VERSION 5.8 ;
BUSBITCHARS "[]" ;
DIVIDERCHAR "/" ;
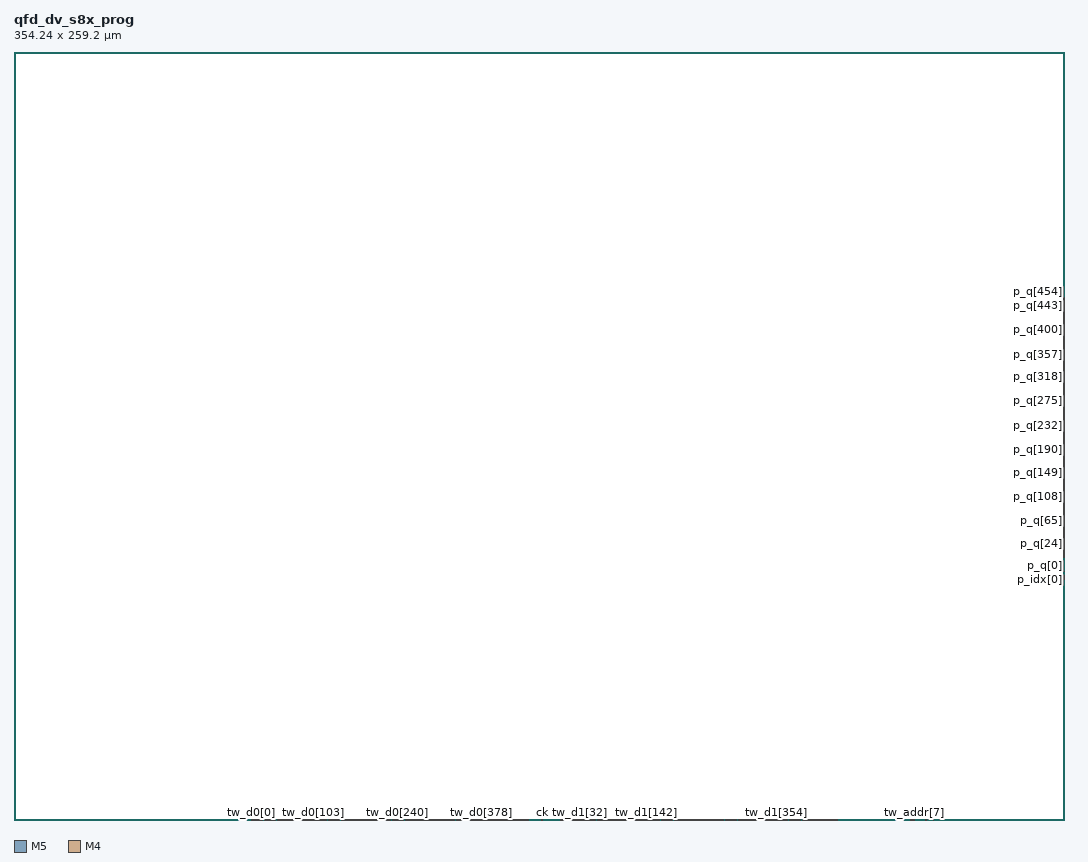
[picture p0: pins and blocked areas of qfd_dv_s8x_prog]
MACRO qfd_dv_s8x_prog
 CLASS BLOCK ;
 ORIGIN 0 0 ;
 SIZE 354.24 BY 259.2 ;
 SYMMETRY X Y ;
 PIN tw_d0[0]
  DIRECTION INPUT ;
  USE SIGNAL ;
  PORT
   LAYER M5 ;
   RECT 80.112000 0.000000 80.136000 0.084000 ;
  END
 END tw_d0[0]
 PIN tw_d0[1]
  DIRECTION INPUT ;
  USE SIGNAL ;
  PORT
   LAYER M5 ;
   RECT 80.304000 0.000000 80.328000 0.084000 ;
  END
 END tw_d0[1]
 PIN tw_d0[2]
  DIRECTION INPUT ;
  USE SIGNAL ;
  PORT
   LAYER M5 ;
   RECT 80.496000 0.000000 80.520000 0.084000 ;
  END
 END tw_d0[2]
 PIN tw_d0[3]
  DIRECTION INPUT ;
  USE SIGNAL ;
  PORT
   LAYER M5 ;
   RECT 80.688000 0.000000 80.712000 0.084000 ;
  END
 END tw_d0[3]
 PIN tw_d0[4]
  DIRECTION INPUT ;
  USE SIGNAL ;
  PORT
   LAYER M5 ;
   RECT 80.880000 0.000000 80.904000 0.084000 ;
  END
 END tw_d0[4]
 PIN tw_d0[5]
  DIRECTION INPUT ;
  USE SIGNAL ;
  PORT
   LAYER M5 ;
   RECT 81.072000 0.000000 81.096000 0.084000 ;
  END
 END tw_d0[5]
 PIN tw_d0[6]
  DIRECTION INPUT ;
  USE SIGNAL ;
  PORT
   LAYER M5 ;
   RECT 81.264000 0.000000 81.288000 0.084000 ;
  END
 END tw_d0[6]
 PIN tw_d0[7]
  DIRECTION INPUT ;
  USE SIGNAL ;
  PORT
   LAYER M5 ;
   RECT 81.456000 0.000000 81.480000 0.084000 ;
  END
 END tw_d0[7]
 PIN tw_d0[8]
  DIRECTION INPUT ;
  USE SIGNAL ;
  PORT
   LAYER M5 ;
   RECT 81.648000 0.000000 81.672000 0.084000 ;
  END
 END tw_d0[8]
 PIN tw_d0[9]
  DIRECTION INPUT ;
  USE SIGNAL ;
  PORT
   LAYER M5 ;
   RECT 81.840000 0.000000 81.864000 0.084000 ;
  END
 END tw_d0[9]
 PIN tw_d0[10]
  DIRECTION INPUT ;
  USE SIGNAL ;
  PORT
   LAYER M5 ;
   RECT 82.032000 0.000000 82.056000 0.084000 ;
  END
 END tw_d0[10]
 PIN tw_d0[11]
  DIRECTION INPUT ;
  USE SIGNAL ;
  PORT
   LAYER M5 ;
   RECT 82.224000 0.000000 82.248000 0.084000 ;
  END
 END tw_d0[11]
 PIN tw_d0[12]
  DIRECTION INPUT ;
  USE SIGNAL ;
  PORT
   LAYER M5 ;
   RECT 82.416000 0.000000 82.440000 0.084000 ;
  END
 END tw_d0[12]
 PIN tw_d0[13]
  DIRECTION INPUT ;
  USE SIGNAL ;
  PORT
   LAYER M5 ;
   RECT 82.608000 0.000000 82.632000 0.084000 ;
  END
 END tw_d0[13]
 PIN tw_d0[14]
  DIRECTION INPUT ;
  USE SIGNAL ;
  PORT
   LAYER M5 ;
   RECT 82.800000 0.000000 82.824000 0.084000 ;
  END
 END tw_d0[14]
 PIN tw_d0[15]
  DIRECTION INPUT ;
  USE SIGNAL ;
  PORT
   LAYER M5 ;
   RECT 82.992000 0.000000 83.016000 0.084000 ;
  END
 END tw_d0[15]
 PIN tw_d0[16]
  DIRECTION INPUT ;
  USE SIGNAL ;
  PORT
   LAYER M5 ;
   RECT 83.184000 0.000000 83.208000 0.084000 ;
  END
 END tw_d0[16]
 PIN tw_d0[17]
  DIRECTION INPUT ;
  USE SIGNAL ;
  PORT
   LAYER M5 ;
   RECT 83.376000 0.000000 83.400000 0.084000 ;
  END
 END tw_d0[17]
 PIN tw_d0[18]
  DIRECTION INPUT ;
  USE SIGNAL ;
  PORT
   LAYER M5 ;
   RECT 83.568000 0.000000 83.592000 0.084000 ;
  END
 END tw_d0[18]
 PIN tw_d0[19]
  DIRECTION INPUT ;
  USE SIGNAL ;
  PORT
   LAYER M5 ;
   RECT 83.760000 0.000000 83.784000 0.084000 ;
  END
 END tw_d0[19]
 PIN tw_d0[20]
  DIRECTION INPUT ;
  USE SIGNAL ;
  PORT
   LAYER M5 ;
   RECT 83.952000 0.000000 83.976000 0.084000 ;
  END
 END tw_d0[20]
 PIN tw_d0[21]
  DIRECTION INPUT ;
  USE SIGNAL ;
  PORT
   LAYER M5 ;
   RECT 84.432000 0.000000 84.456000 0.084000 ;
  END
 END tw_d0[21]
 PIN tw_d0[22]
  DIRECTION INPUT ;
  USE SIGNAL ;
  PORT
   LAYER M5 ;
   RECT 84.624000 0.000000 84.648000 0.084000 ;
  END
 END tw_d0[22]
 PIN tw_d0[23]
  DIRECTION INPUT ;
  USE SIGNAL ;
  PORT
   LAYER M5 ;
   RECT 84.816000 0.000000 84.840000 0.084000 ;
  END
 END tw_d0[23]
 PIN tw_d0[24]
  DIRECTION INPUT ;
  USE SIGNAL ;
  PORT
   LAYER M5 ;
   RECT 85.008000 0.000000 85.032000 0.084000 ;
  END
 END tw_d0[24]
 PIN tw_d0[25]
  DIRECTION INPUT ;
  USE SIGNAL ;
  PORT
   LAYER M5 ;
   RECT 85.200000 0.000000 85.224000 0.084000 ;
  END
 END tw_d0[25]
 PIN tw_d0[26]
  DIRECTION INPUT ;
  USE SIGNAL ;
  PORT
   LAYER M5 ;
   RECT 85.392000 0.000000 85.416000 0.084000 ;
  END
 END tw_d0[26]
 PIN tw_d0[27]
  DIRECTION INPUT ;
  USE SIGNAL ;
  PORT
   LAYER M5 ;
   RECT 85.584000 0.000000 85.608000 0.084000 ;
  END
 END tw_d0[27]
 PIN tw_d0[28]
  DIRECTION INPUT ;
  USE SIGNAL ;
  PORT
   LAYER M5 ;
   RECT 85.776000 0.000000 85.800000 0.084000 ;
  END
 END tw_d0[28]
 PIN tw_d0[29]
  DIRECTION INPUT ;
  USE SIGNAL ;
  PORT
   LAYER M5 ;
   RECT 85.968000 0.000000 85.992000 0.084000 ;
  END
 END tw_d0[29]
 PIN tw_d0[30]
  DIRECTION INPUT ;
  USE SIGNAL ;
  PORT
   LAYER M5 ;
   RECT 86.160000 0.000000 86.184000 0.084000 ;
  END
 END tw_d0[30]
 PIN tw_d0[31]
  DIRECTION INPUT ;
  USE SIGNAL ;
  PORT
   LAYER M5 ;
   RECT 86.352000 0.000000 86.376000 0.084000 ;
  END
 END tw_d0[31]
 PIN tw_d0[32]
  DIRECTION INPUT ;
  USE SIGNAL ;
  PORT
   LAYER M5 ;
   RECT 86.544000 0.000000 86.568000 0.084000 ;
  END
 END tw_d0[32]
 PIN tw_d0[33]
  DIRECTION INPUT ;
  USE SIGNAL ;
  PORT
   LAYER M5 ;
   RECT 86.736000 0.000000 86.760000 0.084000 ;
  END
 END tw_d0[33]
 PIN tw_d0[34]
  DIRECTION INPUT ;
  USE SIGNAL ;
  PORT
   LAYER M5 ;
   RECT 86.928000 0.000000 86.952000 0.084000 ;
  END
 END tw_d0[34]
 PIN tw_d0[35]
  DIRECTION INPUT ;
  USE SIGNAL ;
  PORT
   LAYER M5 ;
   RECT 87.120000 0.000000 87.144000 0.084000 ;
  END
 END tw_d0[35]
 PIN tw_d0[36]
  DIRECTION INPUT ;
  USE SIGNAL ;
  PORT
   LAYER M5 ;
   RECT 87.312000 0.000000 87.336000 0.084000 ;
  END
 END tw_d0[36]
 PIN tw_d0[37]
  DIRECTION INPUT ;
  USE SIGNAL ;
  PORT
   LAYER M5 ;
   RECT 87.504000 0.000000 87.528000 0.084000 ;
  END
 END tw_d0[37]
 PIN tw_d0[38]
  DIRECTION INPUT ;
  USE SIGNAL ;
  PORT
   LAYER M5 ;
   RECT 87.696000 0.000000 87.720000 0.084000 ;
  END
 END tw_d0[38]
 PIN tw_d0[39]
  DIRECTION INPUT ;
  USE SIGNAL ;
  PORT
   LAYER M5 ;
   RECT 87.888000 0.000000 87.912000 0.084000 ;
  END
 END tw_d0[39]
 PIN tw_d0[40]
  DIRECTION INPUT ;
  USE SIGNAL ;
  PORT
   LAYER M5 ;
   RECT 88.080000 0.000000 88.104000 0.084000 ;
  END
 END tw_d0[40]
 PIN tw_d0[41]
  DIRECTION INPUT ;
  USE SIGNAL ;
  PORT
   LAYER M5 ;
   RECT 88.272000 0.000000 88.296000 0.084000 ;
  END
 END tw_d0[41]
 PIN tw_d0[42]
  DIRECTION INPUT ;
  USE SIGNAL ;
  PORT
   LAYER M5 ;
   RECT 88.752000 0.000000 88.776000 0.084000 ;
  END
 END tw_d0[42]
 PIN tw_d0[43]
  DIRECTION INPUT ;
  USE SIGNAL ;
  PORT
   LAYER M5 ;
   RECT 88.944000 0.000000 88.968000 0.084000 ;
  END
 END tw_d0[43]
 PIN tw_d0[44]
  DIRECTION INPUT ;
  USE SIGNAL ;
  PORT
   LAYER M5 ;
   RECT 89.136000 0.000000 89.160000 0.084000 ;
  END
 END tw_d0[44]
 PIN tw_d0[45]
  DIRECTION INPUT ;
  USE SIGNAL ;
  PORT
   LAYER M5 ;
   RECT 89.328000 0.000000 89.352000 0.084000 ;
  END
 END tw_d0[45]
 PIN tw_d0[46]
  DIRECTION INPUT ;
  USE SIGNAL ;
  PORT
   LAYER M5 ;
   RECT 89.520000 0.000000 89.544000 0.084000 ;
  END
 END tw_d0[46]
 PIN tw_d0[47]
  DIRECTION INPUT ;
  USE SIGNAL ;
  PORT
   LAYER M5 ;
   RECT 89.712000 0.000000 89.736000 0.084000 ;
  END
 END tw_d0[47]
 PIN tw_d0[48]
  DIRECTION INPUT ;
  USE SIGNAL ;
  PORT
   LAYER M5 ;
   RECT 89.904000 0.000000 89.928000 0.084000 ;
  END
 END tw_d0[48]
 PIN tw_d0[49]
  DIRECTION INPUT ;
  USE SIGNAL ;
  PORT
   LAYER M5 ;
   RECT 90.096000 0.000000 90.120000 0.084000 ;
  END
 END tw_d0[49]
 PIN tw_d0[50]
  DIRECTION INPUT ;
  USE SIGNAL ;
  PORT
   LAYER M5 ;
   RECT 90.288000 0.000000 90.312000 0.084000 ;
  END
 END tw_d0[50]
 PIN tw_d0[51]
  DIRECTION INPUT ;
  USE SIGNAL ;
  PORT
   LAYER M5 ;
   RECT 90.480000 0.000000 90.504000 0.084000 ;
  END
 END tw_d0[51]
 PIN tw_d0[52]
  DIRECTION INPUT ;
  USE SIGNAL ;
  PORT
   LAYER M5 ;
   RECT 90.672000 0.000000 90.696000 0.084000 ;
  END
 END tw_d0[52]
 PIN tw_d0[53]
  DIRECTION INPUT ;
  USE SIGNAL ;
  PORT
   LAYER M5 ;
   RECT 90.864000 0.000000 90.888000 0.084000 ;
  END
 END tw_d0[53]
 PIN tw_d0[54]
  DIRECTION INPUT ;
  USE SIGNAL ;
  PORT
   LAYER M5 ;
   RECT 91.056000 0.000000 91.080000 0.084000 ;
  END
 END tw_d0[54]
 PIN tw_d0[55]
  DIRECTION INPUT ;
  USE SIGNAL ;
  PORT
   LAYER M5 ;
   RECT 91.248000 0.000000 91.272000 0.084000 ;
  END
 END tw_d0[55]
 PIN tw_d0[56]
  DIRECTION INPUT ;
  USE SIGNAL ;
  PORT
   LAYER M5 ;
   RECT 91.440000 0.000000 91.464000 0.084000 ;
  END
 END tw_d0[56]
 PIN tw_d0[57]
  DIRECTION INPUT ;
  USE SIGNAL ;
  PORT
   LAYER M5 ;
   RECT 91.632000 0.000000 91.656000 0.084000 ;
  END
 END tw_d0[57]
 PIN tw_d0[58]
  DIRECTION INPUT ;
  USE SIGNAL ;
  PORT
   LAYER M5 ;
   RECT 91.824000 0.000000 91.848000 0.084000 ;
  END
 END tw_d0[58]
 PIN tw_d0[59]
  DIRECTION INPUT ;
  USE SIGNAL ;
  PORT
   LAYER M5 ;
   RECT 92.016000 0.000000 92.040000 0.084000 ;
  END
 END tw_d0[59]
 PIN tw_d0[60]
  DIRECTION INPUT ;
  USE SIGNAL ;
  PORT
   LAYER M5 ;
   RECT 92.208000 0.000000 92.232000 0.084000 ;
  END
 END tw_d0[60]
 PIN tw_d0[61]
  DIRECTION INPUT ;
  USE SIGNAL ;
  PORT
   LAYER M5 ;
   RECT 92.400000 0.000000 92.424000 0.084000 ;
  END
 END tw_d0[61]
 PIN tw_d0[62]
  DIRECTION INPUT ;
  USE SIGNAL ;
  PORT
   LAYER M5 ;
   RECT 92.592000 0.000000 92.616000 0.084000 ;
  END
 END tw_d0[62]
 PIN tw_d0[63]
  DIRECTION INPUT ;
  USE SIGNAL ;
  PORT
   LAYER M5 ;
   RECT 93.072000 0.000000 93.096000 0.084000 ;
  END
 END tw_d0[63]
 PIN tw_d0[64]
  DIRECTION INPUT ;
  USE SIGNAL ;
  PORT
   LAYER M5 ;
   RECT 93.264000 0.000000 93.288000 0.084000 ;
  END
 END tw_d0[64]
 PIN tw_d0[65]
  DIRECTION INPUT ;
  USE SIGNAL ;
  PORT
   LAYER M5 ;
   RECT 93.456000 0.000000 93.480000 0.084000 ;
  END
 END tw_d0[65]
 PIN tw_d0[66]
  DIRECTION INPUT ;
  USE SIGNAL ;
  PORT
   LAYER M5 ;
   RECT 93.648000 0.000000 93.672000 0.084000 ;
  END
 END tw_d0[66]
 PIN tw_d0[67]
  DIRECTION INPUT ;
  USE SIGNAL ;
  PORT
   LAYER M5 ;
   RECT 93.840000 0.000000 93.864000 0.084000 ;
  END
 END tw_d0[67]
 PIN tw_d0[68]
  DIRECTION INPUT ;
  USE SIGNAL ;
  PORT
   LAYER M5 ;
   RECT 94.032000 0.000000 94.056000 0.084000 ;
  END
 END tw_d0[68]
 PIN tw_d0[69]
  DIRECTION INPUT ;
  USE SIGNAL ;
  PORT
   LAYER M5 ;
   RECT 94.224000 0.000000 94.248000 0.084000 ;
  END
 END tw_d0[69]
 PIN tw_d0[70]
  DIRECTION INPUT ;
  USE SIGNAL ;
  PORT
   LAYER M5 ;
   RECT 94.416000 0.000000 94.440000 0.084000 ;
  END
 END tw_d0[70]
 PIN tw_d0[71]
  DIRECTION INPUT ;
  USE SIGNAL ;
  PORT
   LAYER M5 ;
   RECT 94.608000 0.000000 94.632000 0.084000 ;
  END
 END tw_d0[71]
 PIN tw_d0[72]
  DIRECTION INPUT ;
  USE SIGNAL ;
  PORT
   LAYER M5 ;
   RECT 94.800000 0.000000 94.824000 0.084000 ;
  END
 END tw_d0[72]
 PIN tw_d0[73]
  DIRECTION INPUT ;
  USE SIGNAL ;
  PORT
   LAYER M5 ;
   RECT 94.992000 0.000000 95.016000 0.084000 ;
  END
 END tw_d0[73]
 PIN tw_d0[74]
  DIRECTION INPUT ;
  USE SIGNAL ;
  PORT
   LAYER M5 ;
   RECT 95.184000 0.000000 95.208000 0.084000 ;
  END
 END tw_d0[74]
 PIN tw_d0[75]
  DIRECTION INPUT ;
  USE SIGNAL ;
  PORT
   LAYER M5 ;
   RECT 95.376000 0.000000 95.400000 0.084000 ;
  END
 END tw_d0[75]
 PIN tw_d0[76]
  DIRECTION INPUT ;
  USE SIGNAL ;
  PORT
   LAYER M5 ;
   RECT 95.568000 0.000000 95.592000 0.084000 ;
  END
 END tw_d0[76]
 PIN tw_d0[77]
  DIRECTION INPUT ;
  USE SIGNAL ;
  PORT
   LAYER M5 ;
   RECT 95.760000 0.000000 95.784000 0.084000 ;
  END
 END tw_d0[77]
 PIN tw_d0[78]
  DIRECTION INPUT ;
  USE SIGNAL ;
  PORT
   LAYER M5 ;
   RECT 95.952000 0.000000 95.976000 0.084000 ;
  END
 END tw_d0[78]
 PIN tw_d0[79]
  DIRECTION INPUT ;
  USE SIGNAL ;
  PORT
   LAYER M5 ;
   RECT 96.144000 0.000000 96.168000 0.084000 ;
  END
 END tw_d0[79]
 PIN tw_d0[80]
  DIRECTION INPUT ;
  USE SIGNAL ;
  PORT
   LAYER M5 ;
   RECT 96.336000 0.000000 96.360000 0.084000 ;
  END
 END tw_d0[80]
 PIN tw_d0[81]
  DIRECTION INPUT ;
  USE SIGNAL ;
  PORT
   LAYER M5 ;
   RECT 96.528000 0.000000 96.552000 0.084000 ;
  END
 END tw_d0[81]
 PIN tw_d0[82]
  DIRECTION INPUT ;
  USE SIGNAL ;
  PORT
   LAYER M5 ;
   RECT 96.720000 0.000000 96.744000 0.084000 ;
  END
 END tw_d0[82]
 PIN tw_d0[83]
  DIRECTION INPUT ;
  USE SIGNAL ;
  PORT
   LAYER M5 ;
   RECT 96.912000 0.000000 96.936000 0.084000 ;
  END
 END tw_d0[83]
 PIN tw_d0[84]
  DIRECTION INPUT ;
  USE SIGNAL ;
  PORT
   LAYER M5 ;
   RECT 97.392000 0.000000 97.416000 0.084000 ;
  END
 END tw_d0[84]
 PIN tw_d0[85]
  DIRECTION INPUT ;
  USE SIGNAL ;
  PORT
   LAYER M5 ;
   RECT 97.584000 0.000000 97.608000 0.084000 ;
  END
 END tw_d0[85]
 PIN tw_d0[86]
  DIRECTION INPUT ;
  USE SIGNAL ;
  PORT
   LAYER M5 ;
   RECT 97.776000 0.000000 97.800000 0.084000 ;
  END
 END tw_d0[86]
 PIN tw_d0[87]
  DIRECTION INPUT ;
  USE SIGNAL ;
  PORT
   LAYER M5 ;
   RECT 97.968000 0.000000 97.992000 0.084000 ;
  END
 END tw_d0[87]
 PIN tw_d0[88]
  DIRECTION INPUT ;
  USE SIGNAL ;
  PORT
   LAYER M5 ;
   RECT 98.160000 0.000000 98.184000 0.084000 ;
  END
 END tw_d0[88]
 PIN tw_d0[89]
  DIRECTION INPUT ;
  USE SIGNAL ;
  PORT
   LAYER M5 ;
   RECT 98.352000 0.000000 98.376000 0.084000 ;
  END
 END tw_d0[89]
 PIN tw_d0[90]
  DIRECTION INPUT ;
  USE SIGNAL ;
  PORT
   LAYER M5 ;
   RECT 98.544000 0.000000 98.568000 0.084000 ;
  END
 END tw_d0[90]
 PIN tw_d0[91]
  DIRECTION INPUT ;
  USE SIGNAL ;
  PORT
   LAYER M5 ;
   RECT 98.736000 0.000000 98.760000 0.084000 ;
  END
 END tw_d0[91]
 PIN tw_d0[92]
  DIRECTION INPUT ;
  USE SIGNAL ;
  PORT
   LAYER M5 ;
   RECT 98.928000 0.000000 98.952000 0.084000 ;
  END
 END tw_d0[92]
 PIN tw_d0[93]
  DIRECTION INPUT ;
  USE SIGNAL ;
  PORT
   LAYER M5 ;
   RECT 99.120000 0.000000 99.144000 0.084000 ;
  END
 END tw_d0[93]
 PIN tw_d0[94]
  DIRECTION INPUT ;
  USE SIGNAL ;
  PORT
   LAYER M5 ;
   RECT 99.312000 0.000000 99.336000 0.084000 ;
  END
 END tw_d0[94]
 PIN tw_d0[95]
  DIRECTION INPUT ;
  USE SIGNAL ;
  PORT
   LAYER M5 ;
   RECT 99.504000 0.000000 99.528000 0.084000 ;
  END
 END tw_d0[95]
 PIN tw_d0[96]
  DIRECTION INPUT ;
  USE SIGNAL ;
  PORT
   LAYER M5 ;
   RECT 99.696000 0.000000 99.720000 0.084000 ;
  END
 END tw_d0[96]
 PIN tw_d0[97]
  DIRECTION INPUT ;
  USE SIGNAL ;
  PORT
   LAYER M5 ;
   RECT 99.888000 0.000000 99.912000 0.084000 ;
  END
 END tw_d0[97]
 PIN tw_d0[98]
  DIRECTION INPUT ;
  USE SIGNAL ;
  PORT
   LAYER M5 ;
   RECT 100.080000 0.000000 100.104000 0.084000 ;
  END
 END tw_d0[98]
 PIN tw_d0[99]
  DIRECTION INPUT ;
  USE SIGNAL ;
  PORT
   LAYER M5 ;
   RECT 100.272000 0.000000 100.296000 0.084000 ;
  END
 END tw_d0[99]
 PIN tw_d0[100]
  DIRECTION INPUT ;
  USE SIGNAL ;
  PORT
   LAYER M5 ;
   RECT 100.464000 0.000000 100.488000 0.084000 ;
  END
 END tw_d0[100]
 PIN tw_d0[101]
  DIRECTION INPUT ;
  USE SIGNAL ;
  PORT
   LAYER M5 ;
   RECT 100.656000 0.000000 100.680000 0.084000 ;
  END
 END tw_d0[101]
 PIN tw_d0[102]
  DIRECTION INPUT ;
  USE SIGNAL ;
  PORT
   LAYER M5 ;
   RECT 100.848000 0.000000 100.872000 0.084000 ;
  END
 END tw_d0[102]
 PIN tw_d0[103]
  DIRECTION INPUT ;
  USE SIGNAL ;
  PORT
   LAYER M5 ;
   RECT 101.040000 0.000000 101.064000 0.084000 ;
  END
 END tw_d0[103]
 PIN tw_d0[104]
  DIRECTION INPUT ;
  USE SIGNAL ;
  PORT
   LAYER M5 ;
   RECT 101.232000 0.000000 101.256000 0.084000 ;
  END
 END tw_d0[104]
 PIN tw_d0[105]
  DIRECTION INPUT ;
  USE SIGNAL ;
  PORT
   LAYER M5 ;
   RECT 101.712000 0.000000 101.736000 0.084000 ;
  END
 END tw_d0[105]
 PIN tw_d0[106]
  DIRECTION INPUT ;
  USE SIGNAL ;
  PORT
   LAYER M5 ;
   RECT 101.904000 0.000000 101.928000 0.084000 ;
  END
 END tw_d0[106]
 PIN tw_d0[107]
  DIRECTION INPUT ;
  USE SIGNAL ;
  PORT
   LAYER M5 ;
   RECT 102.096000 0.000000 102.120000 0.084000 ;
  END
 END tw_d0[107]
 PIN tw_d0[108]
  DIRECTION INPUT ;
  USE SIGNAL ;
  PORT
   LAYER M5 ;
   RECT 102.288000 0.000000 102.312000 0.084000 ;
  END
 END tw_d0[108]
 PIN tw_d0[109]
  DIRECTION INPUT ;
  USE SIGNAL ;
  PORT
   LAYER M5 ;
   RECT 102.480000 0.000000 102.504000 0.084000 ;
  END
 END tw_d0[109]
 PIN tw_d0[110]
  DIRECTION INPUT ;
  USE SIGNAL ;
  PORT
   LAYER M5 ;
   RECT 102.672000 0.000000 102.696000 0.084000 ;
  END
 END tw_d0[110]
 PIN tw_d0[111]
  DIRECTION INPUT ;
  USE SIGNAL ;
  PORT
   LAYER M5 ;
   RECT 102.864000 0.000000 102.888000 0.084000 ;
  END
 END tw_d0[111]
 PIN tw_d0[112]
  DIRECTION INPUT ;
  USE SIGNAL ;
  PORT
   LAYER M5 ;
   RECT 103.056000 0.000000 103.080000 0.084000 ;
  END
 END tw_d0[112]
 PIN tw_d0[113]
  DIRECTION INPUT ;
  USE SIGNAL ;
  PORT
   LAYER M5 ;
   RECT 103.248000 0.000000 103.272000 0.084000 ;
  END
 END tw_d0[113]
 PIN tw_d0[114]
  DIRECTION INPUT ;
  USE SIGNAL ;
  PORT
   LAYER M5 ;
   RECT 103.440000 0.000000 103.464000 0.084000 ;
  END
 END tw_d0[114]
 PIN tw_d0[115]
  DIRECTION INPUT ;
  USE SIGNAL ;
  PORT
   LAYER M5 ;
   RECT 103.632000 0.000000 103.656000 0.084000 ;
  END
 END tw_d0[115]
 PIN tw_d0[116]
  DIRECTION INPUT ;
  USE SIGNAL ;
  PORT
   LAYER M5 ;
   RECT 103.824000 0.000000 103.848000 0.084000 ;
  END
 END tw_d0[116]
 PIN tw_d0[117]
  DIRECTION INPUT ;
  USE SIGNAL ;
  PORT
   LAYER M5 ;
   RECT 104.016000 0.000000 104.040000 0.084000 ;
  END
 END tw_d0[117]
 PIN tw_d0[118]
  DIRECTION INPUT ;
  USE SIGNAL ;
  PORT
   LAYER M5 ;
   RECT 104.208000 0.000000 104.232000 0.084000 ;
  END
 END tw_d0[118]
 PIN tw_d0[119]
  DIRECTION INPUT ;
  USE SIGNAL ;
  PORT
   LAYER M5 ;
   RECT 104.400000 0.000000 104.424000 0.084000 ;
  END
 END tw_d0[119]
 PIN tw_d0[120]
  DIRECTION INPUT ;
  USE SIGNAL ;
  PORT
   LAYER M5 ;
   RECT 104.592000 0.000000 104.616000 0.084000 ;
  END
 END tw_d0[120]
 PIN tw_d0[121]
  DIRECTION INPUT ;
  USE SIGNAL ;
  PORT
   LAYER M5 ;
   RECT 104.784000 0.000000 104.808000 0.084000 ;
  END
 END tw_d0[121]
 PIN tw_d0[122]
  DIRECTION INPUT ;
  USE SIGNAL ;
  PORT
   LAYER M5 ;
   RECT 104.976000 0.000000 105.000000 0.084000 ;
  END
 END tw_d0[122]
 PIN tw_d0[123]
  DIRECTION INPUT ;
  USE SIGNAL ;
  PORT
   LAYER M5 ;
   RECT 105.168000 0.000000 105.192000 0.084000 ;
  END
 END tw_d0[123]
 PIN tw_d0[124]
  DIRECTION INPUT ;
  USE SIGNAL ;
  PORT
   LAYER M5 ;
   RECT 105.360000 0.000000 105.384000 0.084000 ;
  END
 END tw_d0[124]
 PIN tw_d0[125]
  DIRECTION INPUT ;
  USE SIGNAL ;
  PORT
   LAYER M5 ;
   RECT 105.552000 0.000000 105.576000 0.084000 ;
  END
 END tw_d0[125]
 PIN tw_d0[126]
  DIRECTION INPUT ;
  USE SIGNAL ;
  PORT
   LAYER M5 ;
   RECT 106.032000 0.000000 106.056000 0.084000 ;
  END
 END tw_d0[126]
 PIN tw_d0[127]
  DIRECTION INPUT ;
  USE SIGNAL ;
  PORT
   LAYER M5 ;
   RECT 106.224000 0.000000 106.248000 0.084000 ;
  END
 END tw_d0[127]
 PIN tw_d0[128]
  DIRECTION INPUT ;
  USE SIGNAL ;
  PORT
   LAYER M5 ;
   RECT 106.416000 0.000000 106.440000 0.084000 ;
  END
 END tw_d0[128]
 PIN tw_d0[129]
  DIRECTION INPUT ;
  USE SIGNAL ;
  PORT
   LAYER M5 ;
   RECT 106.608000 0.000000 106.632000 0.084000 ;
  END
 END tw_d0[129]
 PIN tw_d0[130]
  DIRECTION INPUT ;
  USE SIGNAL ;
  PORT
   LAYER M5 ;
   RECT 106.800000 0.000000 106.824000 0.084000 ;
  END
 END tw_d0[130]
 PIN tw_d0[131]
  DIRECTION INPUT ;
  USE SIGNAL ;
  PORT
   LAYER M5 ;
   RECT 106.992000 0.000000 107.016000 0.084000 ;
  END
 END tw_d0[131]
 PIN tw_d0[132]
  DIRECTION INPUT ;
  USE SIGNAL ;
  PORT
   LAYER M5 ;
   RECT 107.184000 0.000000 107.208000 0.084000 ;
  END
 END tw_d0[132]
 PIN tw_d0[133]
  DIRECTION INPUT ;
  USE SIGNAL ;
  PORT
   LAYER M5 ;
   RECT 107.376000 0.000000 107.400000 0.084000 ;
  END
 END tw_d0[133]
 PIN tw_d0[134]
  DIRECTION INPUT ;
  USE SIGNAL ;
  PORT
   LAYER M5 ;
   RECT 107.568000 0.000000 107.592000 0.084000 ;
  END
 END tw_d0[134]
 PIN tw_d0[135]
  DIRECTION INPUT ;
  USE SIGNAL ;
  PORT
   LAYER M5 ;
   RECT 107.760000 0.000000 107.784000 0.084000 ;
  END
 END tw_d0[135]
 PIN tw_d0[136]
  DIRECTION INPUT ;
  USE SIGNAL ;
  PORT
   LAYER M5 ;
   RECT 107.952000 0.000000 107.976000 0.084000 ;
  END
 END tw_d0[136]
 PIN tw_d0[137]
  DIRECTION INPUT ;
  USE SIGNAL ;
  PORT
   LAYER M5 ;
   RECT 108.144000 0.000000 108.168000 0.084000 ;
  END
 END tw_d0[137]
 PIN tw_d0[138]
  DIRECTION INPUT ;
  USE SIGNAL ;
  PORT
   LAYER M5 ;
   RECT 108.336000 0.000000 108.360000 0.084000 ;
  END
 END tw_d0[138]
 PIN tw_d0[139]
  DIRECTION INPUT ;
  USE SIGNAL ;
  PORT
   LAYER M5 ;
   RECT 108.528000 0.000000 108.552000 0.084000 ;
  END
 END tw_d0[139]
 PIN tw_d0[140]
  DIRECTION INPUT ;
  USE SIGNAL ;
  PORT
   LAYER M5 ;
   RECT 108.720000 0.000000 108.744000 0.084000 ;
  END
 END tw_d0[140]
 PIN tw_d0[141]
  DIRECTION INPUT ;
  USE SIGNAL ;
  PORT
   LAYER M5 ;
   RECT 108.912000 0.000000 108.936000 0.084000 ;
  END
 END tw_d0[141]
 PIN tw_d0[142]
  DIRECTION INPUT ;
  USE SIGNAL ;
  PORT
   LAYER M5 ;
   RECT 109.104000 0.000000 109.128000 0.084000 ;
  END
 END tw_d0[142]
 PIN tw_d0[143]
  DIRECTION INPUT ;
  USE SIGNAL ;
  PORT
   LAYER M5 ;
   RECT 109.296000 0.000000 109.320000 0.084000 ;
  END
 END tw_d0[143]
 PIN tw_d0[144]
  DIRECTION INPUT ;
  USE SIGNAL ;
  PORT
   LAYER M5 ;
   RECT 109.488000 0.000000 109.512000 0.084000 ;
  END
 END tw_d0[144]
 PIN tw_d0[145]
  DIRECTION INPUT ;
  USE SIGNAL ;
  PORT
   LAYER M5 ;
   RECT 109.680000 0.000000 109.704000 0.084000 ;
  END
 END tw_d0[145]
 PIN tw_d0[146]
  DIRECTION INPUT ;
  USE SIGNAL ;
  PORT
   LAYER M5 ;
   RECT 109.872000 0.000000 109.896000 0.084000 ;
  END
 END tw_d0[146]
 PIN tw_d0[147]
  DIRECTION INPUT ;
  USE SIGNAL ;
  PORT
   LAYER M5 ;
   RECT 110.352000 0.000000 110.376000 0.084000 ;
  END
 END tw_d0[147]
 PIN tw_d0[148]
  DIRECTION INPUT ;
  USE SIGNAL ;
  PORT
   LAYER M5 ;
   RECT 110.544000 0.000000 110.568000 0.084000 ;
  END
 END tw_d0[148]
 PIN tw_d0[149]
  DIRECTION INPUT ;
  USE SIGNAL ;
  PORT
   LAYER M5 ;
   RECT 110.736000 0.000000 110.760000 0.084000 ;
  END
 END tw_d0[149]
 PIN tw_d0[150]
  DIRECTION INPUT ;
  USE SIGNAL ;
  PORT
   LAYER M5 ;
   RECT 110.928000 0.000000 110.952000 0.084000 ;
  END
 END tw_d0[150]
 PIN tw_d0[151]
  DIRECTION INPUT ;
  USE SIGNAL ;
  PORT
   LAYER M5 ;
   RECT 111.120000 0.000000 111.144000 0.084000 ;
  END
 END tw_d0[151]
 PIN tw_d0[152]
  DIRECTION INPUT ;
  USE SIGNAL ;
  PORT
   LAYER M5 ;
   RECT 111.312000 0.000000 111.336000 0.084000 ;
  END
 END tw_d0[152]
 PIN tw_d0[153]
  DIRECTION INPUT ;
  USE SIGNAL ;
  PORT
   LAYER M5 ;
   RECT 111.504000 0.000000 111.528000 0.084000 ;
  END
 END tw_d0[153]
 PIN tw_d0[154]
  DIRECTION INPUT ;
  USE SIGNAL ;
  PORT
   LAYER M5 ;
   RECT 111.696000 0.000000 111.720000 0.084000 ;
  END
 END tw_d0[154]
 PIN tw_d0[155]
  DIRECTION INPUT ;
  USE SIGNAL ;
  PORT
   LAYER M5 ;
   RECT 111.888000 0.000000 111.912000 0.084000 ;
  END
 END tw_d0[155]
 PIN tw_d0[156]
  DIRECTION INPUT ;
  USE SIGNAL ;
  PORT
   LAYER M5 ;
   RECT 112.080000 0.000000 112.104000 0.084000 ;
  END
 END tw_d0[156]
 PIN tw_d0[157]
  DIRECTION INPUT ;
  USE SIGNAL ;
  PORT
   LAYER M5 ;
   RECT 112.272000 0.000000 112.296000 0.084000 ;
  END
 END tw_d0[157]
 PIN tw_d0[158]
  DIRECTION INPUT ;
  USE SIGNAL ;
  PORT
   LAYER M5 ;
   RECT 112.464000 0.000000 112.488000 0.084000 ;
  END
 END tw_d0[158]
 PIN tw_d0[159]
  DIRECTION INPUT ;
  USE SIGNAL ;
  PORT
   LAYER M5 ;
   RECT 112.656000 0.000000 112.680000 0.084000 ;
  END
 END tw_d0[159]
 PIN tw_d0[160]
  DIRECTION INPUT ;
  USE SIGNAL ;
  PORT
   LAYER M5 ;
   RECT 112.848000 0.000000 112.872000 0.084000 ;
  END
 END tw_d0[160]
 PIN tw_d0[161]
  DIRECTION INPUT ;
  USE SIGNAL ;
  PORT
   LAYER M5 ;
   RECT 113.040000 0.000000 113.064000 0.084000 ;
  END
 END tw_d0[161]
 PIN tw_d0[162]
  DIRECTION INPUT ;
  USE SIGNAL ;
  PORT
   LAYER M5 ;
   RECT 113.232000 0.000000 113.256000 0.084000 ;
  END
 END tw_d0[162]
 PIN tw_d0[163]
  DIRECTION INPUT ;
  USE SIGNAL ;
  PORT
   LAYER M5 ;
   RECT 113.424000 0.000000 113.448000 0.084000 ;
  END
 END tw_d0[163]
 PIN tw_d0[164]
  DIRECTION INPUT ;
  USE SIGNAL ;
  PORT
   LAYER M5 ;
   RECT 113.616000 0.000000 113.640000 0.084000 ;
  END
 END tw_d0[164]
 PIN tw_d0[165]
  DIRECTION INPUT ;
  USE SIGNAL ;
  PORT
   LAYER M5 ;
   RECT 113.808000 0.000000 113.832000 0.084000 ;
  END
 END tw_d0[165]
 PIN tw_d0[166]
  DIRECTION INPUT ;
  USE SIGNAL ;
  PORT
   LAYER M5 ;
   RECT 114.000000 0.000000 114.024000 0.084000 ;
  END
 END tw_d0[166]
 PIN tw_d0[167]
  DIRECTION INPUT ;
  USE SIGNAL ;
  PORT
   LAYER M5 ;
   RECT 114.192000 0.000000 114.216000 0.084000 ;
  END
 END tw_d0[167]
 PIN tw_d0[168]
  DIRECTION INPUT ;
  USE SIGNAL ;
  PORT
   LAYER M5 ;
   RECT 114.672000 0.000000 114.696000 0.084000 ;
  END
 END tw_d0[168]
 PIN tw_d0[169]
  DIRECTION INPUT ;
  USE SIGNAL ;
  PORT
   LAYER M5 ;
   RECT 114.864000 0.000000 114.888000 0.084000 ;
  END
 END tw_d0[169]
 PIN tw_d0[170]
  DIRECTION INPUT ;
  USE SIGNAL ;
  PORT
   LAYER M5 ;
   RECT 115.056000 0.000000 115.080000 0.084000 ;
  END
 END tw_d0[170]
 PIN tw_d0[171]
  DIRECTION INPUT ;
  USE SIGNAL ;
  PORT
   LAYER M5 ;
   RECT 115.248000 0.000000 115.272000 0.084000 ;
  END
 END tw_d0[171]
 PIN tw_d0[172]
  DIRECTION INPUT ;
  USE SIGNAL ;
  PORT
   LAYER M5 ;
   RECT 115.440000 0.000000 115.464000 0.084000 ;
  END
 END tw_d0[172]
 PIN tw_d0[173]
  DIRECTION INPUT ;
  USE SIGNAL ;
  PORT
   LAYER M5 ;
   RECT 115.632000 0.000000 115.656000 0.084000 ;
  END
 END tw_d0[173]
 PIN tw_d0[174]
  DIRECTION INPUT ;
  USE SIGNAL ;
  PORT
   LAYER M5 ;
   RECT 115.824000 0.000000 115.848000 0.084000 ;
  END
 END tw_d0[174]
 PIN tw_d0[175]
  DIRECTION INPUT ;
  USE SIGNAL ;
  PORT
   LAYER M5 ;
   RECT 116.016000 0.000000 116.040000 0.084000 ;
  END
 END tw_d0[175]
 PIN tw_d0[176]
  DIRECTION INPUT ;
  USE SIGNAL ;
  PORT
   LAYER M5 ;
   RECT 116.208000 0.000000 116.232000 0.084000 ;
  END
 END tw_d0[176]
 PIN tw_d0[177]
  DIRECTION INPUT ;
  USE SIGNAL ;
  PORT
   LAYER M5 ;
   RECT 116.400000 0.000000 116.424000 0.084000 ;
  END
 END tw_d0[177]
 PIN tw_d0[178]
  DIRECTION INPUT ;
  USE SIGNAL ;
  PORT
   LAYER M5 ;
   RECT 116.592000 0.000000 116.616000 0.084000 ;
  END
 END tw_d0[178]
 PIN tw_d0[179]
  DIRECTION INPUT ;
  USE SIGNAL ;
  PORT
   LAYER M5 ;
   RECT 116.784000 0.000000 116.808000 0.084000 ;
  END
 END tw_d0[179]
 PIN tw_d0[180]
  DIRECTION INPUT ;
  USE SIGNAL ;
  PORT
   LAYER M5 ;
   RECT 116.976000 0.000000 117.000000 0.084000 ;
  END
 END tw_d0[180]
 PIN tw_d0[181]
  DIRECTION INPUT ;
  USE SIGNAL ;
  PORT
   LAYER M5 ;
   RECT 117.168000 0.000000 117.192000 0.084000 ;
  END
 END tw_d0[181]
 PIN tw_d0[182]
  DIRECTION INPUT ;
  USE SIGNAL ;
  PORT
   LAYER M5 ;
   RECT 117.360000 0.000000 117.384000 0.084000 ;
  END
 END tw_d0[182]
 PIN tw_d0[183]
  DIRECTION INPUT ;
  USE SIGNAL ;
  PORT
   LAYER M5 ;
   RECT 117.552000 0.000000 117.576000 0.084000 ;
  END
 END tw_d0[183]
 PIN tw_d0[184]
  DIRECTION INPUT ;
  USE SIGNAL ;
  PORT
   LAYER M5 ;
   RECT 117.744000 0.000000 117.768000 0.084000 ;
  END
 END tw_d0[184]
 PIN tw_d0[185]
  DIRECTION INPUT ;
  USE SIGNAL ;
  PORT
   LAYER M5 ;
   RECT 117.936000 0.000000 117.960000 0.084000 ;
  END
 END tw_d0[185]
 PIN tw_d0[186]
  DIRECTION INPUT ;
  USE SIGNAL ;
  PORT
   LAYER M5 ;
   RECT 118.128000 0.000000 118.152000 0.084000 ;
  END
 END tw_d0[186]
 PIN tw_d0[187]
  DIRECTION INPUT ;
  USE SIGNAL ;
  PORT
   LAYER M5 ;
   RECT 118.320000 0.000000 118.344000 0.084000 ;
  END
 END tw_d0[187]
 PIN tw_d0[188]
  DIRECTION INPUT ;
  USE SIGNAL ;
  PORT
   LAYER M5 ;
   RECT 118.512000 0.000000 118.536000 0.084000 ;
  END
 END tw_d0[188]
 PIN tw_d0[189]
  DIRECTION INPUT ;
  USE SIGNAL ;
  PORT
   LAYER M5 ;
   RECT 118.992000 0.000000 119.016000 0.084000 ;
  END
 END tw_d0[189]
 PIN tw_d0[190]
  DIRECTION INPUT ;
  USE SIGNAL ;
  PORT
   LAYER M5 ;
   RECT 119.184000 0.000000 119.208000 0.084000 ;
  END
 END tw_d0[190]
 PIN tw_d0[191]
  DIRECTION INPUT ;
  USE SIGNAL ;
  PORT
   LAYER M5 ;
   RECT 119.376000 0.000000 119.400000 0.084000 ;
  END
 END tw_d0[191]
 PIN tw_d0[192]
  DIRECTION INPUT ;
  USE SIGNAL ;
  PORT
   LAYER M5 ;
   RECT 119.568000 0.000000 119.592000 0.084000 ;
  END
 END tw_d0[192]
 PIN tw_d0[193]
  DIRECTION INPUT ;
  USE SIGNAL ;
  PORT
   LAYER M5 ;
   RECT 119.760000 0.000000 119.784000 0.084000 ;
  END
 END tw_d0[193]
 PIN tw_d0[194]
  DIRECTION INPUT ;
  USE SIGNAL ;
  PORT
   LAYER M5 ;
   RECT 119.952000 0.000000 119.976000 0.084000 ;
  END
 END tw_d0[194]
 PIN tw_d0[195]
  DIRECTION INPUT ;
  USE SIGNAL ;
  PORT
   LAYER M5 ;
   RECT 120.144000 0.000000 120.168000 0.084000 ;
  END
 END tw_d0[195]
 PIN tw_d0[196]
  DIRECTION INPUT ;
  USE SIGNAL ;
  PORT
   LAYER M5 ;
   RECT 120.336000 0.000000 120.360000 0.084000 ;
  END
 END tw_d0[196]
 PIN tw_d0[197]
  DIRECTION INPUT ;
  USE SIGNAL ;
  PORT
   LAYER M5 ;
   RECT 120.528000 0.000000 120.552000 0.084000 ;
  END
 END tw_d0[197]
 PIN tw_d0[198]
  DIRECTION INPUT ;
  USE SIGNAL ;
  PORT
   LAYER M5 ;
   RECT 120.720000 0.000000 120.744000 0.084000 ;
  END
 END tw_d0[198]
 PIN tw_d0[199]
  DIRECTION INPUT ;
  USE SIGNAL ;
  PORT
   LAYER M5 ;
   RECT 120.912000 0.000000 120.936000 0.084000 ;
  END
 END tw_d0[199]
 PIN tw_d0[200]
  DIRECTION INPUT ;
  USE SIGNAL ;
  PORT
   LAYER M5 ;
   RECT 121.104000 0.000000 121.128000 0.084000 ;
  END
 END tw_d0[200]
 PIN tw_d0[201]
  DIRECTION INPUT ;
  USE SIGNAL ;
  PORT
   LAYER M5 ;
   RECT 121.296000 0.000000 121.320000 0.084000 ;
  END
 END tw_d0[201]
 PIN tw_d0[202]
  DIRECTION INPUT ;
  USE SIGNAL ;
  PORT
   LAYER M5 ;
   RECT 121.488000 0.000000 121.512000 0.084000 ;
  END
 END tw_d0[202]
 PIN tw_d0[203]
  DIRECTION INPUT ;
  USE SIGNAL ;
  PORT
   LAYER M5 ;
   RECT 121.680000 0.000000 121.704000 0.084000 ;
  END
 END tw_d0[203]
 PIN tw_d0[204]
  DIRECTION INPUT ;
  USE SIGNAL ;
  PORT
   LAYER M5 ;
   RECT 121.872000 0.000000 121.896000 0.084000 ;
  END
 END tw_d0[204]
 PIN tw_d0[205]
  DIRECTION INPUT ;
  USE SIGNAL ;
  PORT
   LAYER M5 ;
   RECT 122.064000 0.000000 122.088000 0.084000 ;
  END
 END tw_d0[205]
 PIN tw_d0[206]
  DIRECTION INPUT ;
  USE SIGNAL ;
  PORT
   LAYER M5 ;
   RECT 122.256000 0.000000 122.280000 0.084000 ;
  END
 END tw_d0[206]
 PIN tw_d0[207]
  DIRECTION INPUT ;
  USE SIGNAL ;
  PORT
   LAYER M5 ;
   RECT 122.448000 0.000000 122.472000 0.084000 ;
  END
 END tw_d0[207]
 PIN tw_d0[208]
  DIRECTION INPUT ;
  USE SIGNAL ;
  PORT
   LAYER M5 ;
   RECT 122.640000 0.000000 122.664000 0.084000 ;
  END
 END tw_d0[208]
 PIN tw_d0[209]
  DIRECTION INPUT ;
  USE SIGNAL ;
  PORT
   LAYER M5 ;
   RECT 122.832000 0.000000 122.856000 0.084000 ;
  END
 END tw_d0[209]
 PIN tw_d0[210]
  DIRECTION INPUT ;
  USE SIGNAL ;
  PORT
   LAYER M5 ;
   RECT 123.312000 0.000000 123.336000 0.084000 ;
  END
 END tw_d0[210]
 PIN tw_d0[211]
  DIRECTION INPUT ;
  USE SIGNAL ;
  PORT
   LAYER M5 ;
   RECT 123.504000 0.000000 123.528000 0.084000 ;
  END
 END tw_d0[211]
 PIN tw_d0[212]
  DIRECTION INPUT ;
  USE SIGNAL ;
  PORT
   LAYER M5 ;
   RECT 123.696000 0.000000 123.720000 0.084000 ;
  END
 END tw_d0[212]
 PIN tw_d0[213]
  DIRECTION INPUT ;
  USE SIGNAL ;
  PORT
   LAYER M5 ;
   RECT 123.888000 0.000000 123.912000 0.084000 ;
  END
 END tw_d0[213]
 PIN tw_d0[214]
  DIRECTION INPUT ;
  USE SIGNAL ;
  PORT
   LAYER M5 ;
   RECT 124.080000 0.000000 124.104000 0.084000 ;
  END
 END tw_d0[214]
 PIN tw_d0[215]
  DIRECTION INPUT ;
  USE SIGNAL ;
  PORT
   LAYER M5 ;
   RECT 124.272000 0.000000 124.296000 0.084000 ;
  END
 END tw_d0[215]
 PIN tw_d0[216]
  DIRECTION INPUT ;
  USE SIGNAL ;
  PORT
   LAYER M5 ;
   RECT 124.464000 0.000000 124.488000 0.084000 ;
  END
 END tw_d0[216]
 PIN tw_d0[217]
  DIRECTION INPUT ;
  USE SIGNAL ;
  PORT
   LAYER M5 ;
   RECT 124.656000 0.000000 124.680000 0.084000 ;
  END
 END tw_d0[217]
 PIN tw_d0[218]
  DIRECTION INPUT ;
  USE SIGNAL ;
  PORT
   LAYER M5 ;
   RECT 124.848000 0.000000 124.872000 0.084000 ;
  END
 END tw_d0[218]
 PIN tw_d0[219]
  DIRECTION INPUT ;
  USE SIGNAL ;
  PORT
   LAYER M5 ;
   RECT 125.040000 0.000000 125.064000 0.084000 ;
  END
 END tw_d0[219]
 PIN tw_d0[220]
  DIRECTION INPUT ;
  USE SIGNAL ;
  PORT
   LAYER M5 ;
   RECT 125.232000 0.000000 125.256000 0.084000 ;
  END
 END tw_d0[220]
 PIN tw_d0[221]
  DIRECTION INPUT ;
  USE SIGNAL ;
  PORT
   LAYER M5 ;
   RECT 125.424000 0.000000 125.448000 0.084000 ;
  END
 END tw_d0[221]
 PIN tw_d0[222]
  DIRECTION INPUT ;
  USE SIGNAL ;
  PORT
   LAYER M5 ;
   RECT 125.616000 0.000000 125.640000 0.084000 ;
  END
 END tw_d0[222]
 PIN tw_d0[223]
  DIRECTION INPUT ;
  USE SIGNAL ;
  PORT
   LAYER M5 ;
   RECT 125.808000 0.000000 125.832000 0.084000 ;
  END
 END tw_d0[223]
 PIN tw_d0[224]
  DIRECTION INPUT ;
  USE SIGNAL ;
  PORT
   LAYER M5 ;
   RECT 126.000000 0.000000 126.024000 0.084000 ;
  END
 END tw_d0[224]
 PIN tw_d0[225]
  DIRECTION INPUT ;
  USE SIGNAL ;
  PORT
   LAYER M5 ;
   RECT 126.192000 0.000000 126.216000 0.084000 ;
  END
 END tw_d0[225]
 PIN tw_d0[226]
  DIRECTION INPUT ;
  USE SIGNAL ;
  PORT
   LAYER M5 ;
   RECT 126.384000 0.000000 126.408000 0.084000 ;
  END
 END tw_d0[226]
 PIN tw_d0[227]
  DIRECTION INPUT ;
  USE SIGNAL ;
  PORT
   LAYER M5 ;
   RECT 126.576000 0.000000 126.600000 0.084000 ;
  END
 END tw_d0[227]
 PIN tw_d0[228]
  DIRECTION INPUT ;
  USE SIGNAL ;
  PORT
   LAYER M5 ;
   RECT 126.768000 0.000000 126.792000 0.084000 ;
  END
 END tw_d0[228]
 PIN tw_d0[229]
  DIRECTION INPUT ;
  USE SIGNAL ;
  PORT
   LAYER M5 ;
   RECT 126.960000 0.000000 126.984000 0.084000 ;
  END
 END tw_d0[229]
 PIN tw_d0[230]
  DIRECTION INPUT ;
  USE SIGNAL ;
  PORT
   LAYER M5 ;
   RECT 127.152000 0.000000 127.176000 0.084000 ;
  END
 END tw_d0[230]
 PIN tw_d0[231]
  DIRECTION INPUT ;
  USE SIGNAL ;
  PORT
   LAYER M5 ;
   RECT 127.632000 0.000000 127.656000 0.084000 ;
  END
 END tw_d0[231]
 PIN tw_d0[232]
  DIRECTION INPUT ;
  USE SIGNAL ;
  PORT
   LAYER M5 ;
   RECT 127.824000 0.000000 127.848000 0.084000 ;
  END
 END tw_d0[232]
 PIN tw_d0[233]
  DIRECTION INPUT ;
  USE SIGNAL ;
  PORT
   LAYER M5 ;
   RECT 128.016000 0.000000 128.040000 0.084000 ;
  END
 END tw_d0[233]
 PIN tw_d0[234]
  DIRECTION INPUT ;
  USE SIGNAL ;
  PORT
   LAYER M5 ;
   RECT 128.208000 0.000000 128.232000 0.084000 ;
  END
 END tw_d0[234]
 PIN tw_d0[235]
  DIRECTION INPUT ;
  USE SIGNAL ;
  PORT
   LAYER M5 ;
   RECT 128.400000 0.000000 128.424000 0.084000 ;
  END
 END tw_d0[235]
 PIN tw_d0[236]
  DIRECTION INPUT ;
  USE SIGNAL ;
  PORT
   LAYER M5 ;
   RECT 128.592000 0.000000 128.616000 0.084000 ;
  END
 END tw_d0[236]
 PIN tw_d0[237]
  DIRECTION INPUT ;
  USE SIGNAL ;
  PORT
   LAYER M5 ;
   RECT 128.784000 0.000000 128.808000 0.084000 ;
  END
 END tw_d0[237]
 PIN tw_d0[238]
  DIRECTION INPUT ;
  USE SIGNAL ;
  PORT
   LAYER M5 ;
   RECT 128.976000 0.000000 129.000000 0.084000 ;
  END
 END tw_d0[238]
 PIN tw_d0[239]
  DIRECTION INPUT ;
  USE SIGNAL ;
  PORT
   LAYER M5 ;
   RECT 129.168000 0.000000 129.192000 0.084000 ;
  END
 END tw_d0[239]
 PIN tw_d0[240]
  DIRECTION INPUT ;
  USE SIGNAL ;
  PORT
   LAYER M5 ;
   RECT 129.360000 0.000000 129.384000 0.084000 ;
  END
 END tw_d0[240]
 PIN tw_d0[241]
  DIRECTION INPUT ;
  USE SIGNAL ;
  PORT
   LAYER M5 ;
   RECT 129.552000 0.000000 129.576000 0.084000 ;
  END
 END tw_d0[241]
 PIN tw_d0[242]
  DIRECTION INPUT ;
  USE SIGNAL ;
  PORT
   LAYER M5 ;
   RECT 129.744000 0.000000 129.768000 0.084000 ;
  END
 END tw_d0[242]
 PIN tw_d0[243]
  DIRECTION INPUT ;
  USE SIGNAL ;
  PORT
   LAYER M5 ;
   RECT 129.936000 0.000000 129.960000 0.084000 ;
  END
 END tw_d0[243]
 PIN tw_d0[244]
  DIRECTION INPUT ;
  USE SIGNAL ;
  PORT
   LAYER M5 ;
   RECT 130.128000 0.000000 130.152000 0.084000 ;
  END
 END tw_d0[244]
 PIN tw_d0[245]
  DIRECTION INPUT ;
  USE SIGNAL ;
  PORT
   LAYER M5 ;
   RECT 130.320000 0.000000 130.344000 0.084000 ;
  END
 END tw_d0[245]
 PIN tw_d0[246]
  DIRECTION INPUT ;
  USE SIGNAL ;
  PORT
   LAYER M5 ;
   RECT 130.512000 0.000000 130.536000 0.084000 ;
  END
 END tw_d0[246]
 PIN tw_d0[247]
  DIRECTION INPUT ;
  USE SIGNAL ;
  PORT
   LAYER M5 ;
   RECT 130.704000 0.000000 130.728000 0.084000 ;
  END
 END tw_d0[247]
 PIN tw_d0[248]
  DIRECTION INPUT ;
  USE SIGNAL ;
  PORT
   LAYER M5 ;
   RECT 130.896000 0.000000 130.920000 0.084000 ;
  END
 END tw_d0[248]
 PIN tw_d0[249]
  DIRECTION INPUT ;
  USE SIGNAL ;
  PORT
   LAYER M5 ;
   RECT 131.088000 0.000000 131.112000 0.084000 ;
  END
 END tw_d0[249]
 PIN tw_d0[250]
  DIRECTION INPUT ;
  USE SIGNAL ;
  PORT
   LAYER M5 ;
   RECT 131.280000 0.000000 131.304000 0.084000 ;
  END
 END tw_d0[250]
 PIN tw_d0[251]
  DIRECTION INPUT ;
  USE SIGNAL ;
  PORT
   LAYER M5 ;
   RECT 131.472000 0.000000 131.496000 0.084000 ;
  END
 END tw_d0[251]
 PIN tw_d0[252]
  DIRECTION INPUT ;
  USE SIGNAL ;
  PORT
   LAYER M5 ;
   RECT 131.952000 0.000000 131.976000 0.084000 ;
  END
 END tw_d0[252]
 PIN tw_d0[253]
  DIRECTION INPUT ;
  USE SIGNAL ;
  PORT
   LAYER M5 ;
   RECT 132.144000 0.000000 132.168000 0.084000 ;
  END
 END tw_d0[253]
 PIN tw_d0[254]
  DIRECTION INPUT ;
  USE SIGNAL ;
  PORT
   LAYER M5 ;
   RECT 132.336000 0.000000 132.360000 0.084000 ;
  END
 END tw_d0[254]
 PIN tw_d0[255]
  DIRECTION INPUT ;
  USE SIGNAL ;
  PORT
   LAYER M5 ;
   RECT 132.528000 0.000000 132.552000 0.084000 ;
  END
 END tw_d0[255]
 PIN tw_d0[256]
  DIRECTION INPUT ;
  USE SIGNAL ;
  PORT
   LAYER M5 ;
   RECT 132.720000 0.000000 132.744000 0.084000 ;
  END
 END tw_d0[256]
 PIN tw_d0[257]
  DIRECTION INPUT ;
  USE SIGNAL ;
  PORT
   LAYER M5 ;
   RECT 132.912000 0.000000 132.936000 0.084000 ;
  END
 END tw_d0[257]
 PIN tw_d0[258]
  DIRECTION INPUT ;
  USE SIGNAL ;
  PORT
   LAYER M5 ;
   RECT 133.104000 0.000000 133.128000 0.084000 ;
  END
 END tw_d0[258]
 PIN tw_d0[259]
  DIRECTION INPUT ;
  USE SIGNAL ;
  PORT
   LAYER M5 ;
   RECT 133.296000 0.000000 133.320000 0.084000 ;
  END
 END tw_d0[259]
 PIN tw_d0[260]
  DIRECTION INPUT ;
  USE SIGNAL ;
  PORT
   LAYER M5 ;
   RECT 133.488000 0.000000 133.512000 0.084000 ;
  END
 END tw_d0[260]
 PIN tw_d0[261]
  DIRECTION INPUT ;
  USE SIGNAL ;
  PORT
   LAYER M5 ;
   RECT 133.680000 0.000000 133.704000 0.084000 ;
  END
 END tw_d0[261]
 PIN tw_d0[262]
  DIRECTION INPUT ;
  USE SIGNAL ;
  PORT
   LAYER M5 ;
   RECT 133.872000 0.000000 133.896000 0.084000 ;
  END
 END tw_d0[262]
 PIN tw_d0[263]
  DIRECTION INPUT ;
  USE SIGNAL ;
  PORT
   LAYER M5 ;
   RECT 134.064000 0.000000 134.088000 0.084000 ;
  END
 END tw_d0[263]
 PIN tw_d0[264]
  DIRECTION INPUT ;
  USE SIGNAL ;
  PORT
   LAYER M5 ;
   RECT 134.256000 0.000000 134.280000 0.084000 ;
  END
 END tw_d0[264]
 PIN tw_d0[265]
  DIRECTION INPUT ;
  USE SIGNAL ;
  PORT
   LAYER M5 ;
   RECT 134.448000 0.000000 134.472000 0.084000 ;
  END
 END tw_d0[265]
 PIN tw_d0[266]
  DIRECTION INPUT ;
  USE SIGNAL ;
  PORT
   LAYER M5 ;
   RECT 134.640000 0.000000 134.664000 0.084000 ;
  END
 END tw_d0[266]
 PIN tw_d0[267]
  DIRECTION INPUT ;
  USE SIGNAL ;
  PORT
   LAYER M5 ;
   RECT 134.832000 0.000000 134.856000 0.084000 ;
  END
 END tw_d0[267]
 PIN tw_d0[268]
  DIRECTION INPUT ;
  USE SIGNAL ;
  PORT
   LAYER M5 ;
   RECT 135.024000 0.000000 135.048000 0.084000 ;
  END
 END tw_d0[268]
 PIN tw_d0[269]
  DIRECTION INPUT ;
  USE SIGNAL ;
  PORT
   LAYER M5 ;
   RECT 135.216000 0.000000 135.240000 0.084000 ;
  END
 END tw_d0[269]
 PIN tw_d0[270]
  DIRECTION INPUT ;
  USE SIGNAL ;
  PORT
   LAYER M5 ;
   RECT 135.408000 0.000000 135.432000 0.084000 ;
  END
 END tw_d0[270]
 PIN tw_d0[271]
  DIRECTION INPUT ;
  USE SIGNAL ;
  PORT
   LAYER M5 ;
   RECT 135.600000 0.000000 135.624000 0.084000 ;
  END
 END tw_d0[271]
 PIN tw_d0[272]
  DIRECTION INPUT ;
  USE SIGNAL ;
  PORT
   LAYER M5 ;
   RECT 135.792000 0.000000 135.816000 0.084000 ;
  END
 END tw_d0[272]
 PIN tw_d0[273]
  DIRECTION INPUT ;
  USE SIGNAL ;
  PORT
   LAYER M5 ;
   RECT 136.272000 0.000000 136.296000 0.084000 ;
  END
 END tw_d0[273]
 PIN tw_d0[274]
  DIRECTION INPUT ;
  USE SIGNAL ;
  PORT
   LAYER M5 ;
   RECT 136.464000 0.000000 136.488000 0.084000 ;
  END
 END tw_d0[274]
 PIN tw_d0[275]
  DIRECTION INPUT ;
  USE SIGNAL ;
  PORT
   LAYER M5 ;
   RECT 136.656000 0.000000 136.680000 0.084000 ;
  END
 END tw_d0[275]
 PIN tw_d0[276]
  DIRECTION INPUT ;
  USE SIGNAL ;
  PORT
   LAYER M5 ;
   RECT 136.848000 0.000000 136.872000 0.084000 ;
  END
 END tw_d0[276]
 PIN tw_d0[277]
  DIRECTION INPUT ;
  USE SIGNAL ;
  PORT
   LAYER M5 ;
   RECT 137.040000 0.000000 137.064000 0.084000 ;
  END
 END tw_d0[277]
 PIN tw_d0[278]
  DIRECTION INPUT ;
  USE SIGNAL ;
  PORT
   LAYER M5 ;
   RECT 137.232000 0.000000 137.256000 0.084000 ;
  END
 END tw_d0[278]
 PIN tw_d0[279]
  DIRECTION INPUT ;
  USE SIGNAL ;
  PORT
   LAYER M5 ;
   RECT 137.424000 0.000000 137.448000 0.084000 ;
  END
 END tw_d0[279]
 PIN tw_d0[280]
  DIRECTION INPUT ;
  USE SIGNAL ;
  PORT
   LAYER M5 ;
   RECT 137.616000 0.000000 137.640000 0.084000 ;
  END
 END tw_d0[280]
 PIN tw_d0[281]
  DIRECTION INPUT ;
  USE SIGNAL ;
  PORT
   LAYER M5 ;
   RECT 137.808000 0.000000 137.832000 0.084000 ;
  END
 END tw_d0[281]
 PIN tw_d0[282]
  DIRECTION INPUT ;
  USE SIGNAL ;
  PORT
   LAYER M5 ;
   RECT 138.000000 0.000000 138.024000 0.084000 ;
  END
 END tw_d0[282]
 PIN tw_d0[283]
  DIRECTION INPUT ;
  USE SIGNAL ;
  PORT
   LAYER M5 ;
   RECT 138.192000 0.000000 138.216000 0.084000 ;
  END
 END tw_d0[283]
 PIN tw_d0[284]
  DIRECTION INPUT ;
  USE SIGNAL ;
  PORT
   LAYER M5 ;
   RECT 138.384000 0.000000 138.408000 0.084000 ;
  END
 END tw_d0[284]
 PIN tw_d0[285]
  DIRECTION INPUT ;
  USE SIGNAL ;
  PORT
   LAYER M5 ;
   RECT 138.576000 0.000000 138.600000 0.084000 ;
  END
 END tw_d0[285]
 PIN tw_d0[286]
  DIRECTION INPUT ;
  USE SIGNAL ;
  PORT
   LAYER M5 ;
   RECT 138.768000 0.000000 138.792000 0.084000 ;
  END
 END tw_d0[286]
 PIN tw_d0[287]
  DIRECTION INPUT ;
  USE SIGNAL ;
  PORT
   LAYER M5 ;
   RECT 138.960000 0.000000 138.984000 0.084000 ;
  END
 END tw_d0[287]
 PIN tw_d0[288]
  DIRECTION INPUT ;
  USE SIGNAL ;
  PORT
   LAYER M5 ;
   RECT 139.152000 0.000000 139.176000 0.084000 ;
  END
 END tw_d0[288]
 PIN tw_d0[289]
  DIRECTION INPUT ;
  USE SIGNAL ;
  PORT
   LAYER M5 ;
   RECT 139.344000 0.000000 139.368000 0.084000 ;
  END
 END tw_d0[289]
 PIN tw_d0[290]
  DIRECTION INPUT ;
  USE SIGNAL ;
  PORT
   LAYER M5 ;
   RECT 139.536000 0.000000 139.560000 0.084000 ;
  END
 END tw_d0[290]
 PIN tw_d0[291]
  DIRECTION INPUT ;
  USE SIGNAL ;
  PORT
   LAYER M5 ;
   RECT 139.728000 0.000000 139.752000 0.084000 ;
  END
 END tw_d0[291]
 PIN tw_d0[292]
  DIRECTION INPUT ;
  USE SIGNAL ;
  PORT
   LAYER M5 ;
   RECT 139.920000 0.000000 139.944000 0.084000 ;
  END
 END tw_d0[292]
 PIN tw_d0[293]
  DIRECTION INPUT ;
  USE SIGNAL ;
  PORT
   LAYER M5 ;
   RECT 140.112000 0.000000 140.136000 0.084000 ;
  END
 END tw_d0[293]
 PIN tw_d0[294]
  DIRECTION INPUT ;
  USE SIGNAL ;
  PORT
   LAYER M5 ;
   RECT 140.592000 0.000000 140.616000 0.084000 ;
  END
 END tw_d0[294]
 PIN tw_d0[295]
  DIRECTION INPUT ;
  USE SIGNAL ;
  PORT
   LAYER M5 ;
   RECT 140.784000 0.000000 140.808000 0.084000 ;
  END
 END tw_d0[295]
 PIN tw_d0[296]
  DIRECTION INPUT ;
  USE SIGNAL ;
  PORT
   LAYER M5 ;
   RECT 140.976000 0.000000 141.000000 0.084000 ;
  END
 END tw_d0[296]
 PIN tw_d0[297]
  DIRECTION INPUT ;
  USE SIGNAL ;
  PORT
   LAYER M5 ;
   RECT 141.168000 0.000000 141.192000 0.084000 ;
  END
 END tw_d0[297]
 PIN tw_d0[298]
  DIRECTION INPUT ;
  USE SIGNAL ;
  PORT
   LAYER M5 ;
   RECT 141.360000 0.000000 141.384000 0.084000 ;
  END
 END tw_d0[298]
 PIN tw_d0[299]
  DIRECTION INPUT ;
  USE SIGNAL ;
  PORT
   LAYER M5 ;
   RECT 141.552000 0.000000 141.576000 0.084000 ;
  END
 END tw_d0[299]
 PIN tw_d0[300]
  DIRECTION INPUT ;
  USE SIGNAL ;
  PORT
   LAYER M5 ;
   RECT 141.744000 0.000000 141.768000 0.084000 ;
  END
 END tw_d0[300]
 PIN tw_d0[301]
  DIRECTION INPUT ;
  USE SIGNAL ;
  PORT
   LAYER M5 ;
   RECT 141.936000 0.000000 141.960000 0.084000 ;
  END
 END tw_d0[301]
 PIN tw_d0[302]
  DIRECTION INPUT ;
  USE SIGNAL ;
  PORT
   LAYER M5 ;
   RECT 142.128000 0.000000 142.152000 0.084000 ;
  END
 END tw_d0[302]
 PIN tw_d0[303]
  DIRECTION INPUT ;
  USE SIGNAL ;
  PORT
   LAYER M5 ;
   RECT 142.320000 0.000000 142.344000 0.084000 ;
  END
 END tw_d0[303]
 PIN tw_d0[304]
  DIRECTION INPUT ;
  USE SIGNAL ;
  PORT
   LAYER M5 ;
   RECT 142.512000 0.000000 142.536000 0.084000 ;
  END
 END tw_d0[304]
 PIN tw_d0[305]
  DIRECTION INPUT ;
  USE SIGNAL ;
  PORT
   LAYER M5 ;
   RECT 142.704000 0.000000 142.728000 0.084000 ;
  END
 END tw_d0[305]
 PIN tw_d0[306]
  DIRECTION INPUT ;
  USE SIGNAL ;
  PORT
   LAYER M5 ;
   RECT 142.896000 0.000000 142.920000 0.084000 ;
  END
 END tw_d0[306]
 PIN tw_d0[307]
  DIRECTION INPUT ;
  USE SIGNAL ;
  PORT
   LAYER M5 ;
   RECT 143.088000 0.000000 143.112000 0.084000 ;
  END
 END tw_d0[307]
 PIN tw_d0[308]
  DIRECTION INPUT ;
  USE SIGNAL ;
  PORT
   LAYER M5 ;
   RECT 143.280000 0.000000 143.304000 0.084000 ;
  END
 END tw_d0[308]
 PIN tw_d0[309]
  DIRECTION INPUT ;
  USE SIGNAL ;
  PORT
   LAYER M5 ;
   RECT 143.472000 0.000000 143.496000 0.084000 ;
  END
 END tw_d0[309]
 PIN tw_d0[310]
  DIRECTION INPUT ;
  USE SIGNAL ;
  PORT
   LAYER M5 ;
   RECT 143.664000 0.000000 143.688000 0.084000 ;
  END
 END tw_d0[310]
 PIN tw_d0[311]
  DIRECTION INPUT ;
  USE SIGNAL ;
  PORT
   LAYER M5 ;
   RECT 143.856000 0.000000 143.880000 0.084000 ;
  END
 END tw_d0[311]
 PIN tw_d0[312]
  DIRECTION INPUT ;
  USE SIGNAL ;
  PORT
   LAYER M5 ;
   RECT 144.048000 0.000000 144.072000 0.084000 ;
  END
 END tw_d0[312]
 PIN tw_d0[313]
  DIRECTION INPUT ;
  USE SIGNAL ;
  PORT
   LAYER M5 ;
   RECT 144.240000 0.000000 144.264000 0.084000 ;
  END
 END tw_d0[313]
 PIN tw_d0[314]
  DIRECTION INPUT ;
  USE SIGNAL ;
  PORT
   LAYER M5 ;
   RECT 144.432000 0.000000 144.456000 0.084000 ;
  END
 END tw_d0[314]
 PIN tw_d0[315]
  DIRECTION INPUT ;
  USE SIGNAL ;
  PORT
   LAYER M5 ;
   RECT 144.912000 0.000000 144.936000 0.084000 ;
  END
 END tw_d0[315]
 PIN tw_d0[316]
  DIRECTION INPUT ;
  USE SIGNAL ;
  PORT
   LAYER M5 ;
   RECT 145.104000 0.000000 145.128000 0.084000 ;
  END
 END tw_d0[316]
 PIN tw_d0[317]
  DIRECTION INPUT ;
  USE SIGNAL ;
  PORT
   LAYER M5 ;
   RECT 145.296000 0.000000 145.320000 0.084000 ;
  END
 END tw_d0[317]
 PIN tw_d0[318]
  DIRECTION INPUT ;
  USE SIGNAL ;
  PORT
   LAYER M5 ;
   RECT 145.488000 0.000000 145.512000 0.084000 ;
  END
 END tw_d0[318]
 PIN tw_d0[319]
  DIRECTION INPUT ;
  USE SIGNAL ;
  PORT
   LAYER M5 ;
   RECT 145.680000 0.000000 145.704000 0.084000 ;
  END
 END tw_d0[319]
 PIN tw_d0[320]
  DIRECTION INPUT ;
  USE SIGNAL ;
  PORT
   LAYER M5 ;
   RECT 145.872000 0.000000 145.896000 0.084000 ;
  END
 END tw_d0[320]
 PIN tw_d0[321]
  DIRECTION INPUT ;
  USE SIGNAL ;
  PORT
   LAYER M5 ;
   RECT 146.064000 0.000000 146.088000 0.084000 ;
  END
 END tw_d0[321]
 PIN tw_d0[322]
  DIRECTION INPUT ;
  USE SIGNAL ;
  PORT
   LAYER M5 ;
   RECT 146.256000 0.000000 146.280000 0.084000 ;
  END
 END tw_d0[322]
 PIN tw_d0[323]
  DIRECTION INPUT ;
  USE SIGNAL ;
  PORT
   LAYER M5 ;
   RECT 146.448000 0.000000 146.472000 0.084000 ;
  END
 END tw_d0[323]
 PIN tw_d0[324]
  DIRECTION INPUT ;
  USE SIGNAL ;
  PORT
   LAYER M5 ;
   RECT 146.640000 0.000000 146.664000 0.084000 ;
  END
 END tw_d0[324]
 PIN tw_d0[325]
  DIRECTION INPUT ;
  USE SIGNAL ;
  PORT
   LAYER M5 ;
   RECT 146.832000 0.000000 146.856000 0.084000 ;
  END
 END tw_d0[325]
 PIN tw_d0[326]
  DIRECTION INPUT ;
  USE SIGNAL ;
  PORT
   LAYER M5 ;
   RECT 147.024000 0.000000 147.048000 0.084000 ;
  END
 END tw_d0[326]
 PIN tw_d0[327]
  DIRECTION INPUT ;
  USE SIGNAL ;
  PORT
   LAYER M5 ;
   RECT 147.216000 0.000000 147.240000 0.084000 ;
  END
 END tw_d0[327]
 PIN tw_d0[328]
  DIRECTION INPUT ;
  USE SIGNAL ;
  PORT
   LAYER M5 ;
   RECT 147.408000 0.000000 147.432000 0.084000 ;
  END
 END tw_d0[328]
 PIN tw_d0[329]
  DIRECTION INPUT ;
  USE SIGNAL ;
  PORT
   LAYER M5 ;
   RECT 147.600000 0.000000 147.624000 0.084000 ;
  END
 END tw_d0[329]
 PIN tw_d0[330]
  DIRECTION INPUT ;
  USE SIGNAL ;
  PORT
   LAYER M5 ;
   RECT 147.792000 0.000000 147.816000 0.084000 ;
  END
 END tw_d0[330]
 PIN tw_d0[331]
  DIRECTION INPUT ;
  USE SIGNAL ;
  PORT
   LAYER M5 ;
   RECT 147.984000 0.000000 148.008000 0.084000 ;
  END
 END tw_d0[331]
 PIN tw_d0[332]
  DIRECTION INPUT ;
  USE SIGNAL ;
  PORT
   LAYER M5 ;
   RECT 148.176000 0.000000 148.200000 0.084000 ;
  END
 END tw_d0[332]
 PIN tw_d0[333]
  DIRECTION INPUT ;
  USE SIGNAL ;
  PORT
   LAYER M5 ;
   RECT 148.368000 0.000000 148.392000 0.084000 ;
  END
 END tw_d0[333]
 PIN tw_d0[334]
  DIRECTION INPUT ;
  USE SIGNAL ;
  PORT
   LAYER M5 ;
   RECT 148.560000 0.000000 148.584000 0.084000 ;
  END
 END tw_d0[334]
 PIN tw_d0[335]
  DIRECTION INPUT ;
  USE SIGNAL ;
  PORT
   LAYER M5 ;
   RECT 148.752000 0.000000 148.776000 0.084000 ;
  END
 END tw_d0[335]
 PIN tw_d0[336]
  DIRECTION INPUT ;
  USE SIGNAL ;
  PORT
   LAYER M5 ;
   RECT 149.232000 0.000000 149.256000 0.084000 ;
  END
 END tw_d0[336]
 PIN tw_d0[337]
  DIRECTION INPUT ;
  USE SIGNAL ;
  PORT
   LAYER M5 ;
   RECT 149.424000 0.000000 149.448000 0.084000 ;
  END
 END tw_d0[337]
 PIN tw_d0[338]
  DIRECTION INPUT ;
  USE SIGNAL ;
  PORT
   LAYER M5 ;
   RECT 149.616000 0.000000 149.640000 0.084000 ;
  END
 END tw_d0[338]
 PIN tw_d0[339]
  DIRECTION INPUT ;
  USE SIGNAL ;
  PORT
   LAYER M5 ;
   RECT 149.808000 0.000000 149.832000 0.084000 ;
  END
 END tw_d0[339]
 PIN tw_d0[340]
  DIRECTION INPUT ;
  USE SIGNAL ;
  PORT
   LAYER M5 ;
   RECT 150.000000 0.000000 150.024000 0.084000 ;
  END
 END tw_d0[340]
 PIN tw_d0[341]
  DIRECTION INPUT ;
  USE SIGNAL ;
  PORT
   LAYER M5 ;
   RECT 150.192000 0.000000 150.216000 0.084000 ;
  END
 END tw_d0[341]
 PIN tw_d0[342]
  DIRECTION INPUT ;
  USE SIGNAL ;
  PORT
   LAYER M5 ;
   RECT 150.384000 0.000000 150.408000 0.084000 ;
  END
 END tw_d0[342]
 PIN tw_d0[343]
  DIRECTION INPUT ;
  USE SIGNAL ;
  PORT
   LAYER M5 ;
   RECT 150.576000 0.000000 150.600000 0.084000 ;
  END
 END tw_d0[343]
 PIN tw_d0[344]
  DIRECTION INPUT ;
  USE SIGNAL ;
  PORT
   LAYER M5 ;
   RECT 150.768000 0.000000 150.792000 0.084000 ;
  END
 END tw_d0[344]
 PIN tw_d0[345]
  DIRECTION INPUT ;
  USE SIGNAL ;
  PORT
   LAYER M5 ;
   RECT 150.960000 0.000000 150.984000 0.084000 ;
  END
 END tw_d0[345]
 PIN tw_d0[346]
  DIRECTION INPUT ;
  USE SIGNAL ;
  PORT
   LAYER M5 ;
   RECT 151.152000 0.000000 151.176000 0.084000 ;
  END
 END tw_d0[346]
 PIN tw_d0[347]
  DIRECTION INPUT ;
  USE SIGNAL ;
  PORT
   LAYER M5 ;
   RECT 151.344000 0.000000 151.368000 0.084000 ;
  END
 END tw_d0[347]
 PIN tw_d0[348]
  DIRECTION INPUT ;
  USE SIGNAL ;
  PORT
   LAYER M5 ;
   RECT 151.536000 0.000000 151.560000 0.084000 ;
  END
 END tw_d0[348]
 PIN tw_d0[349]
  DIRECTION INPUT ;
  USE SIGNAL ;
  PORT
   LAYER M5 ;
   RECT 151.728000 0.000000 151.752000 0.084000 ;
  END
 END tw_d0[349]
 PIN tw_d0[350]
  DIRECTION INPUT ;
  USE SIGNAL ;
  PORT
   LAYER M5 ;
   RECT 151.920000 0.000000 151.944000 0.084000 ;
  END
 END tw_d0[350]
 PIN tw_d0[351]
  DIRECTION INPUT ;
  USE SIGNAL ;
  PORT
   LAYER M5 ;
   RECT 152.112000 0.000000 152.136000 0.084000 ;
  END
 END tw_d0[351]
 PIN tw_d0[352]
  DIRECTION INPUT ;
  USE SIGNAL ;
  PORT
   LAYER M5 ;
   RECT 152.304000 0.000000 152.328000 0.084000 ;
  END
 END tw_d0[352]
 PIN tw_d0[353]
  DIRECTION INPUT ;
  USE SIGNAL ;
  PORT
   LAYER M5 ;
   RECT 152.496000 0.000000 152.520000 0.084000 ;
  END
 END tw_d0[353]
 PIN tw_d0[354]
  DIRECTION INPUT ;
  USE SIGNAL ;
  PORT
   LAYER M5 ;
   RECT 152.688000 0.000000 152.712000 0.084000 ;
  END
 END tw_d0[354]
 PIN tw_d0[355]
  DIRECTION INPUT ;
  USE SIGNAL ;
  PORT
   LAYER M5 ;
   RECT 152.880000 0.000000 152.904000 0.084000 ;
  END
 END tw_d0[355]
 PIN tw_d0[356]
  DIRECTION INPUT ;
  USE SIGNAL ;
  PORT
   LAYER M5 ;
   RECT 153.072000 0.000000 153.096000 0.084000 ;
  END
 END tw_d0[356]
 PIN tw_d0[357]
  DIRECTION INPUT ;
  USE SIGNAL ;
  PORT
   LAYER M5 ;
   RECT 153.552000 0.000000 153.576000 0.084000 ;
  END
 END tw_d0[357]
 PIN tw_d0[358]
  DIRECTION INPUT ;
  USE SIGNAL ;
  PORT
   LAYER M5 ;
   RECT 153.744000 0.000000 153.768000 0.084000 ;
  END
 END tw_d0[358]
 PIN tw_d0[359]
  DIRECTION INPUT ;
  USE SIGNAL ;
  PORT
   LAYER M5 ;
   RECT 153.936000 0.000000 153.960000 0.084000 ;
  END
 END tw_d0[359]
 PIN tw_d0[360]
  DIRECTION INPUT ;
  USE SIGNAL ;
  PORT
   LAYER M5 ;
   RECT 154.128000 0.000000 154.152000 0.084000 ;
  END
 END tw_d0[360]
 PIN tw_d0[361]
  DIRECTION INPUT ;
  USE SIGNAL ;
  PORT
   LAYER M5 ;
   RECT 154.320000 0.000000 154.344000 0.084000 ;
  END
 END tw_d0[361]
 PIN tw_d0[362]
  DIRECTION INPUT ;
  USE SIGNAL ;
  PORT
   LAYER M5 ;
   RECT 154.512000 0.000000 154.536000 0.084000 ;
  END
 END tw_d0[362]
 PIN tw_d0[363]
  DIRECTION INPUT ;
  USE SIGNAL ;
  PORT
   LAYER M5 ;
   RECT 154.704000 0.000000 154.728000 0.084000 ;
  END
 END tw_d0[363]
 PIN tw_d0[364]
  DIRECTION INPUT ;
  USE SIGNAL ;
  PORT
   LAYER M5 ;
   RECT 154.896000 0.000000 154.920000 0.084000 ;
  END
 END tw_d0[364]
 PIN tw_d0[365]
  DIRECTION INPUT ;
  USE SIGNAL ;
  PORT
   LAYER M5 ;
   RECT 155.088000 0.000000 155.112000 0.084000 ;
  END
 END tw_d0[365]
 PIN tw_d0[366]
  DIRECTION INPUT ;
  USE SIGNAL ;
  PORT
   LAYER M5 ;
   RECT 155.280000 0.000000 155.304000 0.084000 ;
  END
 END tw_d0[366]
 PIN tw_d0[367]
  DIRECTION INPUT ;
  USE SIGNAL ;
  PORT
   LAYER M5 ;
   RECT 155.472000 0.000000 155.496000 0.084000 ;
  END
 END tw_d0[367]
 PIN tw_d0[368]
  DIRECTION INPUT ;
  USE SIGNAL ;
  PORT
   LAYER M5 ;
   RECT 155.664000 0.000000 155.688000 0.084000 ;
  END
 END tw_d0[368]
 PIN tw_d0[369]
  DIRECTION INPUT ;
  USE SIGNAL ;
  PORT
   LAYER M5 ;
   RECT 155.856000 0.000000 155.880000 0.084000 ;
  END
 END tw_d0[369]
 PIN tw_d0[370]
  DIRECTION INPUT ;
  USE SIGNAL ;
  PORT
   LAYER M5 ;
   RECT 156.048000 0.000000 156.072000 0.084000 ;
  END
 END tw_d0[370]
 PIN tw_d0[371]
  DIRECTION INPUT ;
  USE SIGNAL ;
  PORT
   LAYER M5 ;
   RECT 156.240000 0.000000 156.264000 0.084000 ;
  END
 END tw_d0[371]
 PIN tw_d0[372]
  DIRECTION INPUT ;
  USE SIGNAL ;
  PORT
   LAYER M5 ;
   RECT 156.432000 0.000000 156.456000 0.084000 ;
  END
 END tw_d0[372]
 PIN tw_d0[373]
  DIRECTION INPUT ;
  USE SIGNAL ;
  PORT
   LAYER M5 ;
   RECT 156.624000 0.000000 156.648000 0.084000 ;
  END
 END tw_d0[373]
 PIN tw_d0[374]
  DIRECTION INPUT ;
  USE SIGNAL ;
  PORT
   LAYER M5 ;
   RECT 156.816000 0.000000 156.840000 0.084000 ;
  END
 END tw_d0[374]
 PIN tw_d0[375]
  DIRECTION INPUT ;
  USE SIGNAL ;
  PORT
   LAYER M5 ;
   RECT 157.008000 0.000000 157.032000 0.084000 ;
  END
 END tw_d0[375]
 PIN tw_d0[376]
  DIRECTION INPUT ;
  USE SIGNAL ;
  PORT
   LAYER M5 ;
   RECT 157.200000 0.000000 157.224000 0.084000 ;
  END
 END tw_d0[376]
 PIN tw_d0[377]
  DIRECTION INPUT ;
  USE SIGNAL ;
  PORT
   LAYER M5 ;
   RECT 157.392000 0.000000 157.416000 0.084000 ;
  END
 END tw_d0[377]
 PIN tw_d0[378]
  DIRECTION INPUT ;
  USE SIGNAL ;
  PORT
   LAYER M5 ;
   RECT 157.872000 0.000000 157.896000 0.084000 ;
  END
 END tw_d0[378]
 PIN tw_d0[379]
  DIRECTION INPUT ;
  USE SIGNAL ;
  PORT
   LAYER M5 ;
   RECT 158.064000 0.000000 158.088000 0.084000 ;
  END
 END tw_d0[379]
 PIN tw_d0[380]
  DIRECTION INPUT ;
  USE SIGNAL ;
  PORT
   LAYER M5 ;
   RECT 158.256000 0.000000 158.280000 0.084000 ;
  END
 END tw_d0[380]
 PIN tw_d0[381]
  DIRECTION INPUT ;
  USE SIGNAL ;
  PORT
   LAYER M5 ;
   RECT 158.448000 0.000000 158.472000 0.084000 ;
  END
 END tw_d0[381]
 PIN tw_d0[382]
  DIRECTION INPUT ;
  USE SIGNAL ;
  PORT
   LAYER M5 ;
   RECT 158.640000 0.000000 158.664000 0.084000 ;
  END
 END tw_d0[382]
 PIN tw_d0[383]
  DIRECTION INPUT ;
  USE SIGNAL ;
  PORT
   LAYER M5 ;
   RECT 158.832000 0.000000 158.856000 0.084000 ;
  END
 END tw_d0[383]
 PIN tw_d0[384]
  DIRECTION INPUT ;
  USE SIGNAL ;
  PORT
   LAYER M5 ;
   RECT 159.024000 0.000000 159.048000 0.084000 ;
  END
 END tw_d0[384]
 PIN tw_d0[385]
  DIRECTION INPUT ;
  USE SIGNAL ;
  PORT
   LAYER M5 ;
   RECT 159.216000 0.000000 159.240000 0.084000 ;
  END
 END tw_d0[385]
 PIN tw_d0[386]
  DIRECTION INPUT ;
  USE SIGNAL ;
  PORT
   LAYER M5 ;
   RECT 159.408000 0.000000 159.432000 0.084000 ;
  END
 END tw_d0[386]
 PIN tw_d0[387]
  DIRECTION INPUT ;
  USE SIGNAL ;
  PORT
   LAYER M5 ;
   RECT 159.600000 0.000000 159.624000 0.084000 ;
  END
 END tw_d0[387]
 PIN tw_d0[388]
  DIRECTION INPUT ;
  USE SIGNAL ;
  PORT
   LAYER M5 ;
   RECT 159.792000 0.000000 159.816000 0.084000 ;
  END
 END tw_d0[388]
 PIN tw_d0[389]
  DIRECTION INPUT ;
  USE SIGNAL ;
  PORT
   LAYER M5 ;
   RECT 159.984000 0.000000 160.008000 0.084000 ;
  END
 END tw_d0[389]
 PIN tw_d0[390]
  DIRECTION INPUT ;
  USE SIGNAL ;
  PORT
   LAYER M5 ;
   RECT 160.176000 0.000000 160.200000 0.084000 ;
  END
 END tw_d0[390]
 PIN tw_d0[391]
  DIRECTION INPUT ;
  USE SIGNAL ;
  PORT
   LAYER M5 ;
   RECT 160.368000 0.000000 160.392000 0.084000 ;
  END
 END tw_d0[391]
 PIN tw_d0[392]
  DIRECTION INPUT ;
  USE SIGNAL ;
  PORT
   LAYER M5 ;
   RECT 160.560000 0.000000 160.584000 0.084000 ;
  END
 END tw_d0[392]
 PIN tw_d0[393]
  DIRECTION INPUT ;
  USE SIGNAL ;
  PORT
   LAYER M5 ;
   RECT 160.752000 0.000000 160.776000 0.084000 ;
  END
 END tw_d0[393]
 PIN tw_d0[394]
  DIRECTION INPUT ;
  USE SIGNAL ;
  PORT
   LAYER M5 ;
   RECT 160.944000 0.000000 160.968000 0.084000 ;
  END
 END tw_d0[394]
 PIN tw_d0[395]
  DIRECTION INPUT ;
  USE SIGNAL ;
  PORT
   LAYER M5 ;
   RECT 161.136000 0.000000 161.160000 0.084000 ;
  END
 END tw_d0[395]
 PIN tw_d0[396]
  DIRECTION INPUT ;
  USE SIGNAL ;
  PORT
   LAYER M5 ;
   RECT 161.328000 0.000000 161.352000 0.084000 ;
  END
 END tw_d0[396]
 PIN tw_d0[397]
  DIRECTION INPUT ;
  USE SIGNAL ;
  PORT
   LAYER M5 ;
   RECT 161.520000 0.000000 161.544000 0.084000 ;
  END
 END tw_d0[397]
 PIN tw_d0[398]
  DIRECTION INPUT ;
  USE SIGNAL ;
  PORT
   LAYER M5 ;
   RECT 161.712000 0.000000 161.736000 0.084000 ;
  END
 END tw_d0[398]
 PIN tw_d0[399]
  DIRECTION INPUT ;
  USE SIGNAL ;
  PORT
   LAYER M5 ;
   RECT 162.192000 0.000000 162.216000 0.084000 ;
  END
 END tw_d0[399]
 PIN tw_d0[400]
  DIRECTION INPUT ;
  USE SIGNAL ;
  PORT
   LAYER M5 ;
   RECT 162.384000 0.000000 162.408000 0.084000 ;
  END
 END tw_d0[400]
 PIN tw_d0[401]
  DIRECTION INPUT ;
  USE SIGNAL ;
  PORT
   LAYER M5 ;
   RECT 162.576000 0.000000 162.600000 0.084000 ;
  END
 END tw_d0[401]
 PIN tw_d0[402]
  DIRECTION INPUT ;
  USE SIGNAL ;
  PORT
   LAYER M5 ;
   RECT 162.768000 0.000000 162.792000 0.084000 ;
  END
 END tw_d0[402]
 PIN tw_d0[403]
  DIRECTION INPUT ;
  USE SIGNAL ;
  PORT
   LAYER M5 ;
   RECT 162.960000 0.000000 162.984000 0.084000 ;
  END
 END tw_d0[403]
 PIN tw_d0[404]
  DIRECTION INPUT ;
  USE SIGNAL ;
  PORT
   LAYER M5 ;
   RECT 163.152000 0.000000 163.176000 0.084000 ;
  END
 END tw_d0[404]
 PIN tw_d0[405]
  DIRECTION INPUT ;
  USE SIGNAL ;
  PORT
   LAYER M5 ;
   RECT 163.344000 0.000000 163.368000 0.084000 ;
  END
 END tw_d0[405]
 PIN tw_d0[406]
  DIRECTION INPUT ;
  USE SIGNAL ;
  PORT
   LAYER M5 ;
   RECT 163.536000 0.000000 163.560000 0.084000 ;
  END
 END tw_d0[406]
 PIN tw_d0[407]
  DIRECTION INPUT ;
  USE SIGNAL ;
  PORT
   LAYER M5 ;
   RECT 163.728000 0.000000 163.752000 0.084000 ;
  END
 END tw_d0[407]
 PIN tw_d0[408]
  DIRECTION INPUT ;
  USE SIGNAL ;
  PORT
   LAYER M5 ;
   RECT 163.920000 0.000000 163.944000 0.084000 ;
  END
 END tw_d0[408]
 PIN tw_d0[409]
  DIRECTION INPUT ;
  USE SIGNAL ;
  PORT
   LAYER M5 ;
   RECT 164.112000 0.000000 164.136000 0.084000 ;
  END
 END tw_d0[409]
 PIN tw_d0[410]
  DIRECTION INPUT ;
  USE SIGNAL ;
  PORT
   LAYER M5 ;
   RECT 164.304000 0.000000 164.328000 0.084000 ;
  END
 END tw_d0[410]
 PIN tw_d0[411]
  DIRECTION INPUT ;
  USE SIGNAL ;
  PORT
   LAYER M5 ;
   RECT 164.496000 0.000000 164.520000 0.084000 ;
  END
 END tw_d0[411]
 PIN tw_d0[412]
  DIRECTION INPUT ;
  USE SIGNAL ;
  PORT
   LAYER M5 ;
   RECT 164.688000 0.000000 164.712000 0.084000 ;
  END
 END tw_d0[412]
 PIN tw_d0[413]
  DIRECTION INPUT ;
  USE SIGNAL ;
  PORT
   LAYER M5 ;
   RECT 164.880000 0.000000 164.904000 0.084000 ;
  END
 END tw_d0[413]
 PIN tw_d0[414]
  DIRECTION INPUT ;
  USE SIGNAL ;
  PORT
   LAYER M5 ;
   RECT 165.072000 0.000000 165.096000 0.084000 ;
  END
 END tw_d0[414]
 PIN tw_d0[415]
  DIRECTION INPUT ;
  USE SIGNAL ;
  PORT
   LAYER M5 ;
   RECT 165.264000 0.000000 165.288000 0.084000 ;
  END
 END tw_d0[415]
 PIN tw_d0[416]
  DIRECTION INPUT ;
  USE SIGNAL ;
  PORT
   LAYER M5 ;
   RECT 165.456000 0.000000 165.480000 0.084000 ;
  END
 END tw_d0[416]
 PIN tw_d0[417]
  DIRECTION INPUT ;
  USE SIGNAL ;
  PORT
   LAYER M5 ;
   RECT 165.648000 0.000000 165.672000 0.084000 ;
  END
 END tw_d0[417]
 PIN tw_d0[418]
  DIRECTION INPUT ;
  USE SIGNAL ;
  PORT
   LAYER M5 ;
   RECT 165.840000 0.000000 165.864000 0.084000 ;
  END
 END tw_d0[418]
 PIN tw_d0[419]
  DIRECTION INPUT ;
  USE SIGNAL ;
  PORT
   LAYER M5 ;
   RECT 166.032000 0.000000 166.056000 0.084000 ;
  END
 END tw_d0[419]
 PIN tw_d0[420]
  DIRECTION INPUT ;
  USE SIGNAL ;
  PORT
   LAYER M5 ;
   RECT 166.512000 0.000000 166.536000 0.084000 ;
  END
 END tw_d0[420]
 PIN tw_d0[421]
  DIRECTION INPUT ;
  USE SIGNAL ;
  PORT
   LAYER M5 ;
   RECT 166.704000 0.000000 166.728000 0.084000 ;
  END
 END tw_d0[421]
 PIN tw_d0[422]
  DIRECTION INPUT ;
  USE SIGNAL ;
  PORT
   LAYER M5 ;
   RECT 166.896000 0.000000 166.920000 0.084000 ;
  END
 END tw_d0[422]
 PIN tw_d0[423]
  DIRECTION INPUT ;
  USE SIGNAL ;
  PORT
   LAYER M5 ;
   RECT 167.088000 0.000000 167.112000 0.084000 ;
  END
 END tw_d0[423]
 PIN tw_d0[424]
  DIRECTION INPUT ;
  USE SIGNAL ;
  PORT
   LAYER M5 ;
   RECT 167.280000 0.000000 167.304000 0.084000 ;
  END
 END tw_d0[424]
 PIN tw_d0[425]
  DIRECTION INPUT ;
  USE SIGNAL ;
  PORT
   LAYER M5 ;
   RECT 167.472000 0.000000 167.496000 0.084000 ;
  END
 END tw_d0[425]
 PIN tw_d0[426]
  DIRECTION INPUT ;
  USE SIGNAL ;
  PORT
   LAYER M5 ;
   RECT 167.664000 0.000000 167.688000 0.084000 ;
  END
 END tw_d0[426]
 PIN tw_d0[427]
  DIRECTION INPUT ;
  USE SIGNAL ;
  PORT
   LAYER M5 ;
   RECT 167.856000 0.000000 167.880000 0.084000 ;
  END
 END tw_d0[427]
 PIN tw_d0[428]
  DIRECTION INPUT ;
  USE SIGNAL ;
  PORT
   LAYER M5 ;
   RECT 168.048000 0.000000 168.072000 0.084000 ;
  END
 END tw_d0[428]
 PIN tw_d0[429]
  DIRECTION INPUT ;
  USE SIGNAL ;
  PORT
   LAYER M5 ;
   RECT 168.240000 0.000000 168.264000 0.084000 ;
  END
 END tw_d0[429]
 PIN tw_d0[430]
  DIRECTION INPUT ;
  USE SIGNAL ;
  PORT
   LAYER M5 ;
   RECT 168.432000 0.000000 168.456000 0.084000 ;
  END
 END tw_d0[430]
 PIN tw_d0[431]
  DIRECTION INPUT ;
  USE SIGNAL ;
  PORT
   LAYER M5 ;
   RECT 168.624000 0.000000 168.648000 0.084000 ;
  END
 END tw_d0[431]
 PIN tw_d0[432]
  DIRECTION INPUT ;
  USE SIGNAL ;
  PORT
   LAYER M5 ;
   RECT 168.816000 0.000000 168.840000 0.084000 ;
  END
 END tw_d0[432]
 PIN tw_d0[433]
  DIRECTION INPUT ;
  USE SIGNAL ;
  PORT
   LAYER M5 ;
   RECT 169.008000 0.000000 169.032000 0.084000 ;
  END
 END tw_d0[433]
 PIN tw_d0[434]
  DIRECTION INPUT ;
  USE SIGNAL ;
  PORT
   LAYER M5 ;
   RECT 169.200000 0.000000 169.224000 0.084000 ;
  END
 END tw_d0[434]
 PIN tw_d0[435]
  DIRECTION INPUT ;
  USE SIGNAL ;
  PORT
   LAYER M5 ;
   RECT 169.392000 0.000000 169.416000 0.084000 ;
  END
 END tw_d0[435]
 PIN tw_d0[436]
  DIRECTION INPUT ;
  USE SIGNAL ;
  PORT
   LAYER M5 ;
   RECT 169.584000 0.000000 169.608000 0.084000 ;
  END
 END tw_d0[436]
 PIN tw_d0[437]
  DIRECTION INPUT ;
  USE SIGNAL ;
  PORT
   LAYER M5 ;
   RECT 169.776000 0.000000 169.800000 0.084000 ;
  END
 END tw_d0[437]
 PIN tw_d0[438]
  DIRECTION INPUT ;
  USE SIGNAL ;
  PORT
   LAYER M5 ;
   RECT 169.968000 0.000000 169.992000 0.084000 ;
  END
 END tw_d0[438]
 PIN tw_d0[439]
  DIRECTION INPUT ;
  USE SIGNAL ;
  PORT
   LAYER M5 ;
   RECT 170.160000 0.000000 170.184000 0.084000 ;
  END
 END tw_d0[439]
 PIN tw_d0[440]
  DIRECTION INPUT ;
  USE SIGNAL ;
  PORT
   LAYER M5 ;
   RECT 170.352000 0.000000 170.376000 0.084000 ;
  END
 END tw_d0[440]
 PIN tw_d0[441]
  DIRECTION INPUT ;
  USE SIGNAL ;
  PORT
   LAYER M5 ;
   RECT 170.832000 0.000000 170.856000 0.084000 ;
  END
 END tw_d0[441]
 PIN tw_d0[442]
  DIRECTION INPUT ;
  USE SIGNAL ;
  PORT
   LAYER M5 ;
   RECT 171.024000 0.000000 171.048000 0.084000 ;
  END
 END tw_d0[442]
 PIN tw_d0[443]
  DIRECTION INPUT ;
  USE SIGNAL ;
  PORT
   LAYER M5 ;
   RECT 171.216000 0.000000 171.240000 0.084000 ;
  END
 END tw_d0[443]
 PIN tw_d0[444]
  DIRECTION INPUT ;
  USE SIGNAL ;
  PORT
   LAYER M5 ;
   RECT 171.408000 0.000000 171.432000 0.084000 ;
  END
 END tw_d0[444]
 PIN tw_d0[445]
  DIRECTION INPUT ;
  USE SIGNAL ;
  PORT
   LAYER M5 ;
   RECT 171.600000 0.000000 171.624000 0.084000 ;
  END
 END tw_d0[445]
 PIN tw_d0[446]
  DIRECTION INPUT ;
  USE SIGNAL ;
  PORT
   LAYER M5 ;
   RECT 171.792000 0.000000 171.816000 0.084000 ;
  END
 END tw_d0[446]
 PIN tw_d0[447]
  DIRECTION INPUT ;
  USE SIGNAL ;
  PORT
   LAYER M5 ;
   RECT 171.984000 0.000000 172.008000 0.084000 ;
  END
 END tw_d0[447]
 PIN tw_d0[448]
  DIRECTION INPUT ;
  USE SIGNAL ;
  PORT
   LAYER M5 ;
   RECT 172.176000 0.000000 172.200000 0.084000 ;
  END
 END tw_d0[448]
 PIN tw_d0[449]
  DIRECTION INPUT ;
  USE SIGNAL ;
  PORT
   LAYER M5 ;
   RECT 172.368000 0.000000 172.392000 0.084000 ;
  END
 END tw_d0[449]
 PIN tw_d0[450]
  DIRECTION INPUT ;
  USE SIGNAL ;
  PORT
   LAYER M5 ;
   RECT 172.560000 0.000000 172.584000 0.084000 ;
  END
 END tw_d0[450]
 PIN tw_d0[451]
  DIRECTION INPUT ;
  USE SIGNAL ;
  PORT
   LAYER M5 ;
   RECT 172.752000 0.000000 172.776000 0.084000 ;
  END
 END tw_d0[451]
 PIN tw_d0[452]
  DIRECTION INPUT ;
  USE SIGNAL ;
  PORT
   LAYER M5 ;
   RECT 172.944000 0.000000 172.968000 0.084000 ;
  END
 END tw_d0[452]
 PIN tw_d0[453]
  DIRECTION INPUT ;
  USE SIGNAL ;
  PORT
   LAYER M5 ;
   RECT 173.136000 0.000000 173.160000 0.084000 ;
  END
 END tw_d0[453]
 PIN tw_d0[454]
  DIRECTION INPUT ;
  USE SIGNAL ;
  PORT
   LAYER M5 ;
   RECT 173.328000 0.000000 173.352000 0.084000 ;
  END
 END tw_d0[454]
 PIN tw_d0[455]
  DIRECTION INPUT ;
  USE SIGNAL ;
  PORT
   LAYER M5 ;
   RECT 173.520000 0.000000 173.544000 0.084000 ;
  END
 END tw_d0[455]
 PIN tw_d0[456]
  DIRECTION INPUT ;
  USE SIGNAL ;
  PORT
   LAYER M5 ;
   RECT 173.712000 0.000000 173.736000 0.084000 ;
  END
 END tw_d0[456]
 PIN tw_d1[0]
  DIRECTION INPUT ;
  USE SIGNAL ;
  PORT
   LAYER M5 ;
   RECT 184.320000 0.000000 184.344000 0.084000 ;
  END
 END tw_d1[0]
 PIN tw_d1[1]
  DIRECTION INPUT ;
  USE SIGNAL ;
  PORT
   LAYER M5 ;
   RECT 184.512000 0.000000 184.536000 0.084000 ;
  END
 END tw_d1[1]
 PIN tw_d1[2]
  DIRECTION INPUT ;
  USE SIGNAL ;
  PORT
   LAYER M5 ;
   RECT 184.704000 0.000000 184.728000 0.084000 ;
  END
 END tw_d1[2]
 PIN tw_d1[3]
  DIRECTION INPUT ;
  USE SIGNAL ;
  PORT
   LAYER M5 ;
   RECT 184.896000 0.000000 184.920000 0.084000 ;
  END
 END tw_d1[3]
 PIN tw_d1[4]
  DIRECTION INPUT ;
  USE SIGNAL ;
  PORT
   LAYER M5 ;
   RECT 185.088000 0.000000 185.112000 0.084000 ;
  END
 END tw_d1[4]
 PIN tw_d1[5]
  DIRECTION INPUT ;
  USE SIGNAL ;
  PORT
   LAYER M5 ;
   RECT 185.280000 0.000000 185.304000 0.084000 ;
  END
 END tw_d1[5]
 PIN tw_d1[6]
  DIRECTION INPUT ;
  USE SIGNAL ;
  PORT
   LAYER M5 ;
   RECT 185.472000 0.000000 185.496000 0.084000 ;
  END
 END tw_d1[6]
 PIN tw_d1[7]
  DIRECTION INPUT ;
  USE SIGNAL ;
  PORT
   LAYER M5 ;
   RECT 185.664000 0.000000 185.688000 0.084000 ;
  END
 END tw_d1[7]
 PIN tw_d1[8]
  DIRECTION INPUT ;
  USE SIGNAL ;
  PORT
   LAYER M5 ;
   RECT 185.856000 0.000000 185.880000 0.084000 ;
  END
 END tw_d1[8]
 PIN tw_d1[9]
  DIRECTION INPUT ;
  USE SIGNAL ;
  PORT
   LAYER M5 ;
   RECT 186.048000 0.000000 186.072000 0.084000 ;
  END
 END tw_d1[9]
 PIN tw_d1[10]
  DIRECTION INPUT ;
  USE SIGNAL ;
  PORT
   LAYER M5 ;
   RECT 186.240000 0.000000 186.264000 0.084000 ;
  END
 END tw_d1[10]
 PIN tw_d1[11]
  DIRECTION INPUT ;
  USE SIGNAL ;
  PORT
   LAYER M5 ;
   RECT 186.432000 0.000000 186.456000 0.084000 ;
  END
 END tw_d1[11]
 PIN tw_d1[12]
  DIRECTION INPUT ;
  USE SIGNAL ;
  PORT
   LAYER M5 ;
   RECT 186.624000 0.000000 186.648000 0.084000 ;
  END
 END tw_d1[12]
 PIN tw_d1[13]
  DIRECTION INPUT ;
  USE SIGNAL ;
  PORT
   LAYER M5 ;
   RECT 186.816000 0.000000 186.840000 0.084000 ;
  END
 END tw_d1[13]
 PIN tw_d1[14]
  DIRECTION INPUT ;
  USE SIGNAL ;
  PORT
   LAYER M5 ;
   RECT 187.008000 0.000000 187.032000 0.084000 ;
  END
 END tw_d1[14]
 PIN tw_d1[15]
  DIRECTION INPUT ;
  USE SIGNAL ;
  PORT
   LAYER M5 ;
   RECT 187.200000 0.000000 187.224000 0.084000 ;
  END
 END tw_d1[15]
 PIN tw_d1[16]
  DIRECTION INPUT ;
  USE SIGNAL ;
  PORT
   LAYER M5 ;
   RECT 187.392000 0.000000 187.416000 0.084000 ;
  END
 END tw_d1[16]
 PIN tw_d1[17]
  DIRECTION INPUT ;
  USE SIGNAL ;
  PORT
   LAYER M5 ;
   RECT 187.584000 0.000000 187.608000 0.084000 ;
  END
 END tw_d1[17]
 PIN tw_d1[18]
  DIRECTION INPUT ;
  USE SIGNAL ;
  PORT
   LAYER M5 ;
   RECT 188.112000 0.000000 188.136000 0.084000 ;
  END
 END tw_d1[18]
 PIN tw_d1[19]
  DIRECTION INPUT ;
  USE SIGNAL ;
  PORT
   LAYER M5 ;
   RECT 188.304000 0.000000 188.328000 0.084000 ;
  END
 END tw_d1[19]
 PIN tw_d1[20]
  DIRECTION INPUT ;
  USE SIGNAL ;
  PORT
   LAYER M5 ;
   RECT 188.496000 0.000000 188.520000 0.084000 ;
  END
 END tw_d1[20]
 PIN tw_d1[21]
  DIRECTION INPUT ;
  USE SIGNAL ;
  PORT
   LAYER M5 ;
   RECT 188.688000 0.000000 188.712000 0.084000 ;
  END
 END tw_d1[21]
 PIN tw_d1[22]
  DIRECTION INPUT ;
  USE SIGNAL ;
  PORT
   LAYER M5 ;
   RECT 188.880000 0.000000 188.904000 0.084000 ;
  END
 END tw_d1[22]
 PIN tw_d1[23]
  DIRECTION INPUT ;
  USE SIGNAL ;
  PORT
   LAYER M5 ;
   RECT 189.072000 0.000000 189.096000 0.084000 ;
  END
 END tw_d1[23]
 PIN tw_d1[24]
  DIRECTION INPUT ;
  USE SIGNAL ;
  PORT
   LAYER M5 ;
   RECT 189.264000 0.000000 189.288000 0.084000 ;
  END
 END tw_d1[24]
 PIN tw_d1[25]
  DIRECTION INPUT ;
  USE SIGNAL ;
  PORT
   LAYER M5 ;
   RECT 189.456000 0.000000 189.480000 0.084000 ;
  END
 END tw_d1[25]
 PIN tw_d1[26]
  DIRECTION INPUT ;
  USE SIGNAL ;
  PORT
   LAYER M5 ;
   RECT 189.648000 0.000000 189.672000 0.084000 ;
  END
 END tw_d1[26]
 PIN tw_d1[27]
  DIRECTION INPUT ;
  USE SIGNAL ;
  PORT
   LAYER M5 ;
   RECT 189.840000 0.000000 189.864000 0.084000 ;
  END
 END tw_d1[27]
 PIN tw_d1[28]
  DIRECTION INPUT ;
  USE SIGNAL ;
  PORT
   LAYER M5 ;
   RECT 190.032000 0.000000 190.056000 0.084000 ;
  END
 END tw_d1[28]
 PIN tw_d1[29]
  DIRECTION INPUT ;
  USE SIGNAL ;
  PORT
   LAYER M5 ;
   RECT 190.224000 0.000000 190.248000 0.084000 ;
  END
 END tw_d1[29]
 PIN tw_d1[30]
  DIRECTION INPUT ;
  USE SIGNAL ;
  PORT
   LAYER M5 ;
   RECT 190.416000 0.000000 190.440000 0.084000 ;
  END
 END tw_d1[30]
 PIN tw_d1[31]
  DIRECTION INPUT ;
  USE SIGNAL ;
  PORT
   LAYER M5 ;
   RECT 190.608000 0.000000 190.632000 0.084000 ;
  END
 END tw_d1[31]
 PIN tw_d1[32]
  DIRECTION INPUT ;
  USE SIGNAL ;
  PORT
   LAYER M5 ;
   RECT 190.800000 0.000000 190.824000 0.084000 ;
  END
 END tw_d1[32]
 PIN tw_d1[33]
  DIRECTION INPUT ;
  USE SIGNAL ;
  PORT
   LAYER M5 ;
   RECT 190.992000 0.000000 191.016000 0.084000 ;
  END
 END tw_d1[33]
 PIN tw_d1[34]
  DIRECTION INPUT ;
  USE SIGNAL ;
  PORT
   LAYER M5 ;
   RECT 191.184000 0.000000 191.208000 0.084000 ;
  END
 END tw_d1[34]
 PIN tw_d1[35]
  DIRECTION INPUT ;
  USE SIGNAL ;
  PORT
   LAYER M5 ;
   RECT 191.376000 0.000000 191.400000 0.084000 ;
  END
 END tw_d1[35]
 PIN tw_d1[36]
  DIRECTION INPUT ;
  USE SIGNAL ;
  PORT
   LAYER M5 ;
   RECT 191.568000 0.000000 191.592000 0.084000 ;
  END
 END tw_d1[36]
 PIN tw_d1[37]
  DIRECTION INPUT ;
  USE SIGNAL ;
  PORT
   LAYER M5 ;
   RECT 191.760000 0.000000 191.784000 0.084000 ;
  END
 END tw_d1[37]
 PIN tw_d1[38]
  DIRECTION INPUT ;
  USE SIGNAL ;
  PORT
   LAYER M5 ;
   RECT 191.952000 0.000000 191.976000 0.084000 ;
  END
 END tw_d1[38]
 PIN tw_d1[39]
  DIRECTION INPUT ;
  USE SIGNAL ;
  PORT
   LAYER M5 ;
   RECT 192.432000 0.000000 192.456000 0.084000 ;
  END
 END tw_d1[39]
 PIN tw_d1[40]
  DIRECTION INPUT ;
  USE SIGNAL ;
  PORT
   LAYER M5 ;
   RECT 192.624000 0.000000 192.648000 0.084000 ;
  END
 END tw_d1[40]
 PIN tw_d1[41]
  DIRECTION INPUT ;
  USE SIGNAL ;
  PORT
   LAYER M5 ;
   RECT 192.816000 0.000000 192.840000 0.084000 ;
  END
 END tw_d1[41]
 PIN tw_d1[42]
  DIRECTION INPUT ;
  USE SIGNAL ;
  PORT
   LAYER M5 ;
   RECT 193.008000 0.000000 193.032000 0.084000 ;
  END
 END tw_d1[42]
 PIN tw_d1[43]
  DIRECTION INPUT ;
  USE SIGNAL ;
  PORT
   LAYER M5 ;
   RECT 193.200000 0.000000 193.224000 0.084000 ;
  END
 END tw_d1[43]
 PIN tw_d1[44]
  DIRECTION INPUT ;
  USE SIGNAL ;
  PORT
   LAYER M5 ;
   RECT 193.392000 0.000000 193.416000 0.084000 ;
  END
 END tw_d1[44]
 PIN tw_d1[45]
  DIRECTION INPUT ;
  USE SIGNAL ;
  PORT
   LAYER M5 ;
   RECT 193.584000 0.000000 193.608000 0.084000 ;
  END
 END tw_d1[45]
 PIN tw_d1[46]
  DIRECTION INPUT ;
  USE SIGNAL ;
  PORT
   LAYER M5 ;
   RECT 193.776000 0.000000 193.800000 0.084000 ;
  END
 END tw_d1[46]
 PIN tw_d1[47]
  DIRECTION INPUT ;
  USE SIGNAL ;
  PORT
   LAYER M5 ;
   RECT 193.968000 0.000000 193.992000 0.084000 ;
  END
 END tw_d1[47]
 PIN tw_d1[48]
  DIRECTION INPUT ;
  USE SIGNAL ;
  PORT
   LAYER M5 ;
   RECT 194.160000 0.000000 194.184000 0.084000 ;
  END
 END tw_d1[48]
 PIN tw_d1[49]
  DIRECTION INPUT ;
  USE SIGNAL ;
  PORT
   LAYER M5 ;
   RECT 194.352000 0.000000 194.376000 0.084000 ;
  END
 END tw_d1[49]
 PIN tw_d1[50]
  DIRECTION INPUT ;
  USE SIGNAL ;
  PORT
   LAYER M5 ;
   RECT 194.544000 0.000000 194.568000 0.084000 ;
  END
 END tw_d1[50]
 PIN tw_d1[51]
  DIRECTION INPUT ;
  USE SIGNAL ;
  PORT
   LAYER M5 ;
   RECT 194.736000 0.000000 194.760000 0.084000 ;
  END
 END tw_d1[51]
 PIN tw_d1[52]
  DIRECTION INPUT ;
  USE SIGNAL ;
  PORT
   LAYER M5 ;
   RECT 194.928000 0.000000 194.952000 0.084000 ;
  END
 END tw_d1[52]
 PIN tw_d1[53]
  DIRECTION INPUT ;
  USE SIGNAL ;
  PORT
   LAYER M5 ;
   RECT 195.120000 0.000000 195.144000 0.084000 ;
  END
 END tw_d1[53]
 PIN tw_d1[54]
  DIRECTION INPUT ;
  USE SIGNAL ;
  PORT
   LAYER M5 ;
   RECT 195.312000 0.000000 195.336000 0.084000 ;
  END
 END tw_d1[54]
 PIN tw_d1[55]
  DIRECTION INPUT ;
  USE SIGNAL ;
  PORT
   LAYER M5 ;
   RECT 195.504000 0.000000 195.528000 0.084000 ;
  END
 END tw_d1[55]
 PIN tw_d1[56]
  DIRECTION INPUT ;
  USE SIGNAL ;
  PORT
   LAYER M5 ;
   RECT 195.696000 0.000000 195.720000 0.084000 ;
  END
 END tw_d1[56]
 PIN tw_d1[57]
  DIRECTION INPUT ;
  USE SIGNAL ;
  PORT
   LAYER M5 ;
   RECT 195.888000 0.000000 195.912000 0.084000 ;
  END
 END tw_d1[57]
 PIN tw_d1[58]
  DIRECTION INPUT ;
  USE SIGNAL ;
  PORT
   LAYER M5 ;
   RECT 196.080000 0.000000 196.104000 0.084000 ;
  END
 END tw_d1[58]
 PIN tw_d1[59]
  DIRECTION INPUT ;
  USE SIGNAL ;
  PORT
   LAYER M5 ;
   RECT 196.272000 0.000000 196.296000 0.084000 ;
  END
 END tw_d1[59]
 PIN tw_d1[60]
  DIRECTION INPUT ;
  USE SIGNAL ;
  PORT
   LAYER M5 ;
   RECT 196.752000 0.000000 196.776000 0.084000 ;
  END
 END tw_d1[60]
 PIN tw_d1[61]
  DIRECTION INPUT ;
  USE SIGNAL ;
  PORT
   LAYER M5 ;
   RECT 196.944000 0.000000 196.968000 0.084000 ;
  END
 END tw_d1[61]
 PIN tw_d1[62]
  DIRECTION INPUT ;
  USE SIGNAL ;
  PORT
   LAYER M5 ;
   RECT 197.136000 0.000000 197.160000 0.084000 ;
  END
 END tw_d1[62]
 PIN tw_d1[63]
  DIRECTION INPUT ;
  USE SIGNAL ;
  PORT
   LAYER M5 ;
   RECT 197.328000 0.000000 197.352000 0.084000 ;
  END
 END tw_d1[63]
 PIN tw_d1[64]
  DIRECTION INPUT ;
  USE SIGNAL ;
  PORT
   LAYER M5 ;
   RECT 197.520000 0.000000 197.544000 0.084000 ;
  END
 END tw_d1[64]
 PIN tw_d1[65]
  DIRECTION INPUT ;
  USE SIGNAL ;
  PORT
   LAYER M5 ;
   RECT 197.712000 0.000000 197.736000 0.084000 ;
  END
 END tw_d1[65]
 PIN tw_d1[66]
  DIRECTION INPUT ;
  USE SIGNAL ;
  PORT
   LAYER M5 ;
   RECT 197.904000 0.000000 197.928000 0.084000 ;
  END
 END tw_d1[66]
 PIN tw_d1[67]
  DIRECTION INPUT ;
  USE SIGNAL ;
  PORT
   LAYER M5 ;
   RECT 198.096000 0.000000 198.120000 0.084000 ;
  END
 END tw_d1[67]
 PIN tw_d1[68]
  DIRECTION INPUT ;
  USE SIGNAL ;
  PORT
   LAYER M5 ;
   RECT 198.288000 0.000000 198.312000 0.084000 ;
  END
 END tw_d1[68]
 PIN tw_d1[69]
  DIRECTION INPUT ;
  USE SIGNAL ;
  PORT
   LAYER M5 ;
   RECT 198.480000 0.000000 198.504000 0.084000 ;
  END
 END tw_d1[69]
 PIN tw_d1[70]
  DIRECTION INPUT ;
  USE SIGNAL ;
  PORT
   LAYER M5 ;
   RECT 198.672000 0.000000 198.696000 0.084000 ;
  END
 END tw_d1[70]
 PIN tw_d1[71]
  DIRECTION INPUT ;
  USE SIGNAL ;
  PORT
   LAYER M5 ;
   RECT 198.864000 0.000000 198.888000 0.084000 ;
  END
 END tw_d1[71]
 PIN tw_d1[72]
  DIRECTION INPUT ;
  USE SIGNAL ;
  PORT
   LAYER M5 ;
   RECT 199.056000 0.000000 199.080000 0.084000 ;
  END
 END tw_d1[72]
 PIN tw_d1[73]
  DIRECTION INPUT ;
  USE SIGNAL ;
  PORT
   LAYER M5 ;
   RECT 199.248000 0.000000 199.272000 0.084000 ;
  END
 END tw_d1[73]
 PIN tw_d1[74]
  DIRECTION INPUT ;
  USE SIGNAL ;
  PORT
   LAYER M5 ;
   RECT 199.440000 0.000000 199.464000 0.084000 ;
  END
 END tw_d1[74]
 PIN tw_d1[75]
  DIRECTION INPUT ;
  USE SIGNAL ;
  PORT
   LAYER M5 ;
   RECT 199.632000 0.000000 199.656000 0.084000 ;
  END
 END tw_d1[75]
 PIN tw_d1[76]
  DIRECTION INPUT ;
  USE SIGNAL ;
  PORT
   LAYER M5 ;
   RECT 199.824000 0.000000 199.848000 0.084000 ;
  END
 END tw_d1[76]
 PIN tw_d1[77]
  DIRECTION INPUT ;
  USE SIGNAL ;
  PORT
   LAYER M5 ;
   RECT 200.016000 0.000000 200.040000 0.084000 ;
  END
 END tw_d1[77]
 PIN tw_d1[78]
  DIRECTION INPUT ;
  USE SIGNAL ;
  PORT
   LAYER M5 ;
   RECT 200.208000 0.000000 200.232000 0.084000 ;
  END
 END tw_d1[78]
 PIN tw_d1[79]
  DIRECTION INPUT ;
  USE SIGNAL ;
  PORT
   LAYER M5 ;
   RECT 200.400000 0.000000 200.424000 0.084000 ;
  END
 END tw_d1[79]
 PIN tw_d1[80]
  DIRECTION INPUT ;
  USE SIGNAL ;
  PORT
   LAYER M5 ;
   RECT 200.592000 0.000000 200.616000 0.084000 ;
  END
 END tw_d1[80]
 PIN tw_d1[81]
  DIRECTION INPUT ;
  USE SIGNAL ;
  PORT
   LAYER M5 ;
   RECT 201.072000 0.000000 201.096000 0.084000 ;
  END
 END tw_d1[81]
 PIN tw_d1[82]
  DIRECTION INPUT ;
  USE SIGNAL ;
  PORT
   LAYER M5 ;
   RECT 201.264000 0.000000 201.288000 0.084000 ;
  END
 END tw_d1[82]
 PIN tw_d1[83]
  DIRECTION INPUT ;
  USE SIGNAL ;
  PORT
   LAYER M5 ;
   RECT 201.456000 0.000000 201.480000 0.084000 ;
  END
 END tw_d1[83]
 PIN tw_d1[84]
  DIRECTION INPUT ;
  USE SIGNAL ;
  PORT
   LAYER M5 ;
   RECT 201.648000 0.000000 201.672000 0.084000 ;
  END
 END tw_d1[84]
 PIN tw_d1[85]
  DIRECTION INPUT ;
  USE SIGNAL ;
  PORT
   LAYER M5 ;
   RECT 201.840000 0.000000 201.864000 0.084000 ;
  END
 END tw_d1[85]
 PIN tw_d1[86]
  DIRECTION INPUT ;
  USE SIGNAL ;
  PORT
   LAYER M5 ;
   RECT 202.032000 0.000000 202.056000 0.084000 ;
  END
 END tw_d1[86]
 PIN tw_d1[87]
  DIRECTION INPUT ;
  USE SIGNAL ;
  PORT
   LAYER M5 ;
   RECT 202.224000 0.000000 202.248000 0.084000 ;
  END
 END tw_d1[87]
 PIN tw_d1[88]
  DIRECTION INPUT ;
  USE SIGNAL ;
  PORT
   LAYER M5 ;
   RECT 202.416000 0.000000 202.440000 0.084000 ;
  END
 END tw_d1[88]
 PIN tw_d1[89]
  DIRECTION INPUT ;
  USE SIGNAL ;
  PORT
   LAYER M5 ;
   RECT 202.608000 0.000000 202.632000 0.084000 ;
  END
 END tw_d1[89]
 PIN tw_d1[90]
  DIRECTION INPUT ;
  USE SIGNAL ;
  PORT
   LAYER M5 ;
   RECT 202.800000 0.000000 202.824000 0.084000 ;
  END
 END tw_d1[90]
 PIN tw_d1[91]
  DIRECTION INPUT ;
  USE SIGNAL ;
  PORT
   LAYER M5 ;
   RECT 202.992000 0.000000 203.016000 0.084000 ;
  END
 END tw_d1[91]
 PIN tw_d1[92]
  DIRECTION INPUT ;
  USE SIGNAL ;
  PORT
   LAYER M5 ;
   RECT 203.184000 0.000000 203.208000 0.084000 ;
  END
 END tw_d1[92]
 PIN tw_d1[93]
  DIRECTION INPUT ;
  USE SIGNAL ;
  PORT
   LAYER M5 ;
   RECT 203.376000 0.000000 203.400000 0.084000 ;
  END
 END tw_d1[93]
 PIN tw_d1[94]
  DIRECTION INPUT ;
  USE SIGNAL ;
  PORT
   LAYER M5 ;
   RECT 203.568000 0.000000 203.592000 0.084000 ;
  END
 END tw_d1[94]
 PIN tw_d1[95]
  DIRECTION INPUT ;
  USE SIGNAL ;
  PORT
   LAYER M5 ;
   RECT 203.760000 0.000000 203.784000 0.084000 ;
  END
 END tw_d1[95]
 PIN tw_d1[96]
  DIRECTION INPUT ;
  USE SIGNAL ;
  PORT
   LAYER M5 ;
   RECT 203.952000 0.000000 203.976000 0.084000 ;
  END
 END tw_d1[96]
 PIN tw_d1[97]
  DIRECTION INPUT ;
  USE SIGNAL ;
  PORT
   LAYER M5 ;
   RECT 204.144000 0.000000 204.168000 0.084000 ;
  END
 END tw_d1[97]
 PIN tw_d1[98]
  DIRECTION INPUT ;
  USE SIGNAL ;
  PORT
   LAYER M5 ;
   RECT 204.336000 0.000000 204.360000 0.084000 ;
  END
 END tw_d1[98]
 PIN tw_d1[99]
  DIRECTION INPUT ;
  USE SIGNAL ;
  PORT
   LAYER M5 ;
   RECT 204.528000 0.000000 204.552000 0.084000 ;
  END
 END tw_d1[99]
 PIN tw_d1[100]
  DIRECTION INPUT ;
  USE SIGNAL ;
  PORT
   LAYER M5 ;
   RECT 204.720000 0.000000 204.744000 0.084000 ;
  END
 END tw_d1[100]
 PIN tw_d1[101]
  DIRECTION INPUT ;
  USE SIGNAL ;
  PORT
   LAYER M5 ;
   RECT 204.912000 0.000000 204.936000 0.084000 ;
  END
 END tw_d1[101]
 PIN tw_d1[102]
  DIRECTION INPUT ;
  USE SIGNAL ;
  PORT
   LAYER M5 ;
   RECT 205.392000 0.000000 205.416000 0.084000 ;
  END
 END tw_d1[102]
 PIN tw_d1[103]
  DIRECTION INPUT ;
  USE SIGNAL ;
  PORT
   LAYER M5 ;
   RECT 205.584000 0.000000 205.608000 0.084000 ;
  END
 END tw_d1[103]
 PIN tw_d1[104]
  DIRECTION INPUT ;
  USE SIGNAL ;
  PORT
   LAYER M5 ;
   RECT 205.776000 0.000000 205.800000 0.084000 ;
  END
 END tw_d1[104]
 PIN tw_d1[105]
  DIRECTION INPUT ;
  USE SIGNAL ;
  PORT
   LAYER M5 ;
   RECT 205.968000 0.000000 205.992000 0.084000 ;
  END
 END tw_d1[105]
 PIN tw_d1[106]
  DIRECTION INPUT ;
  USE SIGNAL ;
  PORT
   LAYER M5 ;
   RECT 206.160000 0.000000 206.184000 0.084000 ;
  END
 END tw_d1[106]
 PIN tw_d1[107]
  DIRECTION INPUT ;
  USE SIGNAL ;
  PORT
   LAYER M5 ;
   RECT 206.352000 0.000000 206.376000 0.084000 ;
  END
 END tw_d1[107]
 PIN tw_d1[108]
  DIRECTION INPUT ;
  USE SIGNAL ;
  PORT
   LAYER M5 ;
   RECT 206.544000 0.000000 206.568000 0.084000 ;
  END
 END tw_d1[108]
 PIN tw_d1[109]
  DIRECTION INPUT ;
  USE SIGNAL ;
  PORT
   LAYER M5 ;
   RECT 206.736000 0.000000 206.760000 0.084000 ;
  END
 END tw_d1[109]
 PIN tw_d1[110]
  DIRECTION INPUT ;
  USE SIGNAL ;
  PORT
   LAYER M5 ;
   RECT 206.928000 0.000000 206.952000 0.084000 ;
  END
 END tw_d1[110]
 PIN tw_d1[111]
  DIRECTION INPUT ;
  USE SIGNAL ;
  PORT
   LAYER M5 ;
   RECT 207.120000 0.000000 207.144000 0.084000 ;
  END
 END tw_d1[111]
 PIN tw_d1[112]
  DIRECTION INPUT ;
  USE SIGNAL ;
  PORT
   LAYER M5 ;
   RECT 207.312000 0.000000 207.336000 0.084000 ;
  END
 END tw_d1[112]
 PIN tw_d1[113]
  DIRECTION INPUT ;
  USE SIGNAL ;
  PORT
   LAYER M5 ;
   RECT 207.504000 0.000000 207.528000 0.084000 ;
  END
 END tw_d1[113]
 PIN tw_d1[114]
  DIRECTION INPUT ;
  USE SIGNAL ;
  PORT
   LAYER M5 ;
   RECT 207.696000 0.000000 207.720000 0.084000 ;
  END
 END tw_d1[114]
 PIN tw_d1[115]
  DIRECTION INPUT ;
  USE SIGNAL ;
  PORT
   LAYER M5 ;
   RECT 207.888000 0.000000 207.912000 0.084000 ;
  END
 END tw_d1[115]
 PIN tw_d1[116]
  DIRECTION INPUT ;
  USE SIGNAL ;
  PORT
   LAYER M5 ;
   RECT 208.080000 0.000000 208.104000 0.084000 ;
  END
 END tw_d1[116]
 PIN tw_d1[117]
  DIRECTION INPUT ;
  USE SIGNAL ;
  PORT
   LAYER M5 ;
   RECT 208.272000 0.000000 208.296000 0.084000 ;
  END
 END tw_d1[117]
 PIN tw_d1[118]
  DIRECTION INPUT ;
  USE SIGNAL ;
  PORT
   LAYER M5 ;
   RECT 208.464000 0.000000 208.488000 0.084000 ;
  END
 END tw_d1[118]
 PIN tw_d1[119]
  DIRECTION INPUT ;
  USE SIGNAL ;
  PORT
   LAYER M5 ;
   RECT 208.656000 0.000000 208.680000 0.084000 ;
  END
 END tw_d1[119]
 PIN tw_d1[120]
  DIRECTION INPUT ;
  USE SIGNAL ;
  PORT
   LAYER M5 ;
   RECT 208.848000 0.000000 208.872000 0.084000 ;
  END
 END tw_d1[120]
 PIN tw_d1[121]
  DIRECTION INPUT ;
  USE SIGNAL ;
  PORT
   LAYER M5 ;
   RECT 209.040000 0.000000 209.064000 0.084000 ;
  END
 END tw_d1[121]
 PIN tw_d1[122]
  DIRECTION INPUT ;
  USE SIGNAL ;
  PORT
   LAYER M5 ;
   RECT 209.232000 0.000000 209.256000 0.084000 ;
  END
 END tw_d1[122]
 PIN tw_d1[123]
  DIRECTION INPUT ;
  USE SIGNAL ;
  PORT
   LAYER M5 ;
   RECT 209.712000 0.000000 209.736000 0.084000 ;
  END
 END tw_d1[123]
 PIN tw_d1[124]
  DIRECTION INPUT ;
  USE SIGNAL ;
  PORT
   LAYER M5 ;
   RECT 209.904000 0.000000 209.928000 0.084000 ;
  END
 END tw_d1[124]
 PIN tw_d1[125]
  DIRECTION INPUT ;
  USE SIGNAL ;
  PORT
   LAYER M5 ;
   RECT 210.096000 0.000000 210.120000 0.084000 ;
  END
 END tw_d1[125]
 PIN tw_d1[126]
  DIRECTION INPUT ;
  USE SIGNAL ;
  PORT
   LAYER M5 ;
   RECT 210.288000 0.000000 210.312000 0.084000 ;
  END
 END tw_d1[126]
 PIN tw_d1[127]
  DIRECTION INPUT ;
  USE SIGNAL ;
  PORT
   LAYER M5 ;
   RECT 210.480000 0.000000 210.504000 0.084000 ;
  END
 END tw_d1[127]
 PIN tw_d1[128]
  DIRECTION INPUT ;
  USE SIGNAL ;
  PORT
   LAYER M5 ;
   RECT 210.672000 0.000000 210.696000 0.084000 ;
  END
 END tw_d1[128]
 PIN tw_d1[129]
  DIRECTION INPUT ;
  USE SIGNAL ;
  PORT
   LAYER M5 ;
   RECT 210.864000 0.000000 210.888000 0.084000 ;
  END
 END tw_d1[129]
 PIN tw_d1[130]
  DIRECTION INPUT ;
  USE SIGNAL ;
  PORT
   LAYER M5 ;
   RECT 211.056000 0.000000 211.080000 0.084000 ;
  END
 END tw_d1[130]
 PIN tw_d1[131]
  DIRECTION INPUT ;
  USE SIGNAL ;
  PORT
   LAYER M5 ;
   RECT 211.248000 0.000000 211.272000 0.084000 ;
  END
 END tw_d1[131]
 PIN tw_d1[132]
  DIRECTION INPUT ;
  USE SIGNAL ;
  PORT
   LAYER M5 ;
   RECT 211.440000 0.000000 211.464000 0.084000 ;
  END
 END tw_d1[132]
 PIN tw_d1[133]
  DIRECTION INPUT ;
  USE SIGNAL ;
  PORT
   LAYER M5 ;
   RECT 211.632000 0.000000 211.656000 0.084000 ;
  END
 END tw_d1[133]
 PIN tw_d1[134]
  DIRECTION INPUT ;
  USE SIGNAL ;
  PORT
   LAYER M5 ;
   RECT 211.824000 0.000000 211.848000 0.084000 ;
  END
 END tw_d1[134]
 PIN tw_d1[135]
  DIRECTION INPUT ;
  USE SIGNAL ;
  PORT
   LAYER M5 ;
   RECT 212.016000 0.000000 212.040000 0.084000 ;
  END
 END tw_d1[135]
 PIN tw_d1[136]
  DIRECTION INPUT ;
  USE SIGNAL ;
  PORT
   LAYER M5 ;
   RECT 212.208000 0.000000 212.232000 0.084000 ;
  END
 END tw_d1[136]
 PIN tw_d1[137]
  DIRECTION INPUT ;
  USE SIGNAL ;
  PORT
   LAYER M5 ;
   RECT 212.400000 0.000000 212.424000 0.084000 ;
  END
 END tw_d1[137]
 PIN tw_d1[138]
  DIRECTION INPUT ;
  USE SIGNAL ;
  PORT
   LAYER M5 ;
   RECT 212.592000 0.000000 212.616000 0.084000 ;
  END
 END tw_d1[138]
 PIN tw_d1[139]
  DIRECTION INPUT ;
  USE SIGNAL ;
  PORT
   LAYER M5 ;
   RECT 212.784000 0.000000 212.808000 0.084000 ;
  END
 END tw_d1[139]
 PIN tw_d1[140]
  DIRECTION INPUT ;
  USE SIGNAL ;
  PORT
   LAYER M5 ;
   RECT 212.976000 0.000000 213.000000 0.084000 ;
  END
 END tw_d1[140]
 PIN tw_d1[141]
  DIRECTION INPUT ;
  USE SIGNAL ;
  PORT
   LAYER M5 ;
   RECT 213.168000 0.000000 213.192000 0.084000 ;
  END
 END tw_d1[141]
 PIN tw_d1[142]
  DIRECTION INPUT ;
  USE SIGNAL ;
  PORT
   LAYER M5 ;
   RECT 213.360000 0.000000 213.384000 0.084000 ;
  END
 END tw_d1[142]
 PIN tw_d1[143]
  DIRECTION INPUT ;
  USE SIGNAL ;
  PORT
   LAYER M5 ;
   RECT 213.552000 0.000000 213.576000 0.084000 ;
  END
 END tw_d1[143]
 PIN tw_d1[144]
  DIRECTION INPUT ;
  USE SIGNAL ;
  PORT
   LAYER M5 ;
   RECT 214.032000 0.000000 214.056000 0.084000 ;
  END
 END tw_d1[144]
 PIN tw_d1[145]
  DIRECTION INPUT ;
  USE SIGNAL ;
  PORT
   LAYER M5 ;
   RECT 214.224000 0.000000 214.248000 0.084000 ;
  END
 END tw_d1[145]
 PIN tw_d1[146]
  DIRECTION INPUT ;
  USE SIGNAL ;
  PORT
   LAYER M5 ;
   RECT 214.416000 0.000000 214.440000 0.084000 ;
  END
 END tw_d1[146]
 PIN tw_d1[147]
  DIRECTION INPUT ;
  USE SIGNAL ;
  PORT
   LAYER M5 ;
   RECT 214.608000 0.000000 214.632000 0.084000 ;
  END
 END tw_d1[147]
 PIN tw_d1[148]
  DIRECTION INPUT ;
  USE SIGNAL ;
  PORT
   LAYER M5 ;
   RECT 214.800000 0.000000 214.824000 0.084000 ;
  END
 END tw_d1[148]
 PIN tw_d1[149]
  DIRECTION INPUT ;
  USE SIGNAL ;
  PORT
   LAYER M5 ;
   RECT 214.992000 0.000000 215.016000 0.084000 ;
  END
 END tw_d1[149]
 PIN tw_d1[150]
  DIRECTION INPUT ;
  USE SIGNAL ;
  PORT
   LAYER M5 ;
   RECT 215.184000 0.000000 215.208000 0.084000 ;
  END
 END tw_d1[150]
 PIN tw_d1[151]
  DIRECTION INPUT ;
  USE SIGNAL ;
  PORT
   LAYER M5 ;
   RECT 215.376000 0.000000 215.400000 0.084000 ;
  END
 END tw_d1[151]
 PIN tw_d1[152]
  DIRECTION INPUT ;
  USE SIGNAL ;
  PORT
   LAYER M5 ;
   RECT 215.568000 0.000000 215.592000 0.084000 ;
  END
 END tw_d1[152]
 PIN tw_d1[153]
  DIRECTION INPUT ;
  USE SIGNAL ;
  PORT
   LAYER M5 ;
   RECT 215.760000 0.000000 215.784000 0.084000 ;
  END
 END tw_d1[153]
 PIN tw_d1[154]
  DIRECTION INPUT ;
  USE SIGNAL ;
  PORT
   LAYER M5 ;
   RECT 215.952000 0.000000 215.976000 0.084000 ;
  END
 END tw_d1[154]
 PIN tw_d1[155]
  DIRECTION INPUT ;
  USE SIGNAL ;
  PORT
   LAYER M5 ;
   RECT 216.144000 0.000000 216.168000 0.084000 ;
  END
 END tw_d1[155]
 PIN tw_d1[156]
  DIRECTION INPUT ;
  USE SIGNAL ;
  PORT
   LAYER M5 ;
   RECT 216.336000 0.000000 216.360000 0.084000 ;
  END
 END tw_d1[156]
 PIN tw_d1[157]
  DIRECTION INPUT ;
  USE SIGNAL ;
  PORT
   LAYER M5 ;
   RECT 216.528000 0.000000 216.552000 0.084000 ;
  END
 END tw_d1[157]
 PIN tw_d1[158]
  DIRECTION INPUT ;
  USE SIGNAL ;
  PORT
   LAYER M5 ;
   RECT 216.720000 0.000000 216.744000 0.084000 ;
  END
 END tw_d1[158]
 PIN tw_d1[159]
  DIRECTION INPUT ;
  USE SIGNAL ;
  PORT
   LAYER M5 ;
   RECT 216.912000 0.000000 216.936000 0.084000 ;
  END
 END tw_d1[159]
 PIN tw_d1[160]
  DIRECTION INPUT ;
  USE SIGNAL ;
  PORT
   LAYER M5 ;
   RECT 217.104000 0.000000 217.128000 0.084000 ;
  END
 END tw_d1[160]
 PIN tw_d1[161]
  DIRECTION INPUT ;
  USE SIGNAL ;
  PORT
   LAYER M5 ;
   RECT 217.296000 0.000000 217.320000 0.084000 ;
  END
 END tw_d1[161]
 PIN tw_d1[162]
  DIRECTION INPUT ;
  USE SIGNAL ;
  PORT
   LAYER M5 ;
   RECT 217.488000 0.000000 217.512000 0.084000 ;
  END
 END tw_d1[162]
 PIN tw_d1[163]
  DIRECTION INPUT ;
  USE SIGNAL ;
  PORT
   LAYER M5 ;
   RECT 217.680000 0.000000 217.704000 0.084000 ;
  END
 END tw_d1[163]
 PIN tw_d1[164]
  DIRECTION INPUT ;
  USE SIGNAL ;
  PORT
   LAYER M5 ;
   RECT 217.872000 0.000000 217.896000 0.084000 ;
  END
 END tw_d1[164]
 PIN tw_d1[165]
  DIRECTION INPUT ;
  USE SIGNAL ;
  PORT
   LAYER M5 ;
   RECT 218.352000 0.000000 218.376000 0.084000 ;
  END
 END tw_d1[165]
 PIN tw_d1[166]
  DIRECTION INPUT ;
  USE SIGNAL ;
  PORT
   LAYER M5 ;
   RECT 218.544000 0.000000 218.568000 0.084000 ;
  END
 END tw_d1[166]
 PIN tw_d1[167]
  DIRECTION INPUT ;
  USE SIGNAL ;
  PORT
   LAYER M5 ;
   RECT 218.736000 0.000000 218.760000 0.084000 ;
  END
 END tw_d1[167]
 PIN tw_d1[168]
  DIRECTION INPUT ;
  USE SIGNAL ;
  PORT
   LAYER M5 ;
   RECT 218.928000 0.000000 218.952000 0.084000 ;
  END
 END tw_d1[168]
 PIN tw_d1[169]
  DIRECTION INPUT ;
  USE SIGNAL ;
  PORT
   LAYER M5 ;
   RECT 219.120000 0.000000 219.144000 0.084000 ;
  END
 END tw_d1[169]
 PIN tw_d1[170]
  DIRECTION INPUT ;
  USE SIGNAL ;
  PORT
   LAYER M5 ;
   RECT 219.312000 0.000000 219.336000 0.084000 ;
  END
 END tw_d1[170]
 PIN tw_d1[171]
  DIRECTION INPUT ;
  USE SIGNAL ;
  PORT
   LAYER M5 ;
   RECT 219.504000 0.000000 219.528000 0.084000 ;
  END
 END tw_d1[171]
 PIN tw_d1[172]
  DIRECTION INPUT ;
  USE SIGNAL ;
  PORT
   LAYER M5 ;
   RECT 219.696000 0.000000 219.720000 0.084000 ;
  END
 END tw_d1[172]
 PIN tw_d1[173]
  DIRECTION INPUT ;
  USE SIGNAL ;
  PORT
   LAYER M5 ;
   RECT 219.888000 0.000000 219.912000 0.084000 ;
  END
 END tw_d1[173]
 PIN tw_d1[174]
  DIRECTION INPUT ;
  USE SIGNAL ;
  PORT
   LAYER M5 ;
   RECT 220.080000 0.000000 220.104000 0.084000 ;
  END
 END tw_d1[174]
 PIN tw_d1[175]
  DIRECTION INPUT ;
  USE SIGNAL ;
  PORT
   LAYER M5 ;
   RECT 220.272000 0.000000 220.296000 0.084000 ;
  END
 END tw_d1[175]
 PIN tw_d1[176]
  DIRECTION INPUT ;
  USE SIGNAL ;
  PORT
   LAYER M5 ;
   RECT 220.464000 0.000000 220.488000 0.084000 ;
  END
 END tw_d1[176]
 PIN tw_d1[177]
  DIRECTION INPUT ;
  USE SIGNAL ;
  PORT
   LAYER M5 ;
   RECT 220.656000 0.000000 220.680000 0.084000 ;
  END
 END tw_d1[177]
 PIN tw_d1[178]
  DIRECTION INPUT ;
  USE SIGNAL ;
  PORT
   LAYER M5 ;
   RECT 220.848000 0.000000 220.872000 0.084000 ;
  END
 END tw_d1[178]
 PIN tw_d1[179]
  DIRECTION INPUT ;
  USE SIGNAL ;
  PORT
   LAYER M5 ;
   RECT 221.040000 0.000000 221.064000 0.084000 ;
  END
 END tw_d1[179]
 PIN tw_d1[180]
  DIRECTION INPUT ;
  USE SIGNAL ;
  PORT
   LAYER M5 ;
   RECT 221.232000 0.000000 221.256000 0.084000 ;
  END
 END tw_d1[180]
 PIN tw_d1[181]
  DIRECTION INPUT ;
  USE SIGNAL ;
  PORT
   LAYER M5 ;
   RECT 221.424000 0.000000 221.448000 0.084000 ;
  END
 END tw_d1[181]
 PIN tw_d1[182]
  DIRECTION INPUT ;
  USE SIGNAL ;
  PORT
   LAYER M5 ;
   RECT 221.616000 0.000000 221.640000 0.084000 ;
  END
 END tw_d1[182]
 PIN tw_d1[183]
  DIRECTION INPUT ;
  USE SIGNAL ;
  PORT
   LAYER M5 ;
   RECT 221.808000 0.000000 221.832000 0.084000 ;
  END
 END tw_d1[183]
 PIN tw_d1[184]
  DIRECTION INPUT ;
  USE SIGNAL ;
  PORT
   LAYER M5 ;
   RECT 222.000000 0.000000 222.024000 0.084000 ;
  END
 END tw_d1[184]
 PIN tw_d1[185]
  DIRECTION INPUT ;
  USE SIGNAL ;
  PORT
   LAYER M5 ;
   RECT 222.192000 0.000000 222.216000 0.084000 ;
  END
 END tw_d1[185]
 PIN tw_d1[186]
  DIRECTION INPUT ;
  USE SIGNAL ;
  PORT
   LAYER M5 ;
   RECT 222.672000 0.000000 222.696000 0.084000 ;
  END
 END tw_d1[186]
 PIN tw_d1[187]
  DIRECTION INPUT ;
  USE SIGNAL ;
  PORT
   LAYER M5 ;
   RECT 222.864000 0.000000 222.888000 0.084000 ;
  END
 END tw_d1[187]
 PIN tw_d1[188]
  DIRECTION INPUT ;
  USE SIGNAL ;
  PORT
   LAYER M5 ;
   RECT 223.056000 0.000000 223.080000 0.084000 ;
  END
 END tw_d1[188]
 PIN tw_d1[189]
  DIRECTION INPUT ;
  USE SIGNAL ;
  PORT
   LAYER M5 ;
   RECT 223.248000 0.000000 223.272000 0.084000 ;
  END
 END tw_d1[189]
 PIN tw_d1[190]
  DIRECTION INPUT ;
  USE SIGNAL ;
  PORT
   LAYER M5 ;
   RECT 223.440000 0.000000 223.464000 0.084000 ;
  END
 END tw_d1[190]
 PIN tw_d1[191]
  DIRECTION INPUT ;
  USE SIGNAL ;
  PORT
   LAYER M5 ;
   RECT 223.632000 0.000000 223.656000 0.084000 ;
  END
 END tw_d1[191]
 PIN tw_d1[192]
  DIRECTION INPUT ;
  USE SIGNAL ;
  PORT
   LAYER M5 ;
   RECT 223.824000 0.000000 223.848000 0.084000 ;
  END
 END tw_d1[192]
 PIN tw_d1[193]
  DIRECTION INPUT ;
  USE SIGNAL ;
  PORT
   LAYER M5 ;
   RECT 224.016000 0.000000 224.040000 0.084000 ;
  END
 END tw_d1[193]
 PIN tw_d1[194]
  DIRECTION INPUT ;
  USE SIGNAL ;
  PORT
   LAYER M5 ;
   RECT 224.208000 0.000000 224.232000 0.084000 ;
  END
 END tw_d1[194]
 PIN tw_d1[195]
  DIRECTION INPUT ;
  USE SIGNAL ;
  PORT
   LAYER M5 ;
   RECT 224.400000 0.000000 224.424000 0.084000 ;
  END
 END tw_d1[195]
 PIN tw_d1[196]
  DIRECTION INPUT ;
  USE SIGNAL ;
  PORT
   LAYER M5 ;
   RECT 224.592000 0.000000 224.616000 0.084000 ;
  END
 END tw_d1[196]
 PIN tw_d1[197]
  DIRECTION INPUT ;
  USE SIGNAL ;
  PORT
   LAYER M5 ;
   RECT 224.784000 0.000000 224.808000 0.084000 ;
  END
 END tw_d1[197]
 PIN tw_d1[198]
  DIRECTION INPUT ;
  USE SIGNAL ;
  PORT
   LAYER M5 ;
   RECT 224.976000 0.000000 225.000000 0.084000 ;
  END
 END tw_d1[198]
 PIN tw_d1[199]
  DIRECTION INPUT ;
  USE SIGNAL ;
  PORT
   LAYER M5 ;
   RECT 225.168000 0.000000 225.192000 0.084000 ;
  END
 END tw_d1[199]
 PIN tw_d1[200]
  DIRECTION INPUT ;
  USE SIGNAL ;
  PORT
   LAYER M5 ;
   RECT 225.360000 0.000000 225.384000 0.084000 ;
  END
 END tw_d1[200]
 PIN tw_d1[201]
  DIRECTION INPUT ;
  USE SIGNAL ;
  PORT
   LAYER M5 ;
   RECT 225.552000 0.000000 225.576000 0.084000 ;
  END
 END tw_d1[201]
 PIN tw_d1[202]
  DIRECTION INPUT ;
  USE SIGNAL ;
  PORT
   LAYER M5 ;
   RECT 225.744000 0.000000 225.768000 0.084000 ;
  END
 END tw_d1[202]
 PIN tw_d1[203]
  DIRECTION INPUT ;
  USE SIGNAL ;
  PORT
   LAYER M5 ;
   RECT 225.936000 0.000000 225.960000 0.084000 ;
  END
 END tw_d1[203]
 PIN tw_d1[204]
  DIRECTION INPUT ;
  USE SIGNAL ;
  PORT
   LAYER M5 ;
   RECT 226.128000 0.000000 226.152000 0.084000 ;
  END
 END tw_d1[204]
 PIN tw_d1[205]
  DIRECTION INPUT ;
  USE SIGNAL ;
  PORT
   LAYER M5 ;
   RECT 226.320000 0.000000 226.344000 0.084000 ;
  END
 END tw_d1[205]
 PIN tw_d1[206]
  DIRECTION INPUT ;
  USE SIGNAL ;
  PORT
   LAYER M5 ;
   RECT 226.512000 0.000000 226.536000 0.084000 ;
  END
 END tw_d1[206]
 PIN tw_d1[207]
  DIRECTION INPUT ;
  USE SIGNAL ;
  PORT
   LAYER M5 ;
   RECT 226.992000 0.000000 227.016000 0.084000 ;
  END
 END tw_d1[207]
 PIN tw_d1[208]
  DIRECTION INPUT ;
  USE SIGNAL ;
  PORT
   LAYER M5 ;
   RECT 227.184000 0.000000 227.208000 0.084000 ;
  END
 END tw_d1[208]
 PIN tw_d1[209]
  DIRECTION INPUT ;
  USE SIGNAL ;
  PORT
   LAYER M5 ;
   RECT 227.376000 0.000000 227.400000 0.084000 ;
  END
 END tw_d1[209]
 PIN tw_d1[210]
  DIRECTION INPUT ;
  USE SIGNAL ;
  PORT
   LAYER M5 ;
   RECT 227.568000 0.000000 227.592000 0.084000 ;
  END
 END tw_d1[210]
 PIN tw_d1[211]
  DIRECTION INPUT ;
  USE SIGNAL ;
  PORT
   LAYER M5 ;
   RECT 227.760000 0.000000 227.784000 0.084000 ;
  END
 END tw_d1[211]
 PIN tw_d1[212]
  DIRECTION INPUT ;
  USE SIGNAL ;
  PORT
   LAYER M5 ;
   RECT 227.952000 0.000000 227.976000 0.084000 ;
  END
 END tw_d1[212]
 PIN tw_d1[213]
  DIRECTION INPUT ;
  USE SIGNAL ;
  PORT
   LAYER M5 ;
   RECT 228.144000 0.000000 228.168000 0.084000 ;
  END
 END tw_d1[213]
 PIN tw_d1[214]
  DIRECTION INPUT ;
  USE SIGNAL ;
  PORT
   LAYER M5 ;
   RECT 228.336000 0.000000 228.360000 0.084000 ;
  END
 END tw_d1[214]
 PIN tw_d1[215]
  DIRECTION INPUT ;
  USE SIGNAL ;
  PORT
   LAYER M5 ;
   RECT 228.528000 0.000000 228.552000 0.084000 ;
  END
 END tw_d1[215]
 PIN tw_d1[216]
  DIRECTION INPUT ;
  USE SIGNAL ;
  PORT
   LAYER M5 ;
   RECT 228.720000 0.000000 228.744000 0.084000 ;
  END
 END tw_d1[216]
 PIN tw_d1[217]
  DIRECTION INPUT ;
  USE SIGNAL ;
  PORT
   LAYER M5 ;
   RECT 228.912000 0.000000 228.936000 0.084000 ;
  END
 END tw_d1[217]
 PIN tw_d1[218]
  DIRECTION INPUT ;
  USE SIGNAL ;
  PORT
   LAYER M5 ;
   RECT 229.104000 0.000000 229.128000 0.084000 ;
  END
 END tw_d1[218]
 PIN tw_d1[219]
  DIRECTION INPUT ;
  USE SIGNAL ;
  PORT
   LAYER M5 ;
   RECT 229.296000 0.000000 229.320000 0.084000 ;
  END
 END tw_d1[219]
 PIN tw_d1[220]
  DIRECTION INPUT ;
  USE SIGNAL ;
  PORT
   LAYER M5 ;
   RECT 229.488000 0.000000 229.512000 0.084000 ;
  END
 END tw_d1[220]
 PIN tw_d1[221]
  DIRECTION INPUT ;
  USE SIGNAL ;
  PORT
   LAYER M5 ;
   RECT 229.680000 0.000000 229.704000 0.084000 ;
  END
 END tw_d1[221]
 PIN tw_d1[222]
  DIRECTION INPUT ;
  USE SIGNAL ;
  PORT
   LAYER M5 ;
   RECT 229.872000 0.000000 229.896000 0.084000 ;
  END
 END tw_d1[222]
 PIN tw_d1[223]
  DIRECTION INPUT ;
  USE SIGNAL ;
  PORT
   LAYER M5 ;
   RECT 230.064000 0.000000 230.088000 0.084000 ;
  END
 END tw_d1[223]
 PIN tw_d1[224]
  DIRECTION INPUT ;
  USE SIGNAL ;
  PORT
   LAYER M5 ;
   RECT 230.256000 0.000000 230.280000 0.084000 ;
  END
 END tw_d1[224]
 PIN tw_d1[225]
  DIRECTION INPUT ;
  USE SIGNAL ;
  PORT
   LAYER M5 ;
   RECT 230.448000 0.000000 230.472000 0.084000 ;
  END
 END tw_d1[225]
 PIN tw_d1[226]
  DIRECTION INPUT ;
  USE SIGNAL ;
  PORT
   LAYER M5 ;
   RECT 230.640000 0.000000 230.664000 0.084000 ;
  END
 END tw_d1[226]
 PIN tw_d1[227]
  DIRECTION INPUT ;
  USE SIGNAL ;
  PORT
   LAYER M5 ;
   RECT 230.832000 0.000000 230.856000 0.084000 ;
  END
 END tw_d1[227]
 PIN tw_d1[228]
  DIRECTION INPUT ;
  USE SIGNAL ;
  PORT
   LAYER M5 ;
   RECT 231.312000 0.000000 231.336000 0.084000 ;
  END
 END tw_d1[228]
 PIN tw_d1[229]
  DIRECTION INPUT ;
  USE SIGNAL ;
  PORT
   LAYER M5 ;
   RECT 231.504000 0.000000 231.528000 0.084000 ;
  END
 END tw_d1[229]
 PIN tw_d1[230]
  DIRECTION INPUT ;
  USE SIGNAL ;
  PORT
   LAYER M5 ;
   RECT 231.696000 0.000000 231.720000 0.084000 ;
  END
 END tw_d1[230]
 PIN tw_d1[231]
  DIRECTION INPUT ;
  USE SIGNAL ;
  PORT
   LAYER M5 ;
   RECT 231.888000 0.000000 231.912000 0.084000 ;
  END
 END tw_d1[231]
 PIN tw_d1[232]
  DIRECTION INPUT ;
  USE SIGNAL ;
  PORT
   LAYER M5 ;
   RECT 232.080000 0.000000 232.104000 0.084000 ;
  END
 END tw_d1[232]
 PIN tw_d1[233]
  DIRECTION INPUT ;
  USE SIGNAL ;
  PORT
   LAYER M5 ;
   RECT 232.272000 0.000000 232.296000 0.084000 ;
  END
 END tw_d1[233]
 PIN tw_d1[234]
  DIRECTION INPUT ;
  USE SIGNAL ;
  PORT
   LAYER M5 ;
   RECT 232.464000 0.000000 232.488000 0.084000 ;
  END
 END tw_d1[234]
 PIN tw_d1[235]
  DIRECTION INPUT ;
  USE SIGNAL ;
  PORT
   LAYER M5 ;
   RECT 232.656000 0.000000 232.680000 0.084000 ;
  END
 END tw_d1[235]
 PIN tw_d1[236]
  DIRECTION INPUT ;
  USE SIGNAL ;
  PORT
   LAYER M5 ;
   RECT 232.848000 0.000000 232.872000 0.084000 ;
  END
 END tw_d1[236]
 PIN tw_d1[237]
  DIRECTION INPUT ;
  USE SIGNAL ;
  PORT
   LAYER M5 ;
   RECT 233.040000 0.000000 233.064000 0.084000 ;
  END
 END tw_d1[237]
 PIN tw_d1[238]
  DIRECTION INPUT ;
  USE SIGNAL ;
  PORT
   LAYER M5 ;
   RECT 233.232000 0.000000 233.256000 0.084000 ;
  END
 END tw_d1[238]
 PIN tw_d1[239]
  DIRECTION INPUT ;
  USE SIGNAL ;
  PORT
   LAYER M5 ;
   RECT 233.424000 0.000000 233.448000 0.084000 ;
  END
 END tw_d1[239]
 PIN tw_d1[240]
  DIRECTION INPUT ;
  USE SIGNAL ;
  PORT
   LAYER M5 ;
   RECT 233.616000 0.000000 233.640000 0.084000 ;
  END
 END tw_d1[240]
 PIN tw_d1[241]
  DIRECTION INPUT ;
  USE SIGNAL ;
  PORT
   LAYER M5 ;
   RECT 233.808000 0.000000 233.832000 0.084000 ;
  END
 END tw_d1[241]
 PIN tw_d1[242]
  DIRECTION INPUT ;
  USE SIGNAL ;
  PORT
   LAYER M5 ;
   RECT 234.000000 0.000000 234.024000 0.084000 ;
  END
 END tw_d1[242]
 PIN tw_d1[243]
  DIRECTION INPUT ;
  USE SIGNAL ;
  PORT
   LAYER M5 ;
   RECT 234.192000 0.000000 234.216000 0.084000 ;
  END
 END tw_d1[243]
 PIN tw_d1[244]
  DIRECTION INPUT ;
  USE SIGNAL ;
  PORT
   LAYER M5 ;
   RECT 234.384000 0.000000 234.408000 0.084000 ;
  END
 END tw_d1[244]
 PIN tw_d1[245]
  DIRECTION INPUT ;
  USE SIGNAL ;
  PORT
   LAYER M5 ;
   RECT 234.576000 0.000000 234.600000 0.084000 ;
  END
 END tw_d1[245]
 PIN tw_d1[246]
  DIRECTION INPUT ;
  USE SIGNAL ;
  PORT
   LAYER M5 ;
   RECT 234.768000 0.000000 234.792000 0.084000 ;
  END
 END tw_d1[246]
 PIN tw_d1[247]
  DIRECTION INPUT ;
  USE SIGNAL ;
  PORT
   LAYER M5 ;
   RECT 234.960000 0.000000 234.984000 0.084000 ;
  END
 END tw_d1[247]
 PIN tw_d1[248]
  DIRECTION INPUT ;
  USE SIGNAL ;
  PORT
   LAYER M5 ;
   RECT 235.152000 0.000000 235.176000 0.084000 ;
  END
 END tw_d1[248]
 PIN tw_d1[249]
  DIRECTION INPUT ;
  USE SIGNAL ;
  PORT
   LAYER M5 ;
   RECT 235.632000 0.000000 235.656000 0.084000 ;
  END
 END tw_d1[249]
 PIN tw_d1[250]
  DIRECTION INPUT ;
  USE SIGNAL ;
  PORT
   LAYER M5 ;
   RECT 235.824000 0.000000 235.848000 0.084000 ;
  END
 END tw_d1[250]
 PIN tw_d1[251]
  DIRECTION INPUT ;
  USE SIGNAL ;
  PORT
   LAYER M5 ;
   RECT 236.016000 0.000000 236.040000 0.084000 ;
  END
 END tw_d1[251]
 PIN tw_d1[252]
  DIRECTION INPUT ;
  USE SIGNAL ;
  PORT
   LAYER M5 ;
   RECT 236.208000 0.000000 236.232000 0.084000 ;
  END
 END tw_d1[252]
 PIN tw_d1[253]
  DIRECTION INPUT ;
  USE SIGNAL ;
  PORT
   LAYER M5 ;
   RECT 236.400000 0.000000 236.424000 0.084000 ;
  END
 END tw_d1[253]
 PIN tw_d1[254]
  DIRECTION INPUT ;
  USE SIGNAL ;
  PORT
   LAYER M5 ;
   RECT 236.592000 0.000000 236.616000 0.084000 ;
  END
 END tw_d1[254]
 PIN tw_d1[255]
  DIRECTION INPUT ;
  USE SIGNAL ;
  PORT
   LAYER M5 ;
   RECT 236.784000 0.000000 236.808000 0.084000 ;
  END
 END tw_d1[255]
 PIN tw_d1[256]
  DIRECTION INPUT ;
  USE SIGNAL ;
  PORT
   LAYER M5 ;
   RECT 236.976000 0.000000 237.000000 0.084000 ;
  END
 END tw_d1[256]
 PIN tw_d1[257]
  DIRECTION INPUT ;
  USE SIGNAL ;
  PORT
   LAYER M5 ;
   RECT 237.168000 0.000000 237.192000 0.084000 ;
  END
 END tw_d1[257]
 PIN tw_d1[258]
  DIRECTION INPUT ;
  USE SIGNAL ;
  PORT
   LAYER M5 ;
   RECT 237.360000 0.000000 237.384000 0.084000 ;
  END
 END tw_d1[258]
 PIN tw_d1[259]
  DIRECTION INPUT ;
  USE SIGNAL ;
  PORT
   LAYER M5 ;
   RECT 237.552000 0.000000 237.576000 0.084000 ;
  END
 END tw_d1[259]
 PIN tw_d1[260]
  DIRECTION INPUT ;
  USE SIGNAL ;
  PORT
   LAYER M5 ;
   RECT 237.744000 0.000000 237.768000 0.084000 ;
  END
 END tw_d1[260]
 PIN tw_d1[261]
  DIRECTION INPUT ;
  USE SIGNAL ;
  PORT
   LAYER M5 ;
   RECT 237.936000 0.000000 237.960000 0.084000 ;
  END
 END tw_d1[261]
 PIN tw_d1[262]
  DIRECTION INPUT ;
  USE SIGNAL ;
  PORT
   LAYER M5 ;
   RECT 238.128000 0.000000 238.152000 0.084000 ;
  END
 END tw_d1[262]
 PIN tw_d1[263]
  DIRECTION INPUT ;
  USE SIGNAL ;
  PORT
   LAYER M5 ;
   RECT 238.320000 0.000000 238.344000 0.084000 ;
  END
 END tw_d1[263]
 PIN tw_d1[264]
  DIRECTION INPUT ;
  USE SIGNAL ;
  PORT
   LAYER M5 ;
   RECT 238.512000 0.000000 238.536000 0.084000 ;
  END
 END tw_d1[264]
 PIN tw_d1[265]
  DIRECTION INPUT ;
  USE SIGNAL ;
  PORT
   LAYER M5 ;
   RECT 238.704000 0.000000 238.728000 0.084000 ;
  END
 END tw_d1[265]
 PIN tw_d1[266]
  DIRECTION INPUT ;
  USE SIGNAL ;
  PORT
   LAYER M5 ;
   RECT 238.896000 0.000000 238.920000 0.084000 ;
  END
 END tw_d1[266]
 PIN tw_d1[267]
  DIRECTION INPUT ;
  USE SIGNAL ;
  PORT
   LAYER M5 ;
   RECT 239.088000 0.000000 239.112000 0.084000 ;
  END
 END tw_d1[267]
 PIN tw_d1[268]
  DIRECTION INPUT ;
  USE SIGNAL ;
  PORT
   LAYER M5 ;
   RECT 239.280000 0.000000 239.304000 0.084000 ;
  END
 END tw_d1[268]
 PIN tw_d1[269]
  DIRECTION INPUT ;
  USE SIGNAL ;
  PORT
   LAYER M5 ;
   RECT 239.472000 0.000000 239.496000 0.084000 ;
  END
 END tw_d1[269]
 PIN tw_d1[270]
  DIRECTION INPUT ;
  USE SIGNAL ;
  PORT
   LAYER M5 ;
   RECT 239.952000 0.000000 239.976000 0.084000 ;
  END
 END tw_d1[270]
 PIN tw_d1[271]
  DIRECTION INPUT ;
  USE SIGNAL ;
  PORT
   LAYER M5 ;
   RECT 240.144000 0.000000 240.168000 0.084000 ;
  END
 END tw_d1[271]
 PIN tw_d1[272]
  DIRECTION INPUT ;
  USE SIGNAL ;
  PORT
   LAYER M5 ;
   RECT 240.336000 0.000000 240.360000 0.084000 ;
  END
 END tw_d1[272]
 PIN tw_d1[273]
  DIRECTION INPUT ;
  USE SIGNAL ;
  PORT
   LAYER M5 ;
   RECT 240.528000 0.000000 240.552000 0.084000 ;
  END
 END tw_d1[273]
 PIN tw_d1[274]
  DIRECTION INPUT ;
  USE SIGNAL ;
  PORT
   LAYER M5 ;
   RECT 240.720000 0.000000 240.744000 0.084000 ;
  END
 END tw_d1[274]
 PIN tw_d1[275]
  DIRECTION INPUT ;
  USE SIGNAL ;
  PORT
   LAYER M5 ;
   RECT 240.912000 0.000000 240.936000 0.084000 ;
  END
 END tw_d1[275]
 PIN tw_d1[276]
  DIRECTION INPUT ;
  USE SIGNAL ;
  PORT
   LAYER M5 ;
   RECT 241.104000 0.000000 241.128000 0.084000 ;
  END
 END tw_d1[276]
 PIN tw_d1[277]
  DIRECTION INPUT ;
  USE SIGNAL ;
  PORT
   LAYER M5 ;
   RECT 241.296000 0.000000 241.320000 0.084000 ;
  END
 END tw_d1[277]
 PIN tw_d1[278]
  DIRECTION INPUT ;
  USE SIGNAL ;
  PORT
   LAYER M5 ;
   RECT 241.488000 0.000000 241.512000 0.084000 ;
  END
 END tw_d1[278]
 PIN tw_d1[279]
  DIRECTION INPUT ;
  USE SIGNAL ;
  PORT
   LAYER M5 ;
   RECT 241.680000 0.000000 241.704000 0.084000 ;
  END
 END tw_d1[279]
 PIN tw_d1[280]
  DIRECTION INPUT ;
  USE SIGNAL ;
  PORT
   LAYER M5 ;
   RECT 241.872000 0.000000 241.896000 0.084000 ;
  END
 END tw_d1[280]
 PIN tw_d1[281]
  DIRECTION INPUT ;
  USE SIGNAL ;
  PORT
   LAYER M5 ;
   RECT 242.064000 0.000000 242.088000 0.084000 ;
  END
 END tw_d1[281]
 PIN tw_d1[282]
  DIRECTION INPUT ;
  USE SIGNAL ;
  PORT
   LAYER M5 ;
   RECT 242.256000 0.000000 242.280000 0.084000 ;
  END
 END tw_d1[282]
 PIN tw_d1[283]
  DIRECTION INPUT ;
  USE SIGNAL ;
  PORT
   LAYER M5 ;
   RECT 242.448000 0.000000 242.472000 0.084000 ;
  END
 END tw_d1[283]
 PIN tw_d1[284]
  DIRECTION INPUT ;
  USE SIGNAL ;
  PORT
   LAYER M5 ;
   RECT 242.640000 0.000000 242.664000 0.084000 ;
  END
 END tw_d1[284]
 PIN tw_d1[285]
  DIRECTION INPUT ;
  USE SIGNAL ;
  PORT
   LAYER M5 ;
   RECT 242.832000 0.000000 242.856000 0.084000 ;
  END
 END tw_d1[285]
 PIN tw_d1[286]
  DIRECTION INPUT ;
  USE SIGNAL ;
  PORT
   LAYER M5 ;
   RECT 243.024000 0.000000 243.048000 0.084000 ;
  END
 END tw_d1[286]
 PIN tw_d1[287]
  DIRECTION INPUT ;
  USE SIGNAL ;
  PORT
   LAYER M5 ;
   RECT 243.216000 0.000000 243.240000 0.084000 ;
  END
 END tw_d1[287]
 PIN tw_d1[288]
  DIRECTION INPUT ;
  USE SIGNAL ;
  PORT
   LAYER M5 ;
   RECT 243.408000 0.000000 243.432000 0.084000 ;
  END
 END tw_d1[288]
 PIN tw_d1[289]
  DIRECTION INPUT ;
  USE SIGNAL ;
  PORT
   LAYER M5 ;
   RECT 243.600000 0.000000 243.624000 0.084000 ;
  END
 END tw_d1[289]
 PIN tw_d1[290]
  DIRECTION INPUT ;
  USE SIGNAL ;
  PORT
   LAYER M5 ;
   RECT 243.792000 0.000000 243.816000 0.084000 ;
  END
 END tw_d1[290]
 PIN tw_d1[291]
  DIRECTION INPUT ;
  USE SIGNAL ;
  PORT
   LAYER M5 ;
   RECT 244.272000 0.000000 244.296000 0.084000 ;
  END
 END tw_d1[291]
 PIN tw_d1[292]
  DIRECTION INPUT ;
  USE SIGNAL ;
  PORT
   LAYER M5 ;
   RECT 244.464000 0.000000 244.488000 0.084000 ;
  END
 END tw_d1[292]
 PIN tw_d1[293]
  DIRECTION INPUT ;
  USE SIGNAL ;
  PORT
   LAYER M5 ;
   RECT 244.656000 0.000000 244.680000 0.084000 ;
  END
 END tw_d1[293]
 PIN tw_d1[294]
  DIRECTION INPUT ;
  USE SIGNAL ;
  PORT
   LAYER M5 ;
   RECT 244.848000 0.000000 244.872000 0.084000 ;
  END
 END tw_d1[294]
 PIN tw_d1[295]
  DIRECTION INPUT ;
  USE SIGNAL ;
  PORT
   LAYER M5 ;
   RECT 245.040000 0.000000 245.064000 0.084000 ;
  END
 END tw_d1[295]
 PIN tw_d1[296]
  DIRECTION INPUT ;
  USE SIGNAL ;
  PORT
   LAYER M5 ;
   RECT 245.232000 0.000000 245.256000 0.084000 ;
  END
 END tw_d1[296]
 PIN tw_d1[297]
  DIRECTION INPUT ;
  USE SIGNAL ;
  PORT
   LAYER M5 ;
   RECT 245.424000 0.000000 245.448000 0.084000 ;
  END
 END tw_d1[297]
 PIN tw_d1[298]
  DIRECTION INPUT ;
  USE SIGNAL ;
  PORT
   LAYER M5 ;
   RECT 245.616000 0.000000 245.640000 0.084000 ;
  END
 END tw_d1[298]
 PIN tw_d1[299]
  DIRECTION INPUT ;
  USE SIGNAL ;
  PORT
   LAYER M5 ;
   RECT 245.808000 0.000000 245.832000 0.084000 ;
  END
 END tw_d1[299]
 PIN tw_d1[300]
  DIRECTION INPUT ;
  USE SIGNAL ;
  PORT
   LAYER M5 ;
   RECT 246.000000 0.000000 246.024000 0.084000 ;
  END
 END tw_d1[300]
 PIN tw_d1[301]
  DIRECTION INPUT ;
  USE SIGNAL ;
  PORT
   LAYER M5 ;
   RECT 246.192000 0.000000 246.216000 0.084000 ;
  END
 END tw_d1[301]
 PIN tw_d1[302]
  DIRECTION INPUT ;
  USE SIGNAL ;
  PORT
   LAYER M5 ;
   RECT 246.384000 0.000000 246.408000 0.084000 ;
  END
 END tw_d1[302]
 PIN tw_d1[303]
  DIRECTION INPUT ;
  USE SIGNAL ;
  PORT
   LAYER M5 ;
   RECT 246.576000 0.000000 246.600000 0.084000 ;
  END
 END tw_d1[303]
 PIN tw_d1[304]
  DIRECTION INPUT ;
  USE SIGNAL ;
  PORT
   LAYER M5 ;
   RECT 246.768000 0.000000 246.792000 0.084000 ;
  END
 END tw_d1[304]
 PIN tw_d1[305]
  DIRECTION INPUT ;
  USE SIGNAL ;
  PORT
   LAYER M5 ;
   RECT 246.960000 0.000000 246.984000 0.084000 ;
  END
 END tw_d1[305]
 PIN tw_d1[306]
  DIRECTION INPUT ;
  USE SIGNAL ;
  PORT
   LAYER M5 ;
   RECT 247.152000 0.000000 247.176000 0.084000 ;
  END
 END tw_d1[306]
 PIN tw_d1[307]
  DIRECTION INPUT ;
  USE SIGNAL ;
  PORT
   LAYER M5 ;
   RECT 247.344000 0.000000 247.368000 0.084000 ;
  END
 END tw_d1[307]
 PIN tw_d1[308]
  DIRECTION INPUT ;
  USE SIGNAL ;
  PORT
   LAYER M5 ;
   RECT 247.536000 0.000000 247.560000 0.084000 ;
  END
 END tw_d1[308]
 PIN tw_d1[309]
  DIRECTION INPUT ;
  USE SIGNAL ;
  PORT
   LAYER M5 ;
   RECT 247.728000 0.000000 247.752000 0.084000 ;
  END
 END tw_d1[309]
 PIN tw_d1[310]
  DIRECTION INPUT ;
  USE SIGNAL ;
  PORT
   LAYER M5 ;
   RECT 247.920000 0.000000 247.944000 0.084000 ;
  END
 END tw_d1[310]
 PIN tw_d1[311]
  DIRECTION INPUT ;
  USE SIGNAL ;
  PORT
   LAYER M5 ;
   RECT 248.112000 0.000000 248.136000 0.084000 ;
  END
 END tw_d1[311]
 PIN tw_d1[312]
  DIRECTION INPUT ;
  USE SIGNAL ;
  PORT
   LAYER M5 ;
   RECT 248.592000 0.000000 248.616000 0.084000 ;
  END
 END tw_d1[312]
 PIN tw_d1[313]
  DIRECTION INPUT ;
  USE SIGNAL ;
  PORT
   LAYER M5 ;
   RECT 248.784000 0.000000 248.808000 0.084000 ;
  END
 END tw_d1[313]
 PIN tw_d1[314]
  DIRECTION INPUT ;
  USE SIGNAL ;
  PORT
   LAYER M5 ;
   RECT 248.976000 0.000000 249.000000 0.084000 ;
  END
 END tw_d1[314]
 PIN tw_d1[315]
  DIRECTION INPUT ;
  USE SIGNAL ;
  PORT
   LAYER M5 ;
   RECT 249.168000 0.000000 249.192000 0.084000 ;
  END
 END tw_d1[315]
 PIN tw_d1[316]
  DIRECTION INPUT ;
  USE SIGNAL ;
  PORT
   LAYER M5 ;
   RECT 249.360000 0.000000 249.384000 0.084000 ;
  END
 END tw_d1[316]
 PIN tw_d1[317]
  DIRECTION INPUT ;
  USE SIGNAL ;
  PORT
   LAYER M5 ;
   RECT 249.552000 0.000000 249.576000 0.084000 ;
  END
 END tw_d1[317]
 PIN tw_d1[318]
  DIRECTION INPUT ;
  USE SIGNAL ;
  PORT
   LAYER M5 ;
   RECT 249.744000 0.000000 249.768000 0.084000 ;
  END
 END tw_d1[318]
 PIN tw_d1[319]
  DIRECTION INPUT ;
  USE SIGNAL ;
  PORT
   LAYER M5 ;
   RECT 249.936000 0.000000 249.960000 0.084000 ;
  END
 END tw_d1[319]
 PIN tw_d1[320]
  DIRECTION INPUT ;
  USE SIGNAL ;
  PORT
   LAYER M5 ;
   RECT 250.128000 0.000000 250.152000 0.084000 ;
  END
 END tw_d1[320]
 PIN tw_d1[321]
  DIRECTION INPUT ;
  USE SIGNAL ;
  PORT
   LAYER M5 ;
   RECT 250.320000 0.000000 250.344000 0.084000 ;
  END
 END tw_d1[321]
 PIN tw_d1[322]
  DIRECTION INPUT ;
  USE SIGNAL ;
  PORT
   LAYER M5 ;
   RECT 250.512000 0.000000 250.536000 0.084000 ;
  END
 END tw_d1[322]
 PIN tw_d1[323]
  DIRECTION INPUT ;
  USE SIGNAL ;
  PORT
   LAYER M5 ;
   RECT 250.704000 0.000000 250.728000 0.084000 ;
  END
 END tw_d1[323]
 PIN tw_d1[324]
  DIRECTION INPUT ;
  USE SIGNAL ;
  PORT
   LAYER M5 ;
   RECT 250.896000 0.000000 250.920000 0.084000 ;
  END
 END tw_d1[324]
 PIN tw_d1[325]
  DIRECTION INPUT ;
  USE SIGNAL ;
  PORT
   LAYER M5 ;
   RECT 251.088000 0.000000 251.112000 0.084000 ;
  END
 END tw_d1[325]
 PIN tw_d1[326]
  DIRECTION INPUT ;
  USE SIGNAL ;
  PORT
   LAYER M5 ;
   RECT 251.280000 0.000000 251.304000 0.084000 ;
  END
 END tw_d1[326]
 PIN tw_d1[327]
  DIRECTION INPUT ;
  USE SIGNAL ;
  PORT
   LAYER M5 ;
   RECT 251.472000 0.000000 251.496000 0.084000 ;
  END
 END tw_d1[327]
 PIN tw_d1[328]
  DIRECTION INPUT ;
  USE SIGNAL ;
  PORT
   LAYER M5 ;
   RECT 251.664000 0.000000 251.688000 0.084000 ;
  END
 END tw_d1[328]
 PIN tw_d1[329]
  DIRECTION INPUT ;
  USE SIGNAL ;
  PORT
   LAYER M5 ;
   RECT 251.856000 0.000000 251.880000 0.084000 ;
  END
 END tw_d1[329]
 PIN tw_d1[330]
  DIRECTION INPUT ;
  USE SIGNAL ;
  PORT
   LAYER M5 ;
   RECT 252.048000 0.000000 252.072000 0.084000 ;
  END
 END tw_d1[330]
 PIN tw_d1[331]
  DIRECTION INPUT ;
  USE SIGNAL ;
  PORT
   LAYER M5 ;
   RECT 252.240000 0.000000 252.264000 0.084000 ;
  END
 END tw_d1[331]
 PIN tw_d1[332]
  DIRECTION INPUT ;
  USE SIGNAL ;
  PORT
   LAYER M5 ;
   RECT 252.432000 0.000000 252.456000 0.084000 ;
  END
 END tw_d1[332]
 PIN tw_d1[333]
  DIRECTION INPUT ;
  USE SIGNAL ;
  PORT
   LAYER M5 ;
   RECT 252.912000 0.000000 252.936000 0.084000 ;
  END
 END tw_d1[333]
 PIN tw_d1[334]
  DIRECTION INPUT ;
  USE SIGNAL ;
  PORT
   LAYER M5 ;
   RECT 253.104000 0.000000 253.128000 0.084000 ;
  END
 END tw_d1[334]
 PIN tw_d1[335]
  DIRECTION INPUT ;
  USE SIGNAL ;
  PORT
   LAYER M5 ;
   RECT 253.296000 0.000000 253.320000 0.084000 ;
  END
 END tw_d1[335]
 PIN tw_d1[336]
  DIRECTION INPUT ;
  USE SIGNAL ;
  PORT
   LAYER M5 ;
   RECT 253.488000 0.000000 253.512000 0.084000 ;
  END
 END tw_d1[336]
 PIN tw_d1[337]
  DIRECTION INPUT ;
  USE SIGNAL ;
  PORT
   LAYER M5 ;
   RECT 253.680000 0.000000 253.704000 0.084000 ;
  END
 END tw_d1[337]
 PIN tw_d1[338]
  DIRECTION INPUT ;
  USE SIGNAL ;
  PORT
   LAYER M5 ;
   RECT 253.872000 0.000000 253.896000 0.084000 ;
  END
 END tw_d1[338]
 PIN tw_d1[339]
  DIRECTION INPUT ;
  USE SIGNAL ;
  PORT
   LAYER M5 ;
   RECT 254.064000 0.000000 254.088000 0.084000 ;
  END
 END tw_d1[339]
 PIN tw_d1[340]
  DIRECTION INPUT ;
  USE SIGNAL ;
  PORT
   LAYER M5 ;
   RECT 254.256000 0.000000 254.280000 0.084000 ;
  END
 END tw_d1[340]
 PIN tw_d1[341]
  DIRECTION INPUT ;
  USE SIGNAL ;
  PORT
   LAYER M5 ;
   RECT 254.448000 0.000000 254.472000 0.084000 ;
  END
 END tw_d1[341]
 PIN tw_d1[342]
  DIRECTION INPUT ;
  USE SIGNAL ;
  PORT
   LAYER M5 ;
   RECT 254.640000 0.000000 254.664000 0.084000 ;
  END
 END tw_d1[342]
 PIN tw_d1[343]
  DIRECTION INPUT ;
  USE SIGNAL ;
  PORT
   LAYER M5 ;
   RECT 254.832000 0.000000 254.856000 0.084000 ;
  END
 END tw_d1[343]
 PIN tw_d1[344]
  DIRECTION INPUT ;
  USE SIGNAL ;
  PORT
   LAYER M5 ;
   RECT 255.024000 0.000000 255.048000 0.084000 ;
  END
 END tw_d1[344]
 PIN tw_d1[345]
  DIRECTION INPUT ;
  USE SIGNAL ;
  PORT
   LAYER M5 ;
   RECT 255.216000 0.000000 255.240000 0.084000 ;
  END
 END tw_d1[345]
 PIN tw_d1[346]
  DIRECTION INPUT ;
  USE SIGNAL ;
  PORT
   LAYER M5 ;
   RECT 255.408000 0.000000 255.432000 0.084000 ;
  END
 END tw_d1[346]
 PIN tw_d1[347]
  DIRECTION INPUT ;
  USE SIGNAL ;
  PORT
   LAYER M5 ;
   RECT 255.600000 0.000000 255.624000 0.084000 ;
  END
 END tw_d1[347]
 PIN tw_d1[348]
  DIRECTION INPUT ;
  USE SIGNAL ;
  PORT
   LAYER M5 ;
   RECT 255.792000 0.000000 255.816000 0.084000 ;
  END
 END tw_d1[348]
 PIN tw_d1[349]
  DIRECTION INPUT ;
  USE SIGNAL ;
  PORT
   LAYER M5 ;
   RECT 255.984000 0.000000 256.008000 0.084000 ;
  END
 END tw_d1[349]
 PIN tw_d1[350]
  DIRECTION INPUT ;
  USE SIGNAL ;
  PORT
   LAYER M5 ;
   RECT 256.176000 0.000000 256.200000 0.084000 ;
  END
 END tw_d1[350]
 PIN tw_d1[351]
  DIRECTION INPUT ;
  USE SIGNAL ;
  PORT
   LAYER M5 ;
   RECT 256.368000 0.000000 256.392000 0.084000 ;
  END
 END tw_d1[351]
 PIN tw_d1[352]
  DIRECTION INPUT ;
  USE SIGNAL ;
  PORT
   LAYER M5 ;
   RECT 256.560000 0.000000 256.584000 0.084000 ;
  END
 END tw_d1[352]
 PIN tw_d1[353]
  DIRECTION INPUT ;
  USE SIGNAL ;
  PORT
   LAYER M5 ;
   RECT 256.752000 0.000000 256.776000 0.084000 ;
  END
 END tw_d1[353]
 PIN tw_d1[354]
  DIRECTION INPUT ;
  USE SIGNAL ;
  PORT
   LAYER M5 ;
   RECT 257.232000 0.000000 257.256000 0.084000 ;
  END
 END tw_d1[354]
 PIN tw_d1[355]
  DIRECTION INPUT ;
  USE SIGNAL ;
  PORT
   LAYER M5 ;
   RECT 257.424000 0.000000 257.448000 0.084000 ;
  END
 END tw_d1[355]
 PIN tw_d1[356]
  DIRECTION INPUT ;
  USE SIGNAL ;
  PORT
   LAYER M5 ;
   RECT 257.616000 0.000000 257.640000 0.084000 ;
  END
 END tw_d1[356]
 PIN tw_d1[357]
  DIRECTION INPUT ;
  USE SIGNAL ;
  PORT
   LAYER M5 ;
   RECT 257.808000 0.000000 257.832000 0.084000 ;
  END
 END tw_d1[357]
 PIN tw_d1[358]
  DIRECTION INPUT ;
  USE SIGNAL ;
  PORT
   LAYER M5 ;
   RECT 258.000000 0.000000 258.024000 0.084000 ;
  END
 END tw_d1[358]
 PIN tw_d1[359]
  DIRECTION INPUT ;
  USE SIGNAL ;
  PORT
   LAYER M5 ;
   RECT 258.192000 0.000000 258.216000 0.084000 ;
  END
 END tw_d1[359]
 PIN tw_d1[360]
  DIRECTION INPUT ;
  USE SIGNAL ;
  PORT
   LAYER M5 ;
   RECT 258.384000 0.000000 258.408000 0.084000 ;
  END
 END tw_d1[360]
 PIN tw_d1[361]
  DIRECTION INPUT ;
  USE SIGNAL ;
  PORT
   LAYER M5 ;
   RECT 258.576000 0.000000 258.600000 0.084000 ;
  END
 END tw_d1[361]
 PIN tw_d1[362]
  DIRECTION INPUT ;
  USE SIGNAL ;
  PORT
   LAYER M5 ;
   RECT 258.768000 0.000000 258.792000 0.084000 ;
  END
 END tw_d1[362]
 PIN tw_d1[363]
  DIRECTION INPUT ;
  USE SIGNAL ;
  PORT
   LAYER M5 ;
   RECT 258.960000 0.000000 258.984000 0.084000 ;
  END
 END tw_d1[363]
 PIN tw_d1[364]
  DIRECTION INPUT ;
  USE SIGNAL ;
  PORT
   LAYER M5 ;
   RECT 259.152000 0.000000 259.176000 0.084000 ;
  END
 END tw_d1[364]
 PIN tw_d1[365]
  DIRECTION INPUT ;
  USE SIGNAL ;
  PORT
   LAYER M5 ;
   RECT 259.344000 0.000000 259.368000 0.084000 ;
  END
 END tw_d1[365]
 PIN tw_d1[366]
  DIRECTION INPUT ;
  USE SIGNAL ;
  PORT
   LAYER M5 ;
   RECT 259.536000 0.000000 259.560000 0.084000 ;
  END
 END tw_d1[366]
 PIN tw_d1[367]
  DIRECTION INPUT ;
  USE SIGNAL ;
  PORT
   LAYER M5 ;
   RECT 259.728000 0.000000 259.752000 0.084000 ;
  END
 END tw_d1[367]
 PIN tw_d1[368]
  DIRECTION INPUT ;
  USE SIGNAL ;
  PORT
   LAYER M5 ;
   RECT 259.920000 0.000000 259.944000 0.084000 ;
  END
 END tw_d1[368]
 PIN tw_d1[369]
  DIRECTION INPUT ;
  USE SIGNAL ;
  PORT
   LAYER M5 ;
   RECT 260.112000 0.000000 260.136000 0.084000 ;
  END
 END tw_d1[369]
 PIN tw_d1[370]
  DIRECTION INPUT ;
  USE SIGNAL ;
  PORT
   LAYER M5 ;
   RECT 260.304000 0.000000 260.328000 0.084000 ;
  END
 END tw_d1[370]
 PIN tw_d1[371]
  DIRECTION INPUT ;
  USE SIGNAL ;
  PORT
   LAYER M5 ;
   RECT 260.496000 0.000000 260.520000 0.084000 ;
  END
 END tw_d1[371]
 PIN tw_d1[372]
  DIRECTION INPUT ;
  USE SIGNAL ;
  PORT
   LAYER M5 ;
   RECT 260.688000 0.000000 260.712000 0.084000 ;
  END
 END tw_d1[372]
 PIN tw_d1[373]
  DIRECTION INPUT ;
  USE SIGNAL ;
  PORT
   LAYER M5 ;
   RECT 260.880000 0.000000 260.904000 0.084000 ;
  END
 END tw_d1[373]
 PIN tw_d1[374]
  DIRECTION INPUT ;
  USE SIGNAL ;
  PORT
   LAYER M5 ;
   RECT 261.072000 0.000000 261.096000 0.084000 ;
  END
 END tw_d1[374]
 PIN tw_d1[375]
  DIRECTION INPUT ;
  USE SIGNAL ;
  PORT
   LAYER M5 ;
   RECT 261.552000 0.000000 261.576000 0.084000 ;
  END
 END tw_d1[375]
 PIN tw_d1[376]
  DIRECTION INPUT ;
  USE SIGNAL ;
  PORT
   LAYER M5 ;
   RECT 261.744000 0.000000 261.768000 0.084000 ;
  END
 END tw_d1[376]
 PIN tw_d1[377]
  DIRECTION INPUT ;
  USE SIGNAL ;
  PORT
   LAYER M5 ;
   RECT 261.936000 0.000000 261.960000 0.084000 ;
  END
 END tw_d1[377]
 PIN tw_d1[378]
  DIRECTION INPUT ;
  USE SIGNAL ;
  PORT
   LAYER M5 ;
   RECT 262.128000 0.000000 262.152000 0.084000 ;
  END
 END tw_d1[378]
 PIN tw_d1[379]
  DIRECTION INPUT ;
  USE SIGNAL ;
  PORT
   LAYER M5 ;
   RECT 262.320000 0.000000 262.344000 0.084000 ;
  END
 END tw_d1[379]
 PIN tw_d1[380]
  DIRECTION INPUT ;
  USE SIGNAL ;
  PORT
   LAYER M5 ;
   RECT 262.512000 0.000000 262.536000 0.084000 ;
  END
 END tw_d1[380]
 PIN tw_d1[381]
  DIRECTION INPUT ;
  USE SIGNAL ;
  PORT
   LAYER M5 ;
   RECT 262.704000 0.000000 262.728000 0.084000 ;
  END
 END tw_d1[381]
 PIN tw_d1[382]
  DIRECTION INPUT ;
  USE SIGNAL ;
  PORT
   LAYER M5 ;
   RECT 262.896000 0.000000 262.920000 0.084000 ;
  END
 END tw_d1[382]
 PIN tw_d1[383]
  DIRECTION INPUT ;
  USE SIGNAL ;
  PORT
   LAYER M5 ;
   RECT 263.088000 0.000000 263.112000 0.084000 ;
  END
 END tw_d1[383]
 PIN tw_d1[384]
  DIRECTION INPUT ;
  USE SIGNAL ;
  PORT
   LAYER M5 ;
   RECT 263.280000 0.000000 263.304000 0.084000 ;
  END
 END tw_d1[384]
 PIN tw_d1[385]
  DIRECTION INPUT ;
  USE SIGNAL ;
  PORT
   LAYER M5 ;
   RECT 263.472000 0.000000 263.496000 0.084000 ;
  END
 END tw_d1[385]
 PIN tw_d1[386]
  DIRECTION INPUT ;
  USE SIGNAL ;
  PORT
   LAYER M5 ;
   RECT 263.664000 0.000000 263.688000 0.084000 ;
  END
 END tw_d1[386]
 PIN tw_d1[387]
  DIRECTION INPUT ;
  USE SIGNAL ;
  PORT
   LAYER M5 ;
   RECT 263.856000 0.000000 263.880000 0.084000 ;
  END
 END tw_d1[387]
 PIN tw_d1[388]
  DIRECTION INPUT ;
  USE SIGNAL ;
  PORT
   LAYER M5 ;
   RECT 264.048000 0.000000 264.072000 0.084000 ;
  END
 END tw_d1[388]
 PIN tw_d1[389]
  DIRECTION INPUT ;
  USE SIGNAL ;
  PORT
   LAYER M5 ;
   RECT 264.240000 0.000000 264.264000 0.084000 ;
  END
 END tw_d1[389]
 PIN tw_d1[390]
  DIRECTION INPUT ;
  USE SIGNAL ;
  PORT
   LAYER M5 ;
   RECT 264.432000 0.000000 264.456000 0.084000 ;
  END
 END tw_d1[390]
 PIN tw_d1[391]
  DIRECTION INPUT ;
  USE SIGNAL ;
  PORT
   LAYER M5 ;
   RECT 264.624000 0.000000 264.648000 0.084000 ;
  END
 END tw_d1[391]
 PIN tw_d1[392]
  DIRECTION INPUT ;
  USE SIGNAL ;
  PORT
   LAYER M5 ;
   RECT 264.816000 0.000000 264.840000 0.084000 ;
  END
 END tw_d1[392]
 PIN tw_d1[393]
  DIRECTION INPUT ;
  USE SIGNAL ;
  PORT
   LAYER M5 ;
   RECT 265.008000 0.000000 265.032000 0.084000 ;
  END
 END tw_d1[393]
 PIN tw_d1[394]
  DIRECTION INPUT ;
  USE SIGNAL ;
  PORT
   LAYER M5 ;
   RECT 265.200000 0.000000 265.224000 0.084000 ;
  END
 END tw_d1[394]
 PIN tw_d1[395]
  DIRECTION INPUT ;
  USE SIGNAL ;
  PORT
   LAYER M5 ;
   RECT 265.392000 0.000000 265.416000 0.084000 ;
  END
 END tw_d1[395]
 PIN tw_d1[396]
  DIRECTION INPUT ;
  USE SIGNAL ;
  PORT
   LAYER M5 ;
   RECT 265.872000 0.000000 265.896000 0.084000 ;
  END
 END tw_d1[396]
 PIN tw_d1[397]
  DIRECTION INPUT ;
  USE SIGNAL ;
  PORT
   LAYER M5 ;
   RECT 266.064000 0.000000 266.088000 0.084000 ;
  END
 END tw_d1[397]
 PIN tw_d1[398]
  DIRECTION INPUT ;
  USE SIGNAL ;
  PORT
   LAYER M5 ;
   RECT 266.256000 0.000000 266.280000 0.084000 ;
  END
 END tw_d1[398]
 PIN tw_d1[399]
  DIRECTION INPUT ;
  USE SIGNAL ;
  PORT
   LAYER M5 ;
   RECT 266.448000 0.000000 266.472000 0.084000 ;
  END
 END tw_d1[399]
 PIN tw_d1[400]
  DIRECTION INPUT ;
  USE SIGNAL ;
  PORT
   LAYER M5 ;
   RECT 266.640000 0.000000 266.664000 0.084000 ;
  END
 END tw_d1[400]
 PIN tw_d1[401]
  DIRECTION INPUT ;
  USE SIGNAL ;
  PORT
   LAYER M5 ;
   RECT 266.832000 0.000000 266.856000 0.084000 ;
  END
 END tw_d1[401]
 PIN tw_d1[402]
  DIRECTION INPUT ;
  USE SIGNAL ;
  PORT
   LAYER M5 ;
   RECT 267.024000 0.000000 267.048000 0.084000 ;
  END
 END tw_d1[402]
 PIN tw_d1[403]
  DIRECTION INPUT ;
  USE SIGNAL ;
  PORT
   LAYER M5 ;
   RECT 267.216000 0.000000 267.240000 0.084000 ;
  END
 END tw_d1[403]
 PIN tw_d1[404]
  DIRECTION INPUT ;
  USE SIGNAL ;
  PORT
   LAYER M5 ;
   RECT 267.408000 0.000000 267.432000 0.084000 ;
  END
 END tw_d1[404]
 PIN tw_d1[405]
  DIRECTION INPUT ;
  USE SIGNAL ;
  PORT
   LAYER M5 ;
   RECT 267.600000 0.000000 267.624000 0.084000 ;
  END
 END tw_d1[405]
 PIN tw_d1[406]
  DIRECTION INPUT ;
  USE SIGNAL ;
  PORT
   LAYER M5 ;
   RECT 267.792000 0.000000 267.816000 0.084000 ;
  END
 END tw_d1[406]
 PIN tw_d1[407]
  DIRECTION INPUT ;
  USE SIGNAL ;
  PORT
   LAYER M5 ;
   RECT 267.984000 0.000000 268.008000 0.084000 ;
  END
 END tw_d1[407]
 PIN tw_d1[408]
  DIRECTION INPUT ;
  USE SIGNAL ;
  PORT
   LAYER M5 ;
   RECT 268.176000 0.000000 268.200000 0.084000 ;
  END
 END tw_d1[408]
 PIN tw_d1[409]
  DIRECTION INPUT ;
  USE SIGNAL ;
  PORT
   LAYER M5 ;
   RECT 268.368000 0.000000 268.392000 0.084000 ;
  END
 END tw_d1[409]
 PIN tw_d1[410]
  DIRECTION INPUT ;
  USE SIGNAL ;
  PORT
   LAYER M5 ;
   RECT 268.560000 0.000000 268.584000 0.084000 ;
  END
 END tw_d1[410]
 PIN tw_d1[411]
  DIRECTION INPUT ;
  USE SIGNAL ;
  PORT
   LAYER M5 ;
   RECT 268.752000 0.000000 268.776000 0.084000 ;
  END
 END tw_d1[411]
 PIN tw_d1[412]
  DIRECTION INPUT ;
  USE SIGNAL ;
  PORT
   LAYER M5 ;
   RECT 268.944000 0.000000 268.968000 0.084000 ;
  END
 END tw_d1[412]
 PIN tw_d1[413]
  DIRECTION INPUT ;
  USE SIGNAL ;
  PORT
   LAYER M5 ;
   RECT 269.136000 0.000000 269.160000 0.084000 ;
  END
 END tw_d1[413]
 PIN tw_d1[414]
  DIRECTION INPUT ;
  USE SIGNAL ;
  PORT
   LAYER M5 ;
   RECT 269.328000 0.000000 269.352000 0.084000 ;
  END
 END tw_d1[414]
 PIN tw_d1[415]
  DIRECTION INPUT ;
  USE SIGNAL ;
  PORT
   LAYER M5 ;
   RECT 269.520000 0.000000 269.544000 0.084000 ;
  END
 END tw_d1[415]
 PIN tw_d1[416]
  DIRECTION INPUT ;
  USE SIGNAL ;
  PORT
   LAYER M5 ;
   RECT 269.712000 0.000000 269.736000 0.084000 ;
  END
 END tw_d1[416]
 PIN tw_d1[417]
  DIRECTION INPUT ;
  USE SIGNAL ;
  PORT
   LAYER M5 ;
   RECT 270.192000 0.000000 270.216000 0.084000 ;
  END
 END tw_d1[417]
 PIN tw_d1[418]
  DIRECTION INPUT ;
  USE SIGNAL ;
  PORT
   LAYER M5 ;
   RECT 270.384000 0.000000 270.408000 0.084000 ;
  END
 END tw_d1[418]
 PIN tw_d1[419]
  DIRECTION INPUT ;
  USE SIGNAL ;
  PORT
   LAYER M5 ;
   RECT 270.576000 0.000000 270.600000 0.084000 ;
  END
 END tw_d1[419]
 PIN tw_d1[420]
  DIRECTION INPUT ;
  USE SIGNAL ;
  PORT
   LAYER M5 ;
   RECT 270.768000 0.000000 270.792000 0.084000 ;
  END
 END tw_d1[420]
 PIN tw_d1[421]
  DIRECTION INPUT ;
  USE SIGNAL ;
  PORT
   LAYER M5 ;
   RECT 270.960000 0.000000 270.984000 0.084000 ;
  END
 END tw_d1[421]
 PIN tw_d1[422]
  DIRECTION INPUT ;
  USE SIGNAL ;
  PORT
   LAYER M5 ;
   RECT 271.152000 0.000000 271.176000 0.084000 ;
  END
 END tw_d1[422]
 PIN tw_d1[423]
  DIRECTION INPUT ;
  USE SIGNAL ;
  PORT
   LAYER M5 ;
   RECT 271.344000 0.000000 271.368000 0.084000 ;
  END
 END tw_d1[423]
 PIN tw_d1[424]
  DIRECTION INPUT ;
  USE SIGNAL ;
  PORT
   LAYER M5 ;
   RECT 271.536000 0.000000 271.560000 0.084000 ;
  END
 END tw_d1[424]
 PIN tw_d1[425]
  DIRECTION INPUT ;
  USE SIGNAL ;
  PORT
   LAYER M5 ;
   RECT 271.728000 0.000000 271.752000 0.084000 ;
  END
 END tw_d1[425]
 PIN tw_d1[426]
  DIRECTION INPUT ;
  USE SIGNAL ;
  PORT
   LAYER M5 ;
   RECT 271.920000 0.000000 271.944000 0.084000 ;
  END
 END tw_d1[426]
 PIN tw_d1[427]
  DIRECTION INPUT ;
  USE SIGNAL ;
  PORT
   LAYER M5 ;
   RECT 272.112000 0.000000 272.136000 0.084000 ;
  END
 END tw_d1[427]
 PIN tw_d1[428]
  DIRECTION INPUT ;
  USE SIGNAL ;
  PORT
   LAYER M5 ;
   RECT 272.304000 0.000000 272.328000 0.084000 ;
  END
 END tw_d1[428]
 PIN tw_d1[429]
  DIRECTION INPUT ;
  USE SIGNAL ;
  PORT
   LAYER M5 ;
   RECT 272.496000 0.000000 272.520000 0.084000 ;
  END
 END tw_d1[429]
 PIN tw_d1[430]
  DIRECTION INPUT ;
  USE SIGNAL ;
  PORT
   LAYER M5 ;
   RECT 272.688000 0.000000 272.712000 0.084000 ;
  END
 END tw_d1[430]
 PIN tw_d1[431]
  DIRECTION INPUT ;
  USE SIGNAL ;
  PORT
   LAYER M5 ;
   RECT 272.880000 0.000000 272.904000 0.084000 ;
  END
 END tw_d1[431]
 PIN tw_d1[432]
  DIRECTION INPUT ;
  USE SIGNAL ;
  PORT
   LAYER M5 ;
   RECT 273.072000 0.000000 273.096000 0.084000 ;
  END
 END tw_d1[432]
 PIN tw_d1[433]
  DIRECTION INPUT ;
  USE SIGNAL ;
  PORT
   LAYER M5 ;
   RECT 273.264000 0.000000 273.288000 0.084000 ;
  END
 END tw_d1[433]
 PIN tw_d1[434]
  DIRECTION INPUT ;
  USE SIGNAL ;
  PORT
   LAYER M5 ;
   RECT 273.456000 0.000000 273.480000 0.084000 ;
  END
 END tw_d1[434]
 PIN tw_d1[435]
  DIRECTION INPUT ;
  USE SIGNAL ;
  PORT
   LAYER M5 ;
   RECT 273.648000 0.000000 273.672000 0.084000 ;
  END
 END tw_d1[435]
 PIN tw_d1[436]
  DIRECTION INPUT ;
  USE SIGNAL ;
  PORT
   LAYER M5 ;
   RECT 273.840000 0.000000 273.864000 0.084000 ;
  END
 END tw_d1[436]
 PIN tw_d1[437]
  DIRECTION INPUT ;
  USE SIGNAL ;
  PORT
   LAYER M5 ;
   RECT 274.032000 0.000000 274.056000 0.084000 ;
  END
 END tw_d1[437]
 PIN tw_d1[438]
  DIRECTION INPUT ;
  USE SIGNAL ;
  PORT
   LAYER M5 ;
   RECT 274.512000 0.000000 274.536000 0.084000 ;
  END
 END tw_d1[438]
 PIN tw_d1[439]
  DIRECTION INPUT ;
  USE SIGNAL ;
  PORT
   LAYER M5 ;
   RECT 274.704000 0.000000 274.728000 0.084000 ;
  END
 END tw_d1[439]
 PIN tw_d1[440]
  DIRECTION INPUT ;
  USE SIGNAL ;
  PORT
   LAYER M5 ;
   RECT 274.896000 0.000000 274.920000 0.084000 ;
  END
 END tw_d1[440]
 PIN tw_d1[441]
  DIRECTION INPUT ;
  USE SIGNAL ;
  PORT
   LAYER M5 ;
   RECT 275.088000 0.000000 275.112000 0.084000 ;
  END
 END tw_d1[441]
 PIN tw_d1[442]
  DIRECTION INPUT ;
  USE SIGNAL ;
  PORT
   LAYER M5 ;
   RECT 275.280000 0.000000 275.304000 0.084000 ;
  END
 END tw_d1[442]
 PIN tw_d1[443]
  DIRECTION INPUT ;
  USE SIGNAL ;
  PORT
   LAYER M5 ;
   RECT 275.472000 0.000000 275.496000 0.084000 ;
  END
 END tw_d1[443]
 PIN tw_d1[444]
  DIRECTION INPUT ;
  USE SIGNAL ;
  PORT
   LAYER M5 ;
   RECT 275.664000 0.000000 275.688000 0.084000 ;
  END
 END tw_d1[444]
 PIN tw_d1[445]
  DIRECTION INPUT ;
  USE SIGNAL ;
  PORT
   LAYER M5 ;
   RECT 275.856000 0.000000 275.880000 0.084000 ;
  END
 END tw_d1[445]
 PIN tw_d1[446]
  DIRECTION INPUT ;
  USE SIGNAL ;
  PORT
   LAYER M5 ;
   RECT 276.048000 0.000000 276.072000 0.084000 ;
  END
 END tw_d1[446]
 PIN tw_d1[447]
  DIRECTION INPUT ;
  USE SIGNAL ;
  PORT
   LAYER M5 ;
   RECT 276.240000 0.000000 276.264000 0.084000 ;
  END
 END tw_d1[447]
 PIN tw_d1[448]
  DIRECTION INPUT ;
  USE SIGNAL ;
  PORT
   LAYER M5 ;
   RECT 276.432000 0.000000 276.456000 0.084000 ;
  END
 END tw_d1[448]
 PIN tw_d1[449]
  DIRECTION INPUT ;
  USE SIGNAL ;
  PORT
   LAYER M5 ;
   RECT 276.624000 0.000000 276.648000 0.084000 ;
  END
 END tw_d1[449]
 PIN tw_d1[450]
  DIRECTION INPUT ;
  USE SIGNAL ;
  PORT
   LAYER M5 ;
   RECT 276.816000 0.000000 276.840000 0.084000 ;
  END
 END tw_d1[450]
 PIN tw_d1[451]
  DIRECTION INPUT ;
  USE SIGNAL ;
  PORT
   LAYER M5 ;
   RECT 277.008000 0.000000 277.032000 0.084000 ;
  END
 END tw_d1[451]
 PIN tw_d1[452]
  DIRECTION INPUT ;
  USE SIGNAL ;
  PORT
   LAYER M5 ;
   RECT 277.200000 0.000000 277.224000 0.084000 ;
  END
 END tw_d1[452]
 PIN tw_d1[453]
  DIRECTION INPUT ;
  USE SIGNAL ;
  PORT
   LAYER M5 ;
   RECT 277.392000 0.000000 277.416000 0.084000 ;
  END
 END tw_d1[453]
 PIN tw_d1[454]
  DIRECTION INPUT ;
  USE SIGNAL ;
  PORT
   LAYER M5 ;
   RECT 277.584000 0.000000 277.608000 0.084000 ;
  END
 END tw_d1[454]
 PIN tw_d1[455]
  DIRECTION INPUT ;
  USE SIGNAL ;
  PORT
   LAYER M5 ;
   RECT 277.776000 0.000000 277.800000 0.084000 ;
  END
 END tw_d1[455]
 PIN tw_d1[456]
  DIRECTION INPUT ;
  USE SIGNAL ;
  PORT
   LAYER M5 ;
   RECT 277.968000 0.000000 277.992000 0.084000 ;
  END
 END tw_d1[456]
 PIN p_idx[0]
  DIRECTION INPUT ;
  USE SIGNAL ;
  PORT
   LAYER M4 ;
   RECT 354.156000 81.024000 354.240000 81.048000 ;
  END
 END p_idx[0]
 PIN p_idx[1]
  DIRECTION INPUT ;
  USE SIGNAL ;
  PORT
   LAYER M4 ;
   RECT 354.156000 81.216000 354.240000 81.240000 ;
  END
 END p_idx[1]
 PIN p_idx[2]
  DIRECTION INPUT ;
  USE SIGNAL ;
  PORT
   LAYER M4 ;
   RECT 354.156000 81.408000 354.240000 81.432000 ;
  END
 END p_idx[2]
 PIN p_idx[3]
  DIRECTION INPUT ;
  USE SIGNAL ;
  PORT
   LAYER M4 ;
   RECT 354.156000 81.600000 354.240000 81.624000 ;
  END
 END p_idx[3]
 PIN p_idx[4]
  DIRECTION INPUT ;
  USE SIGNAL ;
  PORT
   LAYER M4 ;
   RECT 354.156000 81.792000 354.240000 81.816000 ;
  END
 END p_idx[4]
 PIN p_idx[5]
  DIRECTION INPUT ;
  USE SIGNAL ;
  PORT
   LAYER M4 ;
   RECT 354.156000 81.984000 354.240000 82.008000 ;
  END
 END p_idx[5]
 PIN p_idx[6]
  DIRECTION INPUT ;
  USE SIGNAL ;
  PORT
   LAYER M4 ;
   RECT 354.156000 82.176000 354.240000 82.200000 ;
  END
 END p_idx[6]
 PIN p_idx[7]
  DIRECTION INPUT ;
  USE SIGNAL ;
  PORT
   LAYER M4 ;
   RECT 354.156000 82.368000 354.240000 82.392000 ;
  END
 END p_idx[7]
 PIN p_idx[8]
  DIRECTION INPUT ;
  USE SIGNAL ;
  PORT
   LAYER M4 ;
   RECT 354.156000 82.560000 354.240000 82.584000 ;
  END
 END p_idx[8]
 PIN p_re
  DIRECTION INPUT ;
  USE SIGNAL ;
  PORT
   LAYER M4 ;
   RECT 354.156000 83.712000 354.240000 83.736000 ;
  END
 END p_re
 PIN p_q[0]
  DIRECTION OUTPUT ;
  USE SIGNAL ;
  PORT
   LAYER M4 ;
   RECT 354.156000 88.560000 354.240000 88.584000 ;
  END
 END p_q[0]
 PIN p_q[1]
  DIRECTION OUTPUT ;
  USE SIGNAL ;
  PORT
   LAYER M4 ;
   RECT 354.156000 88.752000 354.240000 88.776000 ;
  END
 END p_q[1]
 PIN p_q[2]
  DIRECTION OUTPUT ;
  USE SIGNAL ;
  PORT
   LAYER M4 ;
   RECT 354.156000 88.944000 354.240000 88.968000 ;
  END
 END p_q[2]
 PIN p_q[3]
  DIRECTION OUTPUT ;
  USE SIGNAL ;
  PORT
   LAYER M4 ;
   RECT 354.156000 89.136000 354.240000 89.160000 ;
  END
 END p_q[3]
 PIN p_q[4]
  DIRECTION OUTPUT ;
  USE SIGNAL ;
  PORT
   LAYER M4 ;
   RECT 354.156000 89.328000 354.240000 89.352000 ;
  END
 END p_q[4]
 PIN p_q[5]
  DIRECTION OUTPUT ;
  USE SIGNAL ;
  PORT
   LAYER M4 ;
   RECT 354.156000 89.520000 354.240000 89.544000 ;
  END
 END p_q[5]
 PIN p_q[6]
  DIRECTION OUTPUT ;
  USE SIGNAL ;
  PORT
   LAYER M4 ;
   RECT 354.156000 89.712000 354.240000 89.736000 ;
  END
 END p_q[6]
 PIN p_q[7]
  DIRECTION OUTPUT ;
  USE SIGNAL ;
  PORT
   LAYER M4 ;
   RECT 354.156000 89.904000 354.240000 89.928000 ;
  END
 END p_q[7]
 PIN p_q[8]
  DIRECTION OUTPUT ;
  USE SIGNAL ;
  PORT
   LAYER M4 ;
   RECT 354.156000 90.096000 354.240000 90.120000 ;
  END
 END p_q[8]
 PIN p_q[9]
  DIRECTION OUTPUT ;
  USE SIGNAL ;
  PORT
   LAYER M4 ;
   RECT 354.156000 90.288000 354.240000 90.312000 ;
  END
 END p_q[9]
 PIN p_q[10]
  DIRECTION OUTPUT ;
  USE SIGNAL ;
  PORT
   LAYER M4 ;
   RECT 354.156000 90.480000 354.240000 90.504000 ;
  END
 END p_q[10]
 PIN p_q[11]
  DIRECTION OUTPUT ;
  USE SIGNAL ;
  PORT
   LAYER M4 ;
   RECT 354.156000 90.672000 354.240000 90.696000 ;
  END
 END p_q[11]
 PIN p_q[12]
  DIRECTION OUTPUT ;
  USE SIGNAL ;
  PORT
   LAYER M4 ;
   RECT 354.156000 90.864000 354.240000 90.888000 ;
  END
 END p_q[12]
 PIN p_q[13]
  DIRECTION OUTPUT ;
  USE SIGNAL ;
  PORT
   LAYER M4 ;
   RECT 354.156000 91.056000 354.240000 91.080000 ;
  END
 END p_q[13]
 PIN p_q[14]
  DIRECTION OUTPUT ;
  USE SIGNAL ;
  PORT
   LAYER M4 ;
   RECT 354.156000 91.248000 354.240000 91.272000 ;
  END
 END p_q[14]
 PIN p_q[15]
  DIRECTION OUTPUT ;
  USE SIGNAL ;
  PORT
   LAYER M4 ;
   RECT 354.156000 91.440000 354.240000 91.464000 ;
  END
 END p_q[15]
 PIN p_q[16]
  DIRECTION OUTPUT ;
  USE SIGNAL ;
  PORT
   LAYER M4 ;
   RECT 354.156000 91.632000 354.240000 91.656000 ;
  END
 END p_q[16]
 PIN p_q[17]
  DIRECTION OUTPUT ;
  USE SIGNAL ;
  PORT
   LAYER M4 ;
   RECT 354.156000 91.824000 354.240000 91.848000 ;
  END
 END p_q[17]
 PIN p_q[18]
  DIRECTION OUTPUT ;
  USE SIGNAL ;
  PORT
   LAYER M4 ;
   RECT 354.156000 92.016000 354.240000 92.040000 ;
  END
 END p_q[18]
 PIN p_q[19]
  DIRECTION OUTPUT ;
  USE SIGNAL ;
  PORT
   LAYER M4 ;
   RECT 354.156000 92.208000 354.240000 92.232000 ;
  END
 END p_q[19]
 PIN p_q[20]
  DIRECTION OUTPUT ;
  USE SIGNAL ;
  PORT
   LAYER M4 ;
   RECT 354.156000 92.400000 354.240000 92.424000 ;
  END
 END p_q[20]
 PIN p_q[21]
  DIRECTION OUTPUT ;
  USE SIGNAL ;
  PORT
   LAYER M4 ;
   RECT 354.156000 92.592000 354.240000 92.616000 ;
  END
 END p_q[21]
 PIN p_q[22]
  DIRECTION OUTPUT ;
  USE SIGNAL ;
  PORT
   LAYER M4 ;
   RECT 354.156000 92.784000 354.240000 92.808000 ;
  END
 END p_q[22]
 PIN p_q[23]
  DIRECTION OUTPUT ;
  USE SIGNAL ;
  PORT
   LAYER M4 ;
   RECT 354.156000 92.976000 354.240000 93.000000 ;
  END
 END p_q[23]
 PIN p_q[24]
  DIRECTION OUTPUT ;
  USE SIGNAL ;
  PORT
   LAYER M4 ;
   RECT 354.156000 93.168000 354.240000 93.192000 ;
  END
 END p_q[24]
 PIN p_q[25]
  DIRECTION OUTPUT ;
  USE SIGNAL ;
  PORT
   LAYER M4 ;
   RECT 354.156000 93.360000 354.240000 93.384000 ;
  END
 END p_q[25]
 PIN p_q[26]
  DIRECTION OUTPUT ;
  USE SIGNAL ;
  PORT
   LAYER M4 ;
   RECT 354.156000 93.552000 354.240000 93.576000 ;
  END
 END p_q[26]
 PIN p_q[27]
  DIRECTION OUTPUT ;
  USE SIGNAL ;
  PORT
   LAYER M4 ;
   RECT 354.156000 93.744000 354.240000 93.768000 ;
  END
 END p_q[27]
 PIN p_q[28]
  DIRECTION OUTPUT ;
  USE SIGNAL ;
  PORT
   LAYER M4 ;
   RECT 354.156000 93.936000 354.240000 93.960000 ;
  END
 END p_q[28]
 PIN p_q[29]
  DIRECTION OUTPUT ;
  USE SIGNAL ;
  PORT
   LAYER M4 ;
   RECT 354.156000 94.128000 354.240000 94.152000 ;
  END
 END p_q[29]
 PIN p_q[30]
  DIRECTION OUTPUT ;
  USE SIGNAL ;
  PORT
   LAYER M4 ;
   RECT 354.156000 94.320000 354.240000 94.344000 ;
  END
 END p_q[30]
 PIN p_q[31]
  DIRECTION OUTPUT ;
  USE SIGNAL ;
  PORT
   LAYER M4 ;
   RECT 354.156000 94.512000 354.240000 94.536000 ;
  END
 END p_q[31]
 PIN p_q[32]
  DIRECTION OUTPUT ;
  USE SIGNAL ;
  PORT
   LAYER M4 ;
   RECT 354.156000 94.704000 354.240000 94.728000 ;
  END
 END p_q[32]
 PIN p_q[33]
  DIRECTION OUTPUT ;
  USE SIGNAL ;
  PORT
   LAYER M4 ;
   RECT 354.156000 94.896000 354.240000 94.920000 ;
  END
 END p_q[33]
 PIN p_q[34]
  DIRECTION OUTPUT ;
  USE SIGNAL ;
  PORT
   LAYER M4 ;
   RECT 354.156000 95.088000 354.240000 95.112000 ;
  END
 END p_q[34]
 PIN p_q[35]
  DIRECTION OUTPUT ;
  USE SIGNAL ;
  PORT
   LAYER M4 ;
   RECT 354.156000 95.280000 354.240000 95.304000 ;
  END
 END p_q[35]
 PIN p_q[36]
  DIRECTION OUTPUT ;
  USE SIGNAL ;
  PORT
   LAYER M4 ;
   RECT 354.156000 95.472000 354.240000 95.496000 ;
  END
 END p_q[36]
 PIN p_q[37]
  DIRECTION OUTPUT ;
  USE SIGNAL ;
  PORT
   LAYER M4 ;
   RECT 354.156000 95.664000 354.240000 95.688000 ;
  END
 END p_q[37]
 PIN p_q[38]
  DIRECTION OUTPUT ;
  USE SIGNAL ;
  PORT
   LAYER M4 ;
   RECT 354.156000 95.856000 354.240000 95.880000 ;
  END
 END p_q[38]
 PIN p_q[39]
  DIRECTION OUTPUT ;
  USE SIGNAL ;
  PORT
   LAYER M4 ;
   RECT 354.156000 96.048000 354.240000 96.072000 ;
  END
 END p_q[39]
 PIN p_q[40]
  DIRECTION OUTPUT ;
  USE SIGNAL ;
  PORT
   LAYER M4 ;
   RECT 354.156000 96.240000 354.240000 96.264000 ;
  END
 END p_q[40]
 PIN p_q[41]
  DIRECTION OUTPUT ;
  USE SIGNAL ;
  PORT
   LAYER M4 ;
   RECT 354.156000 96.432000 354.240000 96.456000 ;
  END
 END p_q[41]
 PIN p_q[42]
  DIRECTION OUTPUT ;
  USE SIGNAL ;
  PORT
   LAYER M4 ;
   RECT 354.156000 96.624000 354.240000 96.648000 ;
  END
 END p_q[42]
 PIN p_q[43]
  DIRECTION OUTPUT ;
  USE SIGNAL ;
  PORT
   LAYER M4 ;
   RECT 354.156000 96.816000 354.240000 96.840000 ;
  END
 END p_q[43]
 PIN p_q[44]
  DIRECTION OUTPUT ;
  USE SIGNAL ;
  PORT
   LAYER M4 ;
   RECT 354.156000 97.008000 354.240000 97.032000 ;
  END
 END p_q[44]
 PIN p_q[45]
  DIRECTION OUTPUT ;
  USE SIGNAL ;
  PORT
   LAYER M4 ;
   RECT 354.156000 97.200000 354.240000 97.224000 ;
  END
 END p_q[45]
 PIN p_q[46]
  DIRECTION OUTPUT ;
  USE SIGNAL ;
  PORT
   LAYER M4 ;
   RECT 354.156000 97.392000 354.240000 97.416000 ;
  END
 END p_q[46]
 PIN p_q[47]
  DIRECTION OUTPUT ;
  USE SIGNAL ;
  PORT
   LAYER M4 ;
   RECT 354.156000 97.584000 354.240000 97.608000 ;
  END
 END p_q[47]
 PIN p_q[48]
  DIRECTION OUTPUT ;
  USE SIGNAL ;
  PORT
   LAYER M4 ;
   RECT 354.156000 97.776000 354.240000 97.800000 ;
  END
 END p_q[48]
 PIN p_q[49]
  DIRECTION OUTPUT ;
  USE SIGNAL ;
  PORT
   LAYER M4 ;
   RECT 354.156000 97.968000 354.240000 97.992000 ;
  END
 END p_q[49]
 PIN p_q[50]
  DIRECTION OUTPUT ;
  USE SIGNAL ;
  PORT
   LAYER M4 ;
   RECT 354.156000 98.160000 354.240000 98.184000 ;
  END
 END p_q[50]
 PIN p_q[51]
  DIRECTION OUTPUT ;
  USE SIGNAL ;
  PORT
   LAYER M4 ;
   RECT 354.156000 98.352000 354.240000 98.376000 ;
  END
 END p_q[51]
 PIN p_q[52]
  DIRECTION OUTPUT ;
  USE SIGNAL ;
  PORT
   LAYER M4 ;
   RECT 354.156000 98.544000 354.240000 98.568000 ;
  END
 END p_q[52]
 PIN p_q[53]
  DIRECTION OUTPUT ;
  USE SIGNAL ;
  PORT
   LAYER M4 ;
   RECT 354.156000 98.736000 354.240000 98.760000 ;
  END
 END p_q[53]
 PIN p_q[54]
  DIRECTION OUTPUT ;
  USE SIGNAL ;
  PORT
   LAYER M4 ;
   RECT 354.156000 98.928000 354.240000 98.952000 ;
  END
 END p_q[54]
 PIN p_q[55]
  DIRECTION OUTPUT ;
  USE SIGNAL ;
  PORT
   LAYER M4 ;
   RECT 354.156000 99.120000 354.240000 99.144000 ;
  END
 END p_q[55]
 PIN p_q[56]
  DIRECTION OUTPUT ;
  USE SIGNAL ;
  PORT
   LAYER M4 ;
   RECT 354.156000 99.312000 354.240000 99.336000 ;
  END
 END p_q[56]
 PIN p_q[57]
  DIRECTION OUTPUT ;
  USE SIGNAL ;
  PORT
   LAYER M4 ;
   RECT 354.156000 99.504000 354.240000 99.528000 ;
  END
 END p_q[57]
 PIN p_q[58]
  DIRECTION OUTPUT ;
  USE SIGNAL ;
  PORT
   LAYER M4 ;
   RECT 354.156000 99.696000 354.240000 99.720000 ;
  END
 END p_q[58]
 PIN p_q[59]
  DIRECTION OUTPUT ;
  USE SIGNAL ;
  PORT
   LAYER M4 ;
   RECT 354.156000 99.888000 354.240000 99.912000 ;
  END
 END p_q[59]
 PIN p_q[60]
  DIRECTION OUTPUT ;
  USE SIGNAL ;
  PORT
   LAYER M4 ;
   RECT 354.156000 100.080000 354.240000 100.104000 ;
  END
 END p_q[60]
 PIN p_q[61]
  DIRECTION OUTPUT ;
  USE SIGNAL ;
  PORT
   LAYER M4 ;
   RECT 354.156000 100.272000 354.240000 100.296000 ;
  END
 END p_q[61]
 PIN p_q[62]
  DIRECTION OUTPUT ;
  USE SIGNAL ;
  PORT
   LAYER M4 ;
   RECT 354.156000 100.464000 354.240000 100.488000 ;
  END
 END p_q[62]
 PIN p_q[63]
  DIRECTION OUTPUT ;
  USE SIGNAL ;
  PORT
   LAYER M4 ;
   RECT 354.156000 100.656000 354.240000 100.680000 ;
  END
 END p_q[63]
 PIN p_q[64]
  DIRECTION OUTPUT ;
  USE SIGNAL ;
  PORT
   LAYER M4 ;
   RECT 354.156000 100.848000 354.240000 100.872000 ;
  END
 END p_q[64]
 PIN p_q[65]
  DIRECTION OUTPUT ;
  USE SIGNAL ;
  PORT
   LAYER M4 ;
   RECT 354.156000 101.040000 354.240000 101.064000 ;
  END
 END p_q[65]
 PIN p_q[66]
  DIRECTION OUTPUT ;
  USE SIGNAL ;
  PORT
   LAYER M4 ;
   RECT 354.156000 101.232000 354.240000 101.256000 ;
  END
 END p_q[66]
 PIN p_q[67]
  DIRECTION OUTPUT ;
  USE SIGNAL ;
  PORT
   LAYER M4 ;
   RECT 354.156000 101.424000 354.240000 101.448000 ;
  END
 END p_q[67]
 PIN p_q[68]
  DIRECTION OUTPUT ;
  USE SIGNAL ;
  PORT
   LAYER M4 ;
   RECT 354.156000 101.616000 354.240000 101.640000 ;
  END
 END p_q[68]
 PIN p_q[69]
  DIRECTION OUTPUT ;
  USE SIGNAL ;
  PORT
   LAYER M4 ;
   RECT 354.156000 101.808000 354.240000 101.832000 ;
  END
 END p_q[69]
 PIN p_q[70]
  DIRECTION OUTPUT ;
  USE SIGNAL ;
  PORT
   LAYER M4 ;
   RECT 354.156000 102.000000 354.240000 102.024000 ;
  END
 END p_q[70]
 PIN p_q[71]
  DIRECTION OUTPUT ;
  USE SIGNAL ;
  PORT
   LAYER M4 ;
   RECT 354.156000 102.192000 354.240000 102.216000 ;
  END
 END p_q[71]
 PIN p_q[72]
  DIRECTION OUTPUT ;
  USE SIGNAL ;
  PORT
   LAYER M4 ;
   RECT 354.156000 102.384000 354.240000 102.408000 ;
  END
 END p_q[72]
 PIN p_q[73]
  DIRECTION OUTPUT ;
  USE SIGNAL ;
  PORT
   LAYER M4 ;
   RECT 354.156000 102.576000 354.240000 102.600000 ;
  END
 END p_q[73]
 PIN p_q[74]
  DIRECTION OUTPUT ;
  USE SIGNAL ;
  PORT
   LAYER M4 ;
   RECT 354.156000 102.768000 354.240000 102.792000 ;
  END
 END p_q[74]
 PIN p_q[75]
  DIRECTION OUTPUT ;
  USE SIGNAL ;
  PORT
   LAYER M4 ;
   RECT 354.156000 102.960000 354.240000 102.984000 ;
  END
 END p_q[75]
 PIN p_q[76]
  DIRECTION OUTPUT ;
  USE SIGNAL ;
  PORT
   LAYER M4 ;
   RECT 354.156000 103.152000 354.240000 103.176000 ;
  END
 END p_q[76]
 PIN p_q[77]
  DIRECTION OUTPUT ;
  USE SIGNAL ;
  PORT
   LAYER M4 ;
   RECT 354.156000 103.344000 354.240000 103.368000 ;
  END
 END p_q[77]
 PIN p_q[78]
  DIRECTION OUTPUT ;
  USE SIGNAL ;
  PORT
   LAYER M4 ;
   RECT 354.156000 103.536000 354.240000 103.560000 ;
  END
 END p_q[78]
 PIN p_q[79]
  DIRECTION OUTPUT ;
  USE SIGNAL ;
  PORT
   LAYER M4 ;
   RECT 354.156000 103.728000 354.240000 103.752000 ;
  END
 END p_q[79]
 PIN p_q[80]
  DIRECTION OUTPUT ;
  USE SIGNAL ;
  PORT
   LAYER M4 ;
   RECT 354.156000 103.920000 354.240000 103.944000 ;
  END
 END p_q[80]
 PIN p_q[81]
  DIRECTION OUTPUT ;
  USE SIGNAL ;
  PORT
   LAYER M4 ;
   RECT 354.156000 104.112000 354.240000 104.136000 ;
  END
 END p_q[81]
 PIN p_q[82]
  DIRECTION OUTPUT ;
  USE SIGNAL ;
  PORT
   LAYER M4 ;
   RECT 354.156000 104.304000 354.240000 104.328000 ;
  END
 END p_q[82]
 PIN p_q[83]
  DIRECTION OUTPUT ;
  USE SIGNAL ;
  PORT
   LAYER M4 ;
   RECT 354.156000 104.496000 354.240000 104.520000 ;
  END
 END p_q[83]
 PIN p_q[84]
  DIRECTION OUTPUT ;
  USE SIGNAL ;
  PORT
   LAYER M4 ;
   RECT 354.156000 104.688000 354.240000 104.712000 ;
  END
 END p_q[84]
 PIN p_q[85]
  DIRECTION OUTPUT ;
  USE SIGNAL ;
  PORT
   LAYER M4 ;
   RECT 354.156000 104.880000 354.240000 104.904000 ;
  END
 END p_q[85]
 PIN p_q[86]
  DIRECTION OUTPUT ;
  USE SIGNAL ;
  PORT
   LAYER M4 ;
   RECT 354.156000 105.072000 354.240000 105.096000 ;
  END
 END p_q[86]
 PIN p_q[87]
  DIRECTION OUTPUT ;
  USE SIGNAL ;
  PORT
   LAYER M4 ;
   RECT 354.156000 105.264000 354.240000 105.288000 ;
  END
 END p_q[87]
 PIN p_q[88]
  DIRECTION OUTPUT ;
  USE SIGNAL ;
  PORT
   LAYER M4 ;
   RECT 354.156000 105.456000 354.240000 105.480000 ;
  END
 END p_q[88]
 PIN p_q[89]
  DIRECTION OUTPUT ;
  USE SIGNAL ;
  PORT
   LAYER M4 ;
   RECT 354.156000 105.648000 354.240000 105.672000 ;
  END
 END p_q[89]
 PIN p_q[90]
  DIRECTION OUTPUT ;
  USE SIGNAL ;
  PORT
   LAYER M4 ;
   RECT 354.156000 105.840000 354.240000 105.864000 ;
  END
 END p_q[90]
 PIN p_q[91]
  DIRECTION OUTPUT ;
  USE SIGNAL ;
  PORT
   LAYER M4 ;
   RECT 354.156000 106.032000 354.240000 106.056000 ;
  END
 END p_q[91]
 PIN p_q[92]
  DIRECTION OUTPUT ;
  USE SIGNAL ;
  PORT
   LAYER M4 ;
   RECT 354.156000 106.224000 354.240000 106.248000 ;
  END
 END p_q[92]
 PIN p_q[93]
  DIRECTION OUTPUT ;
  USE SIGNAL ;
  PORT
   LAYER M4 ;
   RECT 354.156000 106.416000 354.240000 106.440000 ;
  END
 END p_q[93]
 PIN p_q[94]
  DIRECTION OUTPUT ;
  USE SIGNAL ;
  PORT
   LAYER M4 ;
   RECT 354.156000 106.608000 354.240000 106.632000 ;
  END
 END p_q[94]
 PIN p_q[95]
  DIRECTION OUTPUT ;
  USE SIGNAL ;
  PORT
   LAYER M4 ;
   RECT 354.156000 106.800000 354.240000 106.824000 ;
  END
 END p_q[95]
 PIN p_q[96]
  DIRECTION OUTPUT ;
  USE SIGNAL ;
  PORT
   LAYER M4 ;
   RECT 354.156000 106.992000 354.240000 107.016000 ;
  END
 END p_q[96]
 PIN p_q[97]
  DIRECTION OUTPUT ;
  USE SIGNAL ;
  PORT
   LAYER M4 ;
   RECT 354.156000 107.184000 354.240000 107.208000 ;
  END
 END p_q[97]
 PIN p_q[98]
  DIRECTION OUTPUT ;
  USE SIGNAL ;
  PORT
   LAYER M4 ;
   RECT 354.156000 107.376000 354.240000 107.400000 ;
  END
 END p_q[98]
 PIN p_q[99]
  DIRECTION OUTPUT ;
  USE SIGNAL ;
  PORT
   LAYER M4 ;
   RECT 354.156000 107.568000 354.240000 107.592000 ;
  END
 END p_q[99]
 PIN p_q[100]
  DIRECTION OUTPUT ;
  USE SIGNAL ;
  PORT
   LAYER M4 ;
   RECT 354.156000 107.760000 354.240000 107.784000 ;
  END
 END p_q[100]
 PIN p_q[101]
  DIRECTION OUTPUT ;
  USE SIGNAL ;
  PORT
   LAYER M4 ;
   RECT 354.156000 107.952000 354.240000 107.976000 ;
  END
 END p_q[101]
 PIN p_q[102]
  DIRECTION OUTPUT ;
  USE SIGNAL ;
  PORT
   LAYER M4 ;
   RECT 354.156000 108.144000 354.240000 108.168000 ;
  END
 END p_q[102]
 PIN p_q[103]
  DIRECTION OUTPUT ;
  USE SIGNAL ;
  PORT
   LAYER M4 ;
   RECT 354.156000 108.336000 354.240000 108.360000 ;
  END
 END p_q[103]
 PIN p_q[104]
  DIRECTION OUTPUT ;
  USE SIGNAL ;
  PORT
   LAYER M4 ;
   RECT 354.156000 108.528000 354.240000 108.552000 ;
  END
 END p_q[104]
 PIN p_q[105]
  DIRECTION OUTPUT ;
  USE SIGNAL ;
  PORT
   LAYER M4 ;
   RECT 354.156000 108.720000 354.240000 108.744000 ;
  END
 END p_q[105]
 PIN p_q[106]
  DIRECTION OUTPUT ;
  USE SIGNAL ;
  PORT
   LAYER M4 ;
   RECT 354.156000 108.912000 354.240000 108.936000 ;
  END
 END p_q[106]
 PIN p_q[107]
  DIRECTION OUTPUT ;
  USE SIGNAL ;
  PORT
   LAYER M4 ;
   RECT 354.156000 109.104000 354.240000 109.128000 ;
  END
 END p_q[107]
 PIN p_q[108]
  DIRECTION OUTPUT ;
  USE SIGNAL ;
  PORT
   LAYER M4 ;
   RECT 354.156000 109.296000 354.240000 109.320000 ;
  END
 END p_q[108]
 PIN p_q[109]
  DIRECTION OUTPUT ;
  USE SIGNAL ;
  PORT
   LAYER M4 ;
   RECT 354.156000 109.488000 354.240000 109.512000 ;
  END
 END p_q[109]
 PIN p_q[110]
  DIRECTION OUTPUT ;
  USE SIGNAL ;
  PORT
   LAYER M4 ;
   RECT 354.156000 109.680000 354.240000 109.704000 ;
  END
 END p_q[110]
 PIN p_q[111]
  DIRECTION OUTPUT ;
  USE SIGNAL ;
  PORT
   LAYER M4 ;
   RECT 354.156000 109.872000 354.240000 109.896000 ;
  END
 END p_q[111]
 PIN p_q[112]
  DIRECTION OUTPUT ;
  USE SIGNAL ;
  PORT
   LAYER M4 ;
   RECT 354.156000 110.064000 354.240000 110.088000 ;
  END
 END p_q[112]
 PIN p_q[113]
  DIRECTION OUTPUT ;
  USE SIGNAL ;
  PORT
   LAYER M4 ;
   RECT 354.156000 110.256000 354.240000 110.280000 ;
  END
 END p_q[113]
 PIN p_q[114]
  DIRECTION OUTPUT ;
  USE SIGNAL ;
  PORT
   LAYER M4 ;
   RECT 354.156000 110.448000 354.240000 110.472000 ;
  END
 END p_q[114]
 PIN p_q[115]
  DIRECTION OUTPUT ;
  USE SIGNAL ;
  PORT
   LAYER M4 ;
   RECT 354.156000 110.640000 354.240000 110.664000 ;
  END
 END p_q[115]
 PIN p_q[116]
  DIRECTION OUTPUT ;
  USE SIGNAL ;
  PORT
   LAYER M4 ;
   RECT 354.156000 110.832000 354.240000 110.856000 ;
  END
 END p_q[116]
 PIN p_q[117]
  DIRECTION OUTPUT ;
  USE SIGNAL ;
  PORT
   LAYER M4 ;
   RECT 354.156000 111.024000 354.240000 111.048000 ;
  END
 END p_q[117]
 PIN p_q[118]
  DIRECTION OUTPUT ;
  USE SIGNAL ;
  PORT
   LAYER M4 ;
   RECT 354.156000 111.216000 354.240000 111.240000 ;
  END
 END p_q[118]
 PIN p_q[119]
  DIRECTION OUTPUT ;
  USE SIGNAL ;
  PORT
   LAYER M4 ;
   RECT 354.156000 111.408000 354.240000 111.432000 ;
  END
 END p_q[119]
 PIN p_q[120]
  DIRECTION OUTPUT ;
  USE SIGNAL ;
  PORT
   LAYER M4 ;
   RECT 354.156000 111.600000 354.240000 111.624000 ;
  END
 END p_q[120]
 PIN p_q[121]
  DIRECTION OUTPUT ;
  USE SIGNAL ;
  PORT
   LAYER M4 ;
   RECT 354.156000 111.792000 354.240000 111.816000 ;
  END
 END p_q[121]
 PIN p_q[122]
  DIRECTION OUTPUT ;
  USE SIGNAL ;
  PORT
   LAYER M4 ;
   RECT 354.156000 111.984000 354.240000 112.008000 ;
  END
 END p_q[122]
 PIN p_q[123]
  DIRECTION OUTPUT ;
  USE SIGNAL ;
  PORT
   LAYER M4 ;
   RECT 354.156000 112.176000 354.240000 112.200000 ;
  END
 END p_q[123]
 PIN p_q[124]
  DIRECTION OUTPUT ;
  USE SIGNAL ;
  PORT
   LAYER M4 ;
   RECT 354.156000 112.368000 354.240000 112.392000 ;
  END
 END p_q[124]
 PIN p_q[125]
  DIRECTION OUTPUT ;
  USE SIGNAL ;
  PORT
   LAYER M4 ;
   RECT 354.156000 112.560000 354.240000 112.584000 ;
  END
 END p_q[125]
 PIN p_q[126]
  DIRECTION OUTPUT ;
  USE SIGNAL ;
  PORT
   LAYER M4 ;
   RECT 354.156000 112.752000 354.240000 112.776000 ;
  END
 END p_q[126]
 PIN p_q[127]
  DIRECTION OUTPUT ;
  USE SIGNAL ;
  PORT
   LAYER M4 ;
   RECT 354.156000 112.944000 354.240000 112.968000 ;
  END
 END p_q[127]
 PIN p_q[128]
  DIRECTION OUTPUT ;
  USE SIGNAL ;
  PORT
   LAYER M4 ;
   RECT 354.156000 113.136000 354.240000 113.160000 ;
  END
 END p_q[128]
 PIN p_q[129]
  DIRECTION OUTPUT ;
  USE SIGNAL ;
  PORT
   LAYER M4 ;
   RECT 354.156000 113.328000 354.240000 113.352000 ;
  END
 END p_q[129]
 PIN p_q[130]
  DIRECTION OUTPUT ;
  USE SIGNAL ;
  PORT
   LAYER M4 ;
   RECT 354.156000 113.520000 354.240000 113.544000 ;
  END
 END p_q[130]
 PIN p_q[131]
  DIRECTION OUTPUT ;
  USE SIGNAL ;
  PORT
   LAYER M4 ;
   RECT 354.156000 113.712000 354.240000 113.736000 ;
  END
 END p_q[131]
 PIN p_q[132]
  DIRECTION OUTPUT ;
  USE SIGNAL ;
  PORT
   LAYER M4 ;
   RECT 354.156000 113.904000 354.240000 113.928000 ;
  END
 END p_q[132]
 PIN p_q[133]
  DIRECTION OUTPUT ;
  USE SIGNAL ;
  PORT
   LAYER M4 ;
   RECT 354.156000 114.096000 354.240000 114.120000 ;
  END
 END p_q[133]
 PIN p_q[134]
  DIRECTION OUTPUT ;
  USE SIGNAL ;
  PORT
   LAYER M4 ;
   RECT 354.156000 114.288000 354.240000 114.312000 ;
  END
 END p_q[134]
 PIN p_q[135]
  DIRECTION OUTPUT ;
  USE SIGNAL ;
  PORT
   LAYER M4 ;
   RECT 354.156000 114.480000 354.240000 114.504000 ;
  END
 END p_q[135]
 PIN p_q[136]
  DIRECTION OUTPUT ;
  USE SIGNAL ;
  PORT
   LAYER M4 ;
   RECT 354.156000 114.672000 354.240000 114.696000 ;
  END
 END p_q[136]
 PIN p_q[137]
  DIRECTION OUTPUT ;
  USE SIGNAL ;
  PORT
   LAYER M4 ;
   RECT 354.156000 114.864000 354.240000 114.888000 ;
  END
 END p_q[137]
 PIN p_q[138]
  DIRECTION OUTPUT ;
  USE SIGNAL ;
  PORT
   LAYER M4 ;
   RECT 354.156000 115.056000 354.240000 115.080000 ;
  END
 END p_q[138]
 PIN p_q[139]
  DIRECTION OUTPUT ;
  USE SIGNAL ;
  PORT
   LAYER M4 ;
   RECT 354.156000 115.248000 354.240000 115.272000 ;
  END
 END p_q[139]
 PIN p_q[140]
  DIRECTION OUTPUT ;
  USE SIGNAL ;
  PORT
   LAYER M4 ;
   RECT 354.156000 115.440000 354.240000 115.464000 ;
  END
 END p_q[140]
 PIN p_q[141]
  DIRECTION OUTPUT ;
  USE SIGNAL ;
  PORT
   LAYER M4 ;
   RECT 354.156000 115.632000 354.240000 115.656000 ;
  END
 END p_q[141]
 PIN p_q[142]
  DIRECTION OUTPUT ;
  USE SIGNAL ;
  PORT
   LAYER M4 ;
   RECT 354.156000 115.824000 354.240000 115.848000 ;
  END
 END p_q[142]
 PIN p_q[143]
  DIRECTION OUTPUT ;
  USE SIGNAL ;
  PORT
   LAYER M4 ;
   RECT 354.156000 116.016000 354.240000 116.040000 ;
  END
 END p_q[143]
 PIN p_q[144]
  DIRECTION OUTPUT ;
  USE SIGNAL ;
  PORT
   LAYER M4 ;
   RECT 354.156000 116.208000 354.240000 116.232000 ;
  END
 END p_q[144]
 PIN p_q[145]
  DIRECTION OUTPUT ;
  USE SIGNAL ;
  PORT
   LAYER M4 ;
   RECT 354.156000 116.400000 354.240000 116.424000 ;
  END
 END p_q[145]
 PIN p_q[146]
  DIRECTION OUTPUT ;
  USE SIGNAL ;
  PORT
   LAYER M4 ;
   RECT 354.156000 116.592000 354.240000 116.616000 ;
  END
 END p_q[146]
 PIN p_q[147]
  DIRECTION OUTPUT ;
  USE SIGNAL ;
  PORT
   LAYER M4 ;
   RECT 354.156000 116.784000 354.240000 116.808000 ;
  END
 END p_q[147]
 PIN p_q[148]
  DIRECTION OUTPUT ;
  USE SIGNAL ;
  PORT
   LAYER M4 ;
   RECT 354.156000 116.976000 354.240000 117.000000 ;
  END
 END p_q[148]
 PIN p_q[149]
  DIRECTION OUTPUT ;
  USE SIGNAL ;
  PORT
   LAYER M4 ;
   RECT 354.156000 117.168000 354.240000 117.192000 ;
  END
 END p_q[149]
 PIN p_q[150]
  DIRECTION OUTPUT ;
  USE SIGNAL ;
  PORT
   LAYER M4 ;
   RECT 354.156000 117.360000 354.240000 117.384000 ;
  END
 END p_q[150]
 PIN p_q[151]
  DIRECTION OUTPUT ;
  USE SIGNAL ;
  PORT
   LAYER M4 ;
   RECT 354.156000 117.552000 354.240000 117.576000 ;
  END
 END p_q[151]
 PIN p_q[152]
  DIRECTION OUTPUT ;
  USE SIGNAL ;
  PORT
   LAYER M4 ;
   RECT 354.156000 117.744000 354.240000 117.768000 ;
  END
 END p_q[152]
 PIN p_q[153]
  DIRECTION OUTPUT ;
  USE SIGNAL ;
  PORT
   LAYER M4 ;
   RECT 354.156000 117.936000 354.240000 117.960000 ;
  END
 END p_q[153]
 PIN p_q[154]
  DIRECTION OUTPUT ;
  USE SIGNAL ;
  PORT
   LAYER M4 ;
   RECT 354.156000 118.128000 354.240000 118.152000 ;
  END
 END p_q[154]
 PIN p_q[155]
  DIRECTION OUTPUT ;
  USE SIGNAL ;
  PORT
   LAYER M4 ;
   RECT 354.156000 118.320000 354.240000 118.344000 ;
  END
 END p_q[155]
 PIN p_q[156]
  DIRECTION OUTPUT ;
  USE SIGNAL ;
  PORT
   LAYER M4 ;
   RECT 354.156000 118.512000 354.240000 118.536000 ;
  END
 END p_q[156]
 PIN p_q[157]
  DIRECTION OUTPUT ;
  USE SIGNAL ;
  PORT
   LAYER M4 ;
   RECT 354.156000 118.704000 354.240000 118.728000 ;
  END
 END p_q[157]
 PIN p_q[158]
  DIRECTION OUTPUT ;
  USE SIGNAL ;
  PORT
   LAYER M4 ;
   RECT 354.156000 118.896000 354.240000 118.920000 ;
  END
 END p_q[158]
 PIN p_q[159]
  DIRECTION OUTPUT ;
  USE SIGNAL ;
  PORT
   LAYER M4 ;
   RECT 354.156000 119.088000 354.240000 119.112000 ;
  END
 END p_q[159]
 PIN p_q[160]
  DIRECTION OUTPUT ;
  USE SIGNAL ;
  PORT
   LAYER M4 ;
   RECT 354.156000 119.280000 354.240000 119.304000 ;
  END
 END p_q[160]
 PIN p_q[161]
  DIRECTION OUTPUT ;
  USE SIGNAL ;
  PORT
   LAYER M4 ;
   RECT 354.156000 119.472000 354.240000 119.496000 ;
  END
 END p_q[161]
 PIN p_q[162]
  DIRECTION OUTPUT ;
  USE SIGNAL ;
  PORT
   LAYER M4 ;
   RECT 354.156000 119.664000 354.240000 119.688000 ;
  END
 END p_q[162]
 PIN p_q[163]
  DIRECTION OUTPUT ;
  USE SIGNAL ;
  PORT
   LAYER M4 ;
   RECT 354.156000 119.856000 354.240000 119.880000 ;
  END
 END p_q[163]
 PIN p_q[164]
  DIRECTION OUTPUT ;
  USE SIGNAL ;
  PORT
   LAYER M4 ;
   RECT 354.156000 120.048000 354.240000 120.072000 ;
  END
 END p_q[164]
 PIN p_q[165]
  DIRECTION OUTPUT ;
  USE SIGNAL ;
  PORT
   LAYER M4 ;
   RECT 354.156000 120.240000 354.240000 120.264000 ;
  END
 END p_q[165]
 PIN p_q[166]
  DIRECTION OUTPUT ;
  USE SIGNAL ;
  PORT
   LAYER M4 ;
   RECT 354.156000 120.432000 354.240000 120.456000 ;
  END
 END p_q[166]
 PIN p_q[167]
  DIRECTION OUTPUT ;
  USE SIGNAL ;
  PORT
   LAYER M4 ;
   RECT 354.156000 120.624000 354.240000 120.648000 ;
  END
 END p_q[167]
 PIN p_q[168]
  DIRECTION OUTPUT ;
  USE SIGNAL ;
  PORT
   LAYER M4 ;
   RECT 354.156000 120.816000 354.240000 120.840000 ;
  END
 END p_q[168]
 PIN p_q[169]
  DIRECTION OUTPUT ;
  USE SIGNAL ;
  PORT
   LAYER M4 ;
   RECT 354.156000 121.008000 354.240000 121.032000 ;
  END
 END p_q[169]
 PIN p_q[170]
  DIRECTION OUTPUT ;
  USE SIGNAL ;
  PORT
   LAYER M4 ;
   RECT 354.156000 121.200000 354.240000 121.224000 ;
  END
 END p_q[170]
 PIN p_q[171]
  DIRECTION OUTPUT ;
  USE SIGNAL ;
  PORT
   LAYER M4 ;
   RECT 354.156000 121.392000 354.240000 121.416000 ;
  END
 END p_q[171]
 PIN p_q[172]
  DIRECTION OUTPUT ;
  USE SIGNAL ;
  PORT
   LAYER M4 ;
   RECT 354.156000 121.584000 354.240000 121.608000 ;
  END
 END p_q[172]
 PIN p_q[173]
  DIRECTION OUTPUT ;
  USE SIGNAL ;
  PORT
   LAYER M4 ;
   RECT 354.156000 121.776000 354.240000 121.800000 ;
  END
 END p_q[173]
 PIN p_q[174]
  DIRECTION OUTPUT ;
  USE SIGNAL ;
  PORT
   LAYER M4 ;
   RECT 354.156000 121.968000 354.240000 121.992000 ;
  END
 END p_q[174]
 PIN p_q[175]
  DIRECTION OUTPUT ;
  USE SIGNAL ;
  PORT
   LAYER M4 ;
   RECT 354.156000 122.160000 354.240000 122.184000 ;
  END
 END p_q[175]
 PIN p_q[176]
  DIRECTION OUTPUT ;
  USE SIGNAL ;
  PORT
   LAYER M4 ;
   RECT 354.156000 122.352000 354.240000 122.376000 ;
  END
 END p_q[176]
 PIN p_q[177]
  DIRECTION OUTPUT ;
  USE SIGNAL ;
  PORT
   LAYER M4 ;
   RECT 354.156000 122.544000 354.240000 122.568000 ;
  END
 END p_q[177]
 PIN p_q[178]
  DIRECTION OUTPUT ;
  USE SIGNAL ;
  PORT
   LAYER M4 ;
   RECT 354.156000 122.736000 354.240000 122.760000 ;
  END
 END p_q[178]
 PIN p_q[179]
  DIRECTION OUTPUT ;
  USE SIGNAL ;
  PORT
   LAYER M4 ;
   RECT 354.156000 122.928000 354.240000 122.952000 ;
  END
 END p_q[179]
 PIN p_q[180]
  DIRECTION OUTPUT ;
  USE SIGNAL ;
  PORT
   LAYER M4 ;
   RECT 354.156000 123.120000 354.240000 123.144000 ;
  END
 END p_q[180]
 PIN p_q[181]
  DIRECTION OUTPUT ;
  USE SIGNAL ;
  PORT
   LAYER M4 ;
   RECT 354.156000 123.312000 354.240000 123.336000 ;
  END
 END p_q[181]
 PIN p_q[182]
  DIRECTION OUTPUT ;
  USE SIGNAL ;
  PORT
   LAYER M4 ;
   RECT 354.156000 123.504000 354.240000 123.528000 ;
  END
 END p_q[182]
 PIN p_q[183]
  DIRECTION OUTPUT ;
  USE SIGNAL ;
  PORT
   LAYER M4 ;
   RECT 354.156000 123.696000 354.240000 123.720000 ;
  END
 END p_q[183]
 PIN p_q[184]
  DIRECTION OUTPUT ;
  USE SIGNAL ;
  PORT
   LAYER M4 ;
   RECT 354.156000 123.888000 354.240000 123.912000 ;
  END
 END p_q[184]
 PIN p_q[185]
  DIRECTION OUTPUT ;
  USE SIGNAL ;
  PORT
   LAYER M4 ;
   RECT 354.156000 124.080000 354.240000 124.104000 ;
  END
 END p_q[185]
 PIN p_q[186]
  DIRECTION OUTPUT ;
  USE SIGNAL ;
  PORT
   LAYER M4 ;
   RECT 354.156000 124.272000 354.240000 124.296000 ;
  END
 END p_q[186]
 PIN p_q[187]
  DIRECTION OUTPUT ;
  USE SIGNAL ;
  PORT
   LAYER M4 ;
   RECT 354.156000 124.464000 354.240000 124.488000 ;
  END
 END p_q[187]
 PIN p_q[188]
  DIRECTION OUTPUT ;
  USE SIGNAL ;
  PORT
   LAYER M4 ;
   RECT 354.156000 124.656000 354.240000 124.680000 ;
  END
 END p_q[188]
 PIN p_q[189]
  DIRECTION OUTPUT ;
  USE SIGNAL ;
  PORT
   LAYER M4 ;
   RECT 354.156000 124.848000 354.240000 124.872000 ;
  END
 END p_q[189]
 PIN p_q[190]
  DIRECTION OUTPUT ;
  USE SIGNAL ;
  PORT
   LAYER M4 ;
   RECT 354.156000 125.040000 354.240000 125.064000 ;
  END
 END p_q[190]
 PIN p_q[191]
  DIRECTION OUTPUT ;
  USE SIGNAL ;
  PORT
   LAYER M4 ;
   RECT 354.156000 125.232000 354.240000 125.256000 ;
  END
 END p_q[191]
 PIN p_q[192]
  DIRECTION OUTPUT ;
  USE SIGNAL ;
  PORT
   LAYER M4 ;
   RECT 354.156000 125.424000 354.240000 125.448000 ;
  END
 END p_q[192]
 PIN p_q[193]
  DIRECTION OUTPUT ;
  USE SIGNAL ;
  PORT
   LAYER M4 ;
   RECT 354.156000 125.616000 354.240000 125.640000 ;
  END
 END p_q[193]
 PIN p_q[194]
  DIRECTION OUTPUT ;
  USE SIGNAL ;
  PORT
   LAYER M4 ;
   RECT 354.156000 125.808000 354.240000 125.832000 ;
  END
 END p_q[194]
 PIN p_q[195]
  DIRECTION OUTPUT ;
  USE SIGNAL ;
  PORT
   LAYER M4 ;
   RECT 354.156000 126.000000 354.240000 126.024000 ;
  END
 END p_q[195]
 PIN p_q[196]
  DIRECTION OUTPUT ;
  USE SIGNAL ;
  PORT
   LAYER M4 ;
   RECT 354.156000 126.192000 354.240000 126.216000 ;
  END
 END p_q[196]
 PIN p_q[197]
  DIRECTION OUTPUT ;
  USE SIGNAL ;
  PORT
   LAYER M4 ;
   RECT 354.156000 126.384000 354.240000 126.408000 ;
  END
 END p_q[197]
 PIN p_q[198]
  DIRECTION OUTPUT ;
  USE SIGNAL ;
  PORT
   LAYER M4 ;
   RECT 354.156000 126.576000 354.240000 126.600000 ;
  END
 END p_q[198]
 PIN p_q[199]
  DIRECTION OUTPUT ;
  USE SIGNAL ;
  PORT
   LAYER M4 ;
   RECT 354.156000 126.768000 354.240000 126.792000 ;
  END
 END p_q[199]
 PIN p_q[200]
  DIRECTION OUTPUT ;
  USE SIGNAL ;
  PORT
   LAYER M4 ;
   RECT 354.156000 126.960000 354.240000 126.984000 ;
  END
 END p_q[200]
 PIN p_q[201]
  DIRECTION OUTPUT ;
  USE SIGNAL ;
  PORT
   LAYER M4 ;
   RECT 354.156000 127.152000 354.240000 127.176000 ;
  END
 END p_q[201]
 PIN p_q[202]
  DIRECTION OUTPUT ;
  USE SIGNAL ;
  PORT
   LAYER M4 ;
   RECT 354.156000 127.344000 354.240000 127.368000 ;
  END
 END p_q[202]
 PIN p_q[203]
  DIRECTION OUTPUT ;
  USE SIGNAL ;
  PORT
   LAYER M4 ;
   RECT 354.156000 127.536000 354.240000 127.560000 ;
  END
 END p_q[203]
 PIN p_q[204]
  DIRECTION OUTPUT ;
  USE SIGNAL ;
  PORT
   LAYER M4 ;
   RECT 354.156000 127.728000 354.240000 127.752000 ;
  END
 END p_q[204]
 PIN p_q[205]
  DIRECTION OUTPUT ;
  USE SIGNAL ;
  PORT
   LAYER M4 ;
   RECT 354.156000 127.920000 354.240000 127.944000 ;
  END
 END p_q[205]
 PIN p_q[206]
  DIRECTION OUTPUT ;
  USE SIGNAL ;
  PORT
   LAYER M4 ;
   RECT 354.156000 128.112000 354.240000 128.136000 ;
  END
 END p_q[206]
 PIN p_q[207]
  DIRECTION OUTPUT ;
  USE SIGNAL ;
  PORT
   LAYER M4 ;
   RECT 354.156000 128.304000 354.240000 128.328000 ;
  END
 END p_q[207]
 PIN p_q[208]
  DIRECTION OUTPUT ;
  USE SIGNAL ;
  PORT
   LAYER M4 ;
   RECT 354.156000 128.496000 354.240000 128.520000 ;
  END
 END p_q[208]
 PIN p_q[209]
  DIRECTION OUTPUT ;
  USE SIGNAL ;
  PORT
   LAYER M4 ;
   RECT 354.156000 128.688000 354.240000 128.712000 ;
  END
 END p_q[209]
 PIN p_q[210]
  DIRECTION OUTPUT ;
  USE SIGNAL ;
  PORT
   LAYER M4 ;
   RECT 354.156000 128.880000 354.240000 128.904000 ;
  END
 END p_q[210]
 PIN p_q[211]
  DIRECTION OUTPUT ;
  USE SIGNAL ;
  PORT
   LAYER M4 ;
   RECT 354.156000 129.072000 354.240000 129.096000 ;
  END
 END p_q[211]
 PIN p_q[212]
  DIRECTION OUTPUT ;
  USE SIGNAL ;
  PORT
   LAYER M4 ;
   RECT 354.156000 129.264000 354.240000 129.288000 ;
  END
 END p_q[212]
 PIN p_q[213]
  DIRECTION OUTPUT ;
  USE SIGNAL ;
  PORT
   LAYER M4 ;
   RECT 354.156000 129.456000 354.240000 129.480000 ;
  END
 END p_q[213]
 PIN p_q[214]
  DIRECTION OUTPUT ;
  USE SIGNAL ;
  PORT
   LAYER M4 ;
   RECT 354.156000 129.648000 354.240000 129.672000 ;
  END
 END p_q[214]
 PIN p_q[215]
  DIRECTION OUTPUT ;
  USE SIGNAL ;
  PORT
   LAYER M4 ;
   RECT 354.156000 129.840000 354.240000 129.864000 ;
  END
 END p_q[215]
 PIN p_q[216]
  DIRECTION OUTPUT ;
  USE SIGNAL ;
  PORT
   LAYER M4 ;
   RECT 354.156000 130.032000 354.240000 130.056000 ;
  END
 END p_q[216]
 PIN p_q[217]
  DIRECTION OUTPUT ;
  USE SIGNAL ;
  PORT
   LAYER M4 ;
   RECT 354.156000 130.224000 354.240000 130.248000 ;
  END
 END p_q[217]
 PIN p_q[218]
  DIRECTION OUTPUT ;
  USE SIGNAL ;
  PORT
   LAYER M4 ;
   RECT 354.156000 130.416000 354.240000 130.440000 ;
  END
 END p_q[218]
 PIN p_q[219]
  DIRECTION OUTPUT ;
  USE SIGNAL ;
  PORT
   LAYER M4 ;
   RECT 354.156000 130.608000 354.240000 130.632000 ;
  END
 END p_q[219]
 PIN p_q[220]
  DIRECTION OUTPUT ;
  USE SIGNAL ;
  PORT
   LAYER M4 ;
   RECT 354.156000 130.800000 354.240000 130.824000 ;
  END
 END p_q[220]
 PIN p_q[221]
  DIRECTION OUTPUT ;
  USE SIGNAL ;
  PORT
   LAYER M4 ;
   RECT 354.156000 130.992000 354.240000 131.016000 ;
  END
 END p_q[221]
 PIN p_q[222]
  DIRECTION OUTPUT ;
  USE SIGNAL ;
  PORT
   LAYER M4 ;
   RECT 354.156000 131.184000 354.240000 131.208000 ;
  END
 END p_q[222]
 PIN p_q[223]
  DIRECTION OUTPUT ;
  USE SIGNAL ;
  PORT
   LAYER M4 ;
   RECT 354.156000 131.376000 354.240000 131.400000 ;
  END
 END p_q[223]
 PIN p_q[224]
  DIRECTION OUTPUT ;
  USE SIGNAL ;
  PORT
   LAYER M4 ;
   RECT 354.156000 131.568000 354.240000 131.592000 ;
  END
 END p_q[224]
 PIN p_q[225]
  DIRECTION OUTPUT ;
  USE SIGNAL ;
  PORT
   LAYER M4 ;
   RECT 354.156000 131.760000 354.240000 131.784000 ;
  END
 END p_q[225]
 PIN p_q[226]
  DIRECTION OUTPUT ;
  USE SIGNAL ;
  PORT
   LAYER M4 ;
   RECT 354.156000 131.952000 354.240000 131.976000 ;
  END
 END p_q[226]
 PIN p_q[227]
  DIRECTION OUTPUT ;
  USE SIGNAL ;
  PORT
   LAYER M4 ;
   RECT 354.156000 132.144000 354.240000 132.168000 ;
  END
 END p_q[227]
 PIN p_q[228]
  DIRECTION OUTPUT ;
  USE SIGNAL ;
  PORT
   LAYER M4 ;
   RECT 354.156000 132.336000 354.240000 132.360000 ;
  END
 END p_q[228]
 PIN p_q[229]
  DIRECTION OUTPUT ;
  USE SIGNAL ;
  PORT
   LAYER M4 ;
   RECT 354.156000 132.528000 354.240000 132.552000 ;
  END
 END p_q[229]
 PIN p_q[230]
  DIRECTION OUTPUT ;
  USE SIGNAL ;
  PORT
   LAYER M4 ;
   RECT 354.156000 132.720000 354.240000 132.744000 ;
  END
 END p_q[230]
 PIN p_q[231]
  DIRECTION OUTPUT ;
  USE SIGNAL ;
  PORT
   LAYER M4 ;
   RECT 354.156000 132.912000 354.240000 132.936000 ;
  END
 END p_q[231]
 PIN p_q[232]
  DIRECTION OUTPUT ;
  USE SIGNAL ;
  PORT
   LAYER M4 ;
   RECT 354.156000 133.104000 354.240000 133.128000 ;
  END
 END p_q[232]
 PIN p_q[233]
  DIRECTION OUTPUT ;
  USE SIGNAL ;
  PORT
   LAYER M4 ;
   RECT 354.156000 133.296000 354.240000 133.320000 ;
  END
 END p_q[233]
 PIN p_q[234]
  DIRECTION OUTPUT ;
  USE SIGNAL ;
  PORT
   LAYER M4 ;
   RECT 354.156000 133.488000 354.240000 133.512000 ;
  END
 END p_q[234]
 PIN p_q[235]
  DIRECTION OUTPUT ;
  USE SIGNAL ;
  PORT
   LAYER M4 ;
   RECT 354.156000 133.680000 354.240000 133.704000 ;
  END
 END p_q[235]
 PIN p_q[236]
  DIRECTION OUTPUT ;
  USE SIGNAL ;
  PORT
   LAYER M4 ;
   RECT 354.156000 133.872000 354.240000 133.896000 ;
  END
 END p_q[236]
 PIN p_q[237]
  DIRECTION OUTPUT ;
  USE SIGNAL ;
  PORT
   LAYER M4 ;
   RECT 354.156000 134.064000 354.240000 134.088000 ;
  END
 END p_q[237]
 PIN p_q[238]
  DIRECTION OUTPUT ;
  USE SIGNAL ;
  PORT
   LAYER M4 ;
   RECT 354.156000 134.256000 354.240000 134.280000 ;
  END
 END p_q[238]
 PIN p_q[239]
  DIRECTION OUTPUT ;
  USE SIGNAL ;
  PORT
   LAYER M4 ;
   RECT 354.156000 134.448000 354.240000 134.472000 ;
  END
 END p_q[239]
 PIN p_q[240]
  DIRECTION OUTPUT ;
  USE SIGNAL ;
  PORT
   LAYER M4 ;
   RECT 354.156000 134.640000 354.240000 134.664000 ;
  END
 END p_q[240]
 PIN p_q[241]
  DIRECTION OUTPUT ;
  USE SIGNAL ;
  PORT
   LAYER M4 ;
   RECT 354.156000 134.832000 354.240000 134.856000 ;
  END
 END p_q[241]
 PIN p_q[242]
  DIRECTION OUTPUT ;
  USE SIGNAL ;
  PORT
   LAYER M4 ;
   RECT 354.156000 135.024000 354.240000 135.048000 ;
  END
 END p_q[242]
 PIN p_q[243]
  DIRECTION OUTPUT ;
  USE SIGNAL ;
  PORT
   LAYER M4 ;
   RECT 354.156000 135.216000 354.240000 135.240000 ;
  END
 END p_q[243]
 PIN p_q[244]
  DIRECTION OUTPUT ;
  USE SIGNAL ;
  PORT
   LAYER M4 ;
   RECT 354.156000 135.408000 354.240000 135.432000 ;
  END
 END p_q[244]
 PIN p_q[245]
  DIRECTION OUTPUT ;
  USE SIGNAL ;
  PORT
   LAYER M4 ;
   RECT 354.156000 135.600000 354.240000 135.624000 ;
  END
 END p_q[245]
 PIN p_q[246]
  DIRECTION OUTPUT ;
  USE SIGNAL ;
  PORT
   LAYER M4 ;
   RECT 354.156000 135.792000 354.240000 135.816000 ;
  END
 END p_q[246]
 PIN p_q[247]
  DIRECTION OUTPUT ;
  USE SIGNAL ;
  PORT
   LAYER M4 ;
   RECT 354.156000 135.984000 354.240000 136.008000 ;
  END
 END p_q[247]
 PIN p_q[248]
  DIRECTION OUTPUT ;
  USE SIGNAL ;
  PORT
   LAYER M4 ;
   RECT 354.156000 136.176000 354.240000 136.200000 ;
  END
 END p_q[248]
 PIN p_q[249]
  DIRECTION OUTPUT ;
  USE SIGNAL ;
  PORT
   LAYER M4 ;
   RECT 354.156000 136.368000 354.240000 136.392000 ;
  END
 END p_q[249]
 PIN p_q[250]
  DIRECTION OUTPUT ;
  USE SIGNAL ;
  PORT
   LAYER M4 ;
   RECT 354.156000 136.560000 354.240000 136.584000 ;
  END
 END p_q[250]
 PIN p_q[251]
  DIRECTION OUTPUT ;
  USE SIGNAL ;
  PORT
   LAYER M4 ;
   RECT 354.156000 136.752000 354.240000 136.776000 ;
  END
 END p_q[251]
 PIN p_q[252]
  DIRECTION OUTPUT ;
  USE SIGNAL ;
  PORT
   LAYER M4 ;
   RECT 354.156000 136.944000 354.240000 136.968000 ;
  END
 END p_q[252]
 PIN p_q[253]
  DIRECTION OUTPUT ;
  USE SIGNAL ;
  PORT
   LAYER M4 ;
   RECT 354.156000 137.136000 354.240000 137.160000 ;
  END
 END p_q[253]
 PIN p_q[254]
  DIRECTION OUTPUT ;
  USE SIGNAL ;
  PORT
   LAYER M4 ;
   RECT 354.156000 137.328000 354.240000 137.352000 ;
  END
 END p_q[254]
 PIN p_q[255]
  DIRECTION OUTPUT ;
  USE SIGNAL ;
  PORT
   LAYER M4 ;
   RECT 354.156000 137.520000 354.240000 137.544000 ;
  END
 END p_q[255]
 PIN p_q[256]
  DIRECTION OUTPUT ;
  USE SIGNAL ;
  PORT
   LAYER M4 ;
   RECT 354.156000 137.712000 354.240000 137.736000 ;
  END
 END p_q[256]
 PIN p_q[257]
  DIRECTION OUTPUT ;
  USE SIGNAL ;
  PORT
   LAYER M4 ;
   RECT 354.156000 137.904000 354.240000 137.928000 ;
  END
 END p_q[257]
 PIN p_q[258]
  DIRECTION OUTPUT ;
  USE SIGNAL ;
  PORT
   LAYER M4 ;
   RECT 354.156000 138.096000 354.240000 138.120000 ;
  END
 END p_q[258]
 PIN p_q[259]
  DIRECTION OUTPUT ;
  USE SIGNAL ;
  PORT
   LAYER M4 ;
   RECT 354.156000 138.288000 354.240000 138.312000 ;
  END
 END p_q[259]
 PIN p_q[260]
  DIRECTION OUTPUT ;
  USE SIGNAL ;
  PORT
   LAYER M4 ;
   RECT 354.156000 138.480000 354.240000 138.504000 ;
  END
 END p_q[260]
 PIN p_q[261]
  DIRECTION OUTPUT ;
  USE SIGNAL ;
  PORT
   LAYER M4 ;
   RECT 354.156000 138.672000 354.240000 138.696000 ;
  END
 END p_q[261]
 PIN p_q[262]
  DIRECTION OUTPUT ;
  USE SIGNAL ;
  PORT
   LAYER M4 ;
   RECT 354.156000 138.864000 354.240000 138.888000 ;
  END
 END p_q[262]
 PIN p_q[263]
  DIRECTION OUTPUT ;
  USE SIGNAL ;
  PORT
   LAYER M4 ;
   RECT 354.156000 139.056000 354.240000 139.080000 ;
  END
 END p_q[263]
 PIN p_q[264]
  DIRECTION OUTPUT ;
  USE SIGNAL ;
  PORT
   LAYER M4 ;
   RECT 354.156000 139.248000 354.240000 139.272000 ;
  END
 END p_q[264]
 PIN p_q[265]
  DIRECTION OUTPUT ;
  USE SIGNAL ;
  PORT
   LAYER M4 ;
   RECT 354.156000 139.440000 354.240000 139.464000 ;
  END
 END p_q[265]
 PIN p_q[266]
  DIRECTION OUTPUT ;
  USE SIGNAL ;
  PORT
   LAYER M4 ;
   RECT 354.156000 139.632000 354.240000 139.656000 ;
  END
 END p_q[266]
 PIN p_q[267]
  DIRECTION OUTPUT ;
  USE SIGNAL ;
  PORT
   LAYER M4 ;
   RECT 354.156000 139.824000 354.240000 139.848000 ;
  END
 END p_q[267]
 PIN p_q[268]
  DIRECTION OUTPUT ;
  USE SIGNAL ;
  PORT
   LAYER M4 ;
   RECT 354.156000 140.016000 354.240000 140.040000 ;
  END
 END p_q[268]
 PIN p_q[269]
  DIRECTION OUTPUT ;
  USE SIGNAL ;
  PORT
   LAYER M4 ;
   RECT 354.156000 140.208000 354.240000 140.232000 ;
  END
 END p_q[269]
 PIN p_q[270]
  DIRECTION OUTPUT ;
  USE SIGNAL ;
  PORT
   LAYER M4 ;
   RECT 354.156000 140.400000 354.240000 140.424000 ;
  END
 END p_q[270]
 PIN p_q[271]
  DIRECTION OUTPUT ;
  USE SIGNAL ;
  PORT
   LAYER M4 ;
   RECT 354.156000 140.592000 354.240000 140.616000 ;
  END
 END p_q[271]
 PIN p_q[272]
  DIRECTION OUTPUT ;
  USE SIGNAL ;
  PORT
   LAYER M4 ;
   RECT 354.156000 140.784000 354.240000 140.808000 ;
  END
 END p_q[272]
 PIN p_q[273]
  DIRECTION OUTPUT ;
  USE SIGNAL ;
  PORT
   LAYER M4 ;
   RECT 354.156000 140.976000 354.240000 141.000000 ;
  END
 END p_q[273]
 PIN p_q[274]
  DIRECTION OUTPUT ;
  USE SIGNAL ;
  PORT
   LAYER M4 ;
   RECT 354.156000 141.168000 354.240000 141.192000 ;
  END
 END p_q[274]
 PIN p_q[275]
  DIRECTION OUTPUT ;
  USE SIGNAL ;
  PORT
   LAYER M4 ;
   RECT 354.156000 141.360000 354.240000 141.384000 ;
  END
 END p_q[275]
 PIN p_q[276]
  DIRECTION OUTPUT ;
  USE SIGNAL ;
  PORT
   LAYER M4 ;
   RECT 354.156000 141.552000 354.240000 141.576000 ;
  END
 END p_q[276]
 PIN p_q[277]
  DIRECTION OUTPUT ;
  USE SIGNAL ;
  PORT
   LAYER M4 ;
   RECT 354.156000 141.744000 354.240000 141.768000 ;
  END
 END p_q[277]
 PIN p_q[278]
  DIRECTION OUTPUT ;
  USE SIGNAL ;
  PORT
   LAYER M4 ;
   RECT 354.156000 141.936000 354.240000 141.960000 ;
  END
 END p_q[278]
 PIN p_q[279]
  DIRECTION OUTPUT ;
  USE SIGNAL ;
  PORT
   LAYER M4 ;
   RECT 354.156000 142.128000 354.240000 142.152000 ;
  END
 END p_q[279]
 PIN p_q[280]
  DIRECTION OUTPUT ;
  USE SIGNAL ;
  PORT
   LAYER M4 ;
   RECT 354.156000 142.320000 354.240000 142.344000 ;
  END
 END p_q[280]
 PIN p_q[281]
  DIRECTION OUTPUT ;
  USE SIGNAL ;
  PORT
   LAYER M4 ;
   RECT 354.156000 142.512000 354.240000 142.536000 ;
  END
 END p_q[281]
 PIN p_q[282]
  DIRECTION OUTPUT ;
  USE SIGNAL ;
  PORT
   LAYER M4 ;
   RECT 354.156000 142.704000 354.240000 142.728000 ;
  END
 END p_q[282]
 PIN p_q[283]
  DIRECTION OUTPUT ;
  USE SIGNAL ;
  PORT
   LAYER M4 ;
   RECT 354.156000 142.896000 354.240000 142.920000 ;
  END
 END p_q[283]
 PIN p_q[284]
  DIRECTION OUTPUT ;
  USE SIGNAL ;
  PORT
   LAYER M4 ;
   RECT 354.156000 143.088000 354.240000 143.112000 ;
  END
 END p_q[284]
 PIN p_q[285]
  DIRECTION OUTPUT ;
  USE SIGNAL ;
  PORT
   LAYER M4 ;
   RECT 354.156000 143.280000 354.240000 143.304000 ;
  END
 END p_q[285]
 PIN p_q[286]
  DIRECTION OUTPUT ;
  USE SIGNAL ;
  PORT
   LAYER M4 ;
   RECT 354.156000 143.472000 354.240000 143.496000 ;
  END
 END p_q[286]
 PIN p_q[287]
  DIRECTION OUTPUT ;
  USE SIGNAL ;
  PORT
   LAYER M4 ;
   RECT 354.156000 143.664000 354.240000 143.688000 ;
  END
 END p_q[287]
 PIN p_q[288]
  DIRECTION OUTPUT ;
  USE SIGNAL ;
  PORT
   LAYER M4 ;
   RECT 354.156000 143.856000 354.240000 143.880000 ;
  END
 END p_q[288]
 PIN p_q[289]
  DIRECTION OUTPUT ;
  USE SIGNAL ;
  PORT
   LAYER M4 ;
   RECT 354.156000 144.048000 354.240000 144.072000 ;
  END
 END p_q[289]
 PIN p_q[290]
  DIRECTION OUTPUT ;
  USE SIGNAL ;
  PORT
   LAYER M4 ;
   RECT 354.156000 144.240000 354.240000 144.264000 ;
  END
 END p_q[290]
 PIN p_q[291]
  DIRECTION OUTPUT ;
  USE SIGNAL ;
  PORT
   LAYER M4 ;
   RECT 354.156000 144.432000 354.240000 144.456000 ;
  END
 END p_q[291]
 PIN p_q[292]
  DIRECTION OUTPUT ;
  USE SIGNAL ;
  PORT
   LAYER M4 ;
   RECT 354.156000 144.624000 354.240000 144.648000 ;
  END
 END p_q[292]
 PIN p_q[293]
  DIRECTION OUTPUT ;
  USE SIGNAL ;
  PORT
   LAYER M4 ;
   RECT 354.156000 144.816000 354.240000 144.840000 ;
  END
 END p_q[293]
 PIN p_q[294]
  DIRECTION OUTPUT ;
  USE SIGNAL ;
  PORT
   LAYER M4 ;
   RECT 354.156000 145.008000 354.240000 145.032000 ;
  END
 END p_q[294]
 PIN p_q[295]
  DIRECTION OUTPUT ;
  USE SIGNAL ;
  PORT
   LAYER M4 ;
   RECT 354.156000 145.200000 354.240000 145.224000 ;
  END
 END p_q[295]
 PIN p_q[296]
  DIRECTION OUTPUT ;
  USE SIGNAL ;
  PORT
   LAYER M4 ;
   RECT 354.156000 145.392000 354.240000 145.416000 ;
  END
 END p_q[296]
 PIN p_q[297]
  DIRECTION OUTPUT ;
  USE SIGNAL ;
  PORT
   LAYER M4 ;
   RECT 354.156000 145.584000 354.240000 145.608000 ;
  END
 END p_q[297]
 PIN p_q[298]
  DIRECTION OUTPUT ;
  USE SIGNAL ;
  PORT
   LAYER M4 ;
   RECT 354.156000 145.776000 354.240000 145.800000 ;
  END
 END p_q[298]
 PIN p_q[299]
  DIRECTION OUTPUT ;
  USE SIGNAL ;
  PORT
   LAYER M4 ;
   RECT 354.156000 145.968000 354.240000 145.992000 ;
  END
 END p_q[299]
 PIN p_q[300]
  DIRECTION OUTPUT ;
  USE SIGNAL ;
  PORT
   LAYER M4 ;
   RECT 354.156000 146.160000 354.240000 146.184000 ;
  END
 END p_q[300]
 PIN p_q[301]
  DIRECTION OUTPUT ;
  USE SIGNAL ;
  PORT
   LAYER M4 ;
   RECT 354.156000 146.352000 354.240000 146.376000 ;
  END
 END p_q[301]
 PIN p_q[302]
  DIRECTION OUTPUT ;
  USE SIGNAL ;
  PORT
   LAYER M4 ;
   RECT 354.156000 146.544000 354.240000 146.568000 ;
  END
 END p_q[302]
 PIN p_q[303]
  DIRECTION OUTPUT ;
  USE SIGNAL ;
  PORT
   LAYER M4 ;
   RECT 354.156000 146.736000 354.240000 146.760000 ;
  END
 END p_q[303]
 PIN p_q[304]
  DIRECTION OUTPUT ;
  USE SIGNAL ;
  PORT
   LAYER M4 ;
   RECT 354.156000 146.928000 354.240000 146.952000 ;
  END
 END p_q[304]
 PIN p_q[305]
  DIRECTION OUTPUT ;
  USE SIGNAL ;
  PORT
   LAYER M4 ;
   RECT 354.156000 147.120000 354.240000 147.144000 ;
  END
 END p_q[305]
 PIN p_q[306]
  DIRECTION OUTPUT ;
  USE SIGNAL ;
  PORT
   LAYER M4 ;
   RECT 354.156000 147.312000 354.240000 147.336000 ;
  END
 END p_q[306]
 PIN p_q[307]
  DIRECTION OUTPUT ;
  USE SIGNAL ;
  PORT
   LAYER M4 ;
   RECT 354.156000 147.504000 354.240000 147.528000 ;
  END
 END p_q[307]
 PIN p_q[308]
  DIRECTION OUTPUT ;
  USE SIGNAL ;
  PORT
   LAYER M4 ;
   RECT 354.156000 147.696000 354.240000 147.720000 ;
  END
 END p_q[308]
 PIN p_q[309]
  DIRECTION OUTPUT ;
  USE SIGNAL ;
  PORT
   LAYER M4 ;
   RECT 354.156000 147.888000 354.240000 147.912000 ;
  END
 END p_q[309]
 PIN p_q[310]
  DIRECTION OUTPUT ;
  USE SIGNAL ;
  PORT
   LAYER M4 ;
   RECT 354.156000 148.080000 354.240000 148.104000 ;
  END
 END p_q[310]
 PIN p_q[311]
  DIRECTION OUTPUT ;
  USE SIGNAL ;
  PORT
   LAYER M4 ;
   RECT 354.156000 148.272000 354.240000 148.296000 ;
  END
 END p_q[311]
 PIN p_q[312]
  DIRECTION OUTPUT ;
  USE SIGNAL ;
  PORT
   LAYER M4 ;
   RECT 354.156000 148.464000 354.240000 148.488000 ;
  END
 END p_q[312]
 PIN p_q[313]
  DIRECTION OUTPUT ;
  USE SIGNAL ;
  PORT
   LAYER M4 ;
   RECT 354.156000 148.656000 354.240000 148.680000 ;
  END
 END p_q[313]
 PIN p_q[314]
  DIRECTION OUTPUT ;
  USE SIGNAL ;
  PORT
   LAYER M4 ;
   RECT 354.156000 148.848000 354.240000 148.872000 ;
  END
 END p_q[314]
 PIN p_q[315]
  DIRECTION OUTPUT ;
  USE SIGNAL ;
  PORT
   LAYER M4 ;
   RECT 354.156000 149.040000 354.240000 149.064000 ;
  END
 END p_q[315]
 PIN p_q[316]
  DIRECTION OUTPUT ;
  USE SIGNAL ;
  PORT
   LAYER M4 ;
   RECT 354.156000 149.232000 354.240000 149.256000 ;
  END
 END p_q[316]
 PIN p_q[317]
  DIRECTION OUTPUT ;
  USE SIGNAL ;
  PORT
   LAYER M4 ;
   RECT 354.156000 149.424000 354.240000 149.448000 ;
  END
 END p_q[317]
 PIN p_q[318]
  DIRECTION OUTPUT ;
  USE SIGNAL ;
  PORT
   LAYER M4 ;
   RECT 354.156000 149.616000 354.240000 149.640000 ;
  END
 END p_q[318]
 PIN p_q[319]
  DIRECTION OUTPUT ;
  USE SIGNAL ;
  PORT
   LAYER M4 ;
   RECT 354.156000 149.808000 354.240000 149.832000 ;
  END
 END p_q[319]
 PIN p_q[320]
  DIRECTION OUTPUT ;
  USE SIGNAL ;
  PORT
   LAYER M4 ;
   RECT 354.156000 150.000000 354.240000 150.024000 ;
  END
 END p_q[320]
 PIN p_q[321]
  DIRECTION OUTPUT ;
  USE SIGNAL ;
  PORT
   LAYER M4 ;
   RECT 354.156000 150.192000 354.240000 150.216000 ;
  END
 END p_q[321]
 PIN p_q[322]
  DIRECTION OUTPUT ;
  USE SIGNAL ;
  PORT
   LAYER M4 ;
   RECT 354.156000 150.384000 354.240000 150.408000 ;
  END
 END p_q[322]
 PIN p_q[323]
  DIRECTION OUTPUT ;
  USE SIGNAL ;
  PORT
   LAYER M4 ;
   RECT 354.156000 150.576000 354.240000 150.600000 ;
  END
 END p_q[323]
 PIN p_q[324]
  DIRECTION OUTPUT ;
  USE SIGNAL ;
  PORT
   LAYER M4 ;
   RECT 354.156000 150.768000 354.240000 150.792000 ;
  END
 END p_q[324]
 PIN p_q[325]
  DIRECTION OUTPUT ;
  USE SIGNAL ;
  PORT
   LAYER M4 ;
   RECT 354.156000 150.960000 354.240000 150.984000 ;
  END
 END p_q[325]
 PIN p_q[326]
  DIRECTION OUTPUT ;
  USE SIGNAL ;
  PORT
   LAYER M4 ;
   RECT 354.156000 151.152000 354.240000 151.176000 ;
  END
 END p_q[326]
 PIN p_q[327]
  DIRECTION OUTPUT ;
  USE SIGNAL ;
  PORT
   LAYER M4 ;
   RECT 354.156000 151.344000 354.240000 151.368000 ;
  END
 END p_q[327]
 PIN p_q[328]
  DIRECTION OUTPUT ;
  USE SIGNAL ;
  PORT
   LAYER M4 ;
   RECT 354.156000 151.536000 354.240000 151.560000 ;
  END
 END p_q[328]
 PIN p_q[329]
  DIRECTION OUTPUT ;
  USE SIGNAL ;
  PORT
   LAYER M4 ;
   RECT 354.156000 151.728000 354.240000 151.752000 ;
  END
 END p_q[329]
 PIN p_q[330]
  DIRECTION OUTPUT ;
  USE SIGNAL ;
  PORT
   LAYER M4 ;
   RECT 354.156000 151.920000 354.240000 151.944000 ;
  END
 END p_q[330]
 PIN p_q[331]
  DIRECTION OUTPUT ;
  USE SIGNAL ;
  PORT
   LAYER M4 ;
   RECT 354.156000 152.112000 354.240000 152.136000 ;
  END
 END p_q[331]
 PIN p_q[332]
  DIRECTION OUTPUT ;
  USE SIGNAL ;
  PORT
   LAYER M4 ;
   RECT 354.156000 152.304000 354.240000 152.328000 ;
  END
 END p_q[332]
 PIN p_q[333]
  DIRECTION OUTPUT ;
  USE SIGNAL ;
  PORT
   LAYER M4 ;
   RECT 354.156000 152.496000 354.240000 152.520000 ;
  END
 END p_q[333]
 PIN p_q[334]
  DIRECTION OUTPUT ;
  USE SIGNAL ;
  PORT
   LAYER M4 ;
   RECT 354.156000 152.688000 354.240000 152.712000 ;
  END
 END p_q[334]
 PIN p_q[335]
  DIRECTION OUTPUT ;
  USE SIGNAL ;
  PORT
   LAYER M4 ;
   RECT 354.156000 152.880000 354.240000 152.904000 ;
  END
 END p_q[335]
 PIN p_q[336]
  DIRECTION OUTPUT ;
  USE SIGNAL ;
  PORT
   LAYER M4 ;
   RECT 354.156000 153.072000 354.240000 153.096000 ;
  END
 END p_q[336]
 PIN p_q[337]
  DIRECTION OUTPUT ;
  USE SIGNAL ;
  PORT
   LAYER M4 ;
   RECT 354.156000 153.264000 354.240000 153.288000 ;
  END
 END p_q[337]
 PIN p_q[338]
  DIRECTION OUTPUT ;
  USE SIGNAL ;
  PORT
   LAYER M4 ;
   RECT 354.156000 153.456000 354.240000 153.480000 ;
  END
 END p_q[338]
 PIN p_q[339]
  DIRECTION OUTPUT ;
  USE SIGNAL ;
  PORT
   LAYER M4 ;
   RECT 354.156000 153.648000 354.240000 153.672000 ;
  END
 END p_q[339]
 PIN p_q[340]
  DIRECTION OUTPUT ;
  USE SIGNAL ;
  PORT
   LAYER M4 ;
   RECT 354.156000 153.840000 354.240000 153.864000 ;
  END
 END p_q[340]
 PIN p_q[341]
  DIRECTION OUTPUT ;
  USE SIGNAL ;
  PORT
   LAYER M4 ;
   RECT 354.156000 154.032000 354.240000 154.056000 ;
  END
 END p_q[341]
 PIN p_q[342]
  DIRECTION OUTPUT ;
  USE SIGNAL ;
  PORT
   LAYER M4 ;
   RECT 354.156000 154.224000 354.240000 154.248000 ;
  END
 END p_q[342]
 PIN p_q[343]
  DIRECTION OUTPUT ;
  USE SIGNAL ;
  PORT
   LAYER M4 ;
   RECT 354.156000 154.416000 354.240000 154.440000 ;
  END
 END p_q[343]
 PIN p_q[344]
  DIRECTION OUTPUT ;
  USE SIGNAL ;
  PORT
   LAYER M4 ;
   RECT 354.156000 154.608000 354.240000 154.632000 ;
  END
 END p_q[344]
 PIN p_q[345]
  DIRECTION OUTPUT ;
  USE SIGNAL ;
  PORT
   LAYER M4 ;
   RECT 354.156000 154.800000 354.240000 154.824000 ;
  END
 END p_q[345]
 PIN p_q[346]
  DIRECTION OUTPUT ;
  USE SIGNAL ;
  PORT
   LAYER M4 ;
   RECT 354.156000 154.992000 354.240000 155.016000 ;
  END
 END p_q[346]
 PIN p_q[347]
  DIRECTION OUTPUT ;
  USE SIGNAL ;
  PORT
   LAYER M4 ;
   RECT 354.156000 155.184000 354.240000 155.208000 ;
  END
 END p_q[347]
 PIN p_q[348]
  DIRECTION OUTPUT ;
  USE SIGNAL ;
  PORT
   LAYER M4 ;
   RECT 354.156000 155.376000 354.240000 155.400000 ;
  END
 END p_q[348]
 PIN p_q[349]
  DIRECTION OUTPUT ;
  USE SIGNAL ;
  PORT
   LAYER M4 ;
   RECT 354.156000 155.568000 354.240000 155.592000 ;
  END
 END p_q[349]
 PIN p_q[350]
  DIRECTION OUTPUT ;
  USE SIGNAL ;
  PORT
   LAYER M4 ;
   RECT 354.156000 155.760000 354.240000 155.784000 ;
  END
 END p_q[350]
 PIN p_q[351]
  DIRECTION OUTPUT ;
  USE SIGNAL ;
  PORT
   LAYER M4 ;
   RECT 354.156000 155.952000 354.240000 155.976000 ;
  END
 END p_q[351]
 PIN p_q[352]
  DIRECTION OUTPUT ;
  USE SIGNAL ;
  PORT
   LAYER M4 ;
   RECT 354.156000 156.144000 354.240000 156.168000 ;
  END
 END p_q[352]
 PIN p_q[353]
  DIRECTION OUTPUT ;
  USE SIGNAL ;
  PORT
   LAYER M4 ;
   RECT 354.156000 156.336000 354.240000 156.360000 ;
  END
 END p_q[353]
 PIN p_q[354]
  DIRECTION OUTPUT ;
  USE SIGNAL ;
  PORT
   LAYER M4 ;
   RECT 354.156000 156.528000 354.240000 156.552000 ;
  END
 END p_q[354]
 PIN p_q[355]
  DIRECTION OUTPUT ;
  USE SIGNAL ;
  PORT
   LAYER M4 ;
   RECT 354.156000 156.720000 354.240000 156.744000 ;
  END
 END p_q[355]
 PIN p_q[356]
  DIRECTION OUTPUT ;
  USE SIGNAL ;
  PORT
   LAYER M4 ;
   RECT 354.156000 156.912000 354.240000 156.936000 ;
  END
 END p_q[356]
 PIN p_q[357]
  DIRECTION OUTPUT ;
  USE SIGNAL ;
  PORT
   LAYER M4 ;
   RECT 354.156000 157.104000 354.240000 157.128000 ;
  END
 END p_q[357]
 PIN p_q[358]
  DIRECTION OUTPUT ;
  USE SIGNAL ;
  PORT
   LAYER M4 ;
   RECT 354.156000 157.296000 354.240000 157.320000 ;
  END
 END p_q[358]
 PIN p_q[359]
  DIRECTION OUTPUT ;
  USE SIGNAL ;
  PORT
   LAYER M4 ;
   RECT 354.156000 157.488000 354.240000 157.512000 ;
  END
 END p_q[359]
 PIN p_q[360]
  DIRECTION OUTPUT ;
  USE SIGNAL ;
  PORT
   LAYER M4 ;
   RECT 354.156000 157.680000 354.240000 157.704000 ;
  END
 END p_q[360]
 PIN p_q[361]
  DIRECTION OUTPUT ;
  USE SIGNAL ;
  PORT
   LAYER M4 ;
   RECT 354.156000 157.872000 354.240000 157.896000 ;
  END
 END p_q[361]
 PIN p_q[362]
  DIRECTION OUTPUT ;
  USE SIGNAL ;
  PORT
   LAYER M4 ;
   RECT 354.156000 158.064000 354.240000 158.088000 ;
  END
 END p_q[362]
 PIN p_q[363]
  DIRECTION OUTPUT ;
  USE SIGNAL ;
  PORT
   LAYER M4 ;
   RECT 354.156000 158.256000 354.240000 158.280000 ;
  END
 END p_q[363]
 PIN p_q[364]
  DIRECTION OUTPUT ;
  USE SIGNAL ;
  PORT
   LAYER M4 ;
   RECT 354.156000 158.448000 354.240000 158.472000 ;
  END
 END p_q[364]
 PIN p_q[365]
  DIRECTION OUTPUT ;
  USE SIGNAL ;
  PORT
   LAYER M4 ;
   RECT 354.156000 158.640000 354.240000 158.664000 ;
  END
 END p_q[365]
 PIN p_q[366]
  DIRECTION OUTPUT ;
  USE SIGNAL ;
  PORT
   LAYER M4 ;
   RECT 354.156000 158.832000 354.240000 158.856000 ;
  END
 END p_q[366]
 PIN p_q[367]
  DIRECTION OUTPUT ;
  USE SIGNAL ;
  PORT
   LAYER M4 ;
   RECT 354.156000 159.024000 354.240000 159.048000 ;
  END
 END p_q[367]
 PIN p_q[368]
  DIRECTION OUTPUT ;
  USE SIGNAL ;
  PORT
   LAYER M4 ;
   RECT 354.156000 159.216000 354.240000 159.240000 ;
  END
 END p_q[368]
 PIN p_q[369]
  DIRECTION OUTPUT ;
  USE SIGNAL ;
  PORT
   LAYER M4 ;
   RECT 354.156000 159.408000 354.240000 159.432000 ;
  END
 END p_q[369]
 PIN p_q[370]
  DIRECTION OUTPUT ;
  USE SIGNAL ;
  PORT
   LAYER M4 ;
   RECT 354.156000 159.600000 354.240000 159.624000 ;
  END
 END p_q[370]
 PIN p_q[371]
  DIRECTION OUTPUT ;
  USE SIGNAL ;
  PORT
   LAYER M4 ;
   RECT 354.156000 159.792000 354.240000 159.816000 ;
  END
 END p_q[371]
 PIN p_q[372]
  DIRECTION OUTPUT ;
  USE SIGNAL ;
  PORT
   LAYER M4 ;
   RECT 354.156000 159.984000 354.240000 160.008000 ;
  END
 END p_q[372]
 PIN p_q[373]
  DIRECTION OUTPUT ;
  USE SIGNAL ;
  PORT
   LAYER M4 ;
   RECT 354.156000 160.176000 354.240000 160.200000 ;
  END
 END p_q[373]
 PIN p_q[374]
  DIRECTION OUTPUT ;
  USE SIGNAL ;
  PORT
   LAYER M4 ;
   RECT 354.156000 160.368000 354.240000 160.392000 ;
  END
 END p_q[374]
 PIN p_q[375]
  DIRECTION OUTPUT ;
  USE SIGNAL ;
  PORT
   LAYER M4 ;
   RECT 354.156000 160.560000 354.240000 160.584000 ;
  END
 END p_q[375]
 PIN p_q[376]
  DIRECTION OUTPUT ;
  USE SIGNAL ;
  PORT
   LAYER M4 ;
   RECT 354.156000 160.752000 354.240000 160.776000 ;
  END
 END p_q[376]
 PIN p_q[377]
  DIRECTION OUTPUT ;
  USE SIGNAL ;
  PORT
   LAYER M4 ;
   RECT 354.156000 160.944000 354.240000 160.968000 ;
  END
 END p_q[377]
 PIN p_q[378]
  DIRECTION OUTPUT ;
  USE SIGNAL ;
  PORT
   LAYER M4 ;
   RECT 354.156000 161.136000 354.240000 161.160000 ;
  END
 END p_q[378]
 PIN p_q[379]
  DIRECTION OUTPUT ;
  USE SIGNAL ;
  PORT
   LAYER M4 ;
   RECT 354.156000 161.328000 354.240000 161.352000 ;
  END
 END p_q[379]
 PIN p_q[380]
  DIRECTION OUTPUT ;
  USE SIGNAL ;
  PORT
   LAYER M4 ;
   RECT 354.156000 161.520000 354.240000 161.544000 ;
  END
 END p_q[380]
 PIN p_q[381]
  DIRECTION OUTPUT ;
  USE SIGNAL ;
  PORT
   LAYER M4 ;
   RECT 354.156000 161.712000 354.240000 161.736000 ;
  END
 END p_q[381]
 PIN p_q[382]
  DIRECTION OUTPUT ;
  USE SIGNAL ;
  PORT
   LAYER M4 ;
   RECT 354.156000 161.904000 354.240000 161.928000 ;
  END
 END p_q[382]
 PIN p_q[383]
  DIRECTION OUTPUT ;
  USE SIGNAL ;
  PORT
   LAYER M4 ;
   RECT 354.156000 162.096000 354.240000 162.120000 ;
  END
 END p_q[383]
 PIN p_q[384]
  DIRECTION OUTPUT ;
  USE SIGNAL ;
  PORT
   LAYER M4 ;
   RECT 354.156000 162.288000 354.240000 162.312000 ;
  END
 END p_q[384]
 PIN p_q[385]
  DIRECTION OUTPUT ;
  USE SIGNAL ;
  PORT
   LAYER M4 ;
   RECT 354.156000 162.480000 354.240000 162.504000 ;
  END
 END p_q[385]
 PIN p_q[386]
  DIRECTION OUTPUT ;
  USE SIGNAL ;
  PORT
   LAYER M4 ;
   RECT 354.156000 162.672000 354.240000 162.696000 ;
  END
 END p_q[386]
 PIN p_q[387]
  DIRECTION OUTPUT ;
  USE SIGNAL ;
  PORT
   LAYER M4 ;
   RECT 354.156000 162.864000 354.240000 162.888000 ;
  END
 END p_q[387]
 PIN p_q[388]
  DIRECTION OUTPUT ;
  USE SIGNAL ;
  PORT
   LAYER M4 ;
   RECT 354.156000 163.056000 354.240000 163.080000 ;
  END
 END p_q[388]
 PIN p_q[389]
  DIRECTION OUTPUT ;
  USE SIGNAL ;
  PORT
   LAYER M4 ;
   RECT 354.156000 163.248000 354.240000 163.272000 ;
  END
 END p_q[389]
 PIN p_q[390]
  DIRECTION OUTPUT ;
  USE SIGNAL ;
  PORT
   LAYER M4 ;
   RECT 354.156000 163.440000 354.240000 163.464000 ;
  END
 END p_q[390]
 PIN p_q[391]
  DIRECTION OUTPUT ;
  USE SIGNAL ;
  PORT
   LAYER M4 ;
   RECT 354.156000 163.632000 354.240000 163.656000 ;
  END
 END p_q[391]
 PIN p_q[392]
  DIRECTION OUTPUT ;
  USE SIGNAL ;
  PORT
   LAYER M4 ;
   RECT 354.156000 163.824000 354.240000 163.848000 ;
  END
 END p_q[392]
 PIN p_q[393]
  DIRECTION OUTPUT ;
  USE SIGNAL ;
  PORT
   LAYER M4 ;
   RECT 354.156000 164.016000 354.240000 164.040000 ;
  END
 END p_q[393]
 PIN p_q[394]
  DIRECTION OUTPUT ;
  USE SIGNAL ;
  PORT
   LAYER M4 ;
   RECT 354.156000 164.208000 354.240000 164.232000 ;
  END
 END p_q[394]
 PIN p_q[395]
  DIRECTION OUTPUT ;
  USE SIGNAL ;
  PORT
   LAYER M4 ;
   RECT 354.156000 164.400000 354.240000 164.424000 ;
  END
 END p_q[395]
 PIN p_q[396]
  DIRECTION OUTPUT ;
  USE SIGNAL ;
  PORT
   LAYER M4 ;
   RECT 354.156000 164.592000 354.240000 164.616000 ;
  END
 END p_q[396]
 PIN p_q[397]
  DIRECTION OUTPUT ;
  USE SIGNAL ;
  PORT
   LAYER M4 ;
   RECT 354.156000 164.784000 354.240000 164.808000 ;
  END
 END p_q[397]
 PIN p_q[398]
  DIRECTION OUTPUT ;
  USE SIGNAL ;
  PORT
   LAYER M4 ;
   RECT 354.156000 164.976000 354.240000 165.000000 ;
  END
 END p_q[398]
 PIN p_q[399]
  DIRECTION OUTPUT ;
  USE SIGNAL ;
  PORT
   LAYER M4 ;
   RECT 354.156000 165.168000 354.240000 165.192000 ;
  END
 END p_q[399]
 PIN p_q[400]
  DIRECTION OUTPUT ;
  USE SIGNAL ;
  PORT
   LAYER M4 ;
   RECT 354.156000 165.360000 354.240000 165.384000 ;
  END
 END p_q[400]
 PIN p_q[401]
  DIRECTION OUTPUT ;
  USE SIGNAL ;
  PORT
   LAYER M4 ;
   RECT 354.156000 165.552000 354.240000 165.576000 ;
  END
 END p_q[401]
 PIN p_q[402]
  DIRECTION OUTPUT ;
  USE SIGNAL ;
  PORT
   LAYER M4 ;
   RECT 354.156000 165.744000 354.240000 165.768000 ;
  END
 END p_q[402]
 PIN p_q[403]
  DIRECTION OUTPUT ;
  USE SIGNAL ;
  PORT
   LAYER M4 ;
   RECT 354.156000 165.936000 354.240000 165.960000 ;
  END
 END p_q[403]
 PIN p_q[404]
  DIRECTION OUTPUT ;
  USE SIGNAL ;
  PORT
   LAYER M4 ;
   RECT 354.156000 166.128000 354.240000 166.152000 ;
  END
 END p_q[404]
 PIN p_q[405]
  DIRECTION OUTPUT ;
  USE SIGNAL ;
  PORT
   LAYER M4 ;
   RECT 354.156000 166.320000 354.240000 166.344000 ;
  END
 END p_q[405]
 PIN p_q[406]
  DIRECTION OUTPUT ;
  USE SIGNAL ;
  PORT
   LAYER M4 ;
   RECT 354.156000 166.512000 354.240000 166.536000 ;
  END
 END p_q[406]
 PIN p_q[407]
  DIRECTION OUTPUT ;
  USE SIGNAL ;
  PORT
   LAYER M4 ;
   RECT 354.156000 166.704000 354.240000 166.728000 ;
  END
 END p_q[407]
 PIN p_q[408]
  DIRECTION OUTPUT ;
  USE SIGNAL ;
  PORT
   LAYER M4 ;
   RECT 354.156000 166.896000 354.240000 166.920000 ;
  END
 END p_q[408]
 PIN p_q[409]
  DIRECTION OUTPUT ;
  USE SIGNAL ;
  PORT
   LAYER M4 ;
   RECT 354.156000 167.088000 354.240000 167.112000 ;
  END
 END p_q[409]
 PIN p_q[410]
  DIRECTION OUTPUT ;
  USE SIGNAL ;
  PORT
   LAYER M4 ;
   RECT 354.156000 167.280000 354.240000 167.304000 ;
  END
 END p_q[410]
 PIN p_q[411]
  DIRECTION OUTPUT ;
  USE SIGNAL ;
  PORT
   LAYER M4 ;
   RECT 354.156000 167.472000 354.240000 167.496000 ;
  END
 END p_q[411]
 PIN p_q[412]
  DIRECTION OUTPUT ;
  USE SIGNAL ;
  PORT
   LAYER M4 ;
   RECT 354.156000 167.664000 354.240000 167.688000 ;
  END
 END p_q[412]
 PIN p_q[413]
  DIRECTION OUTPUT ;
  USE SIGNAL ;
  PORT
   LAYER M4 ;
   RECT 354.156000 167.856000 354.240000 167.880000 ;
  END
 END p_q[413]
 PIN p_q[414]
  DIRECTION OUTPUT ;
  USE SIGNAL ;
  PORT
   LAYER M4 ;
   RECT 354.156000 168.048000 354.240000 168.072000 ;
  END
 END p_q[414]
 PIN p_q[415]
  DIRECTION OUTPUT ;
  USE SIGNAL ;
  PORT
   LAYER M4 ;
   RECT 354.156000 168.240000 354.240000 168.264000 ;
  END
 END p_q[415]
 PIN p_q[416]
  DIRECTION OUTPUT ;
  USE SIGNAL ;
  PORT
   LAYER M4 ;
   RECT 354.156000 168.432000 354.240000 168.456000 ;
  END
 END p_q[416]
 PIN p_q[417]
  DIRECTION OUTPUT ;
  USE SIGNAL ;
  PORT
   LAYER M4 ;
   RECT 354.156000 168.624000 354.240000 168.648000 ;
  END
 END p_q[417]
 PIN p_q[418]
  DIRECTION OUTPUT ;
  USE SIGNAL ;
  PORT
   LAYER M4 ;
   RECT 354.156000 168.816000 354.240000 168.840000 ;
  END
 END p_q[418]
 PIN p_q[419]
  DIRECTION OUTPUT ;
  USE SIGNAL ;
  PORT
   LAYER M4 ;
   RECT 354.156000 169.008000 354.240000 169.032000 ;
  END
 END p_q[419]
 PIN p_q[420]
  DIRECTION OUTPUT ;
  USE SIGNAL ;
  PORT
   LAYER M4 ;
   RECT 354.156000 169.200000 354.240000 169.224000 ;
  END
 END p_q[420]
 PIN p_q[421]
  DIRECTION OUTPUT ;
  USE SIGNAL ;
  PORT
   LAYER M4 ;
   RECT 354.156000 169.392000 354.240000 169.416000 ;
  END
 END p_q[421]
 PIN p_q[422]
  DIRECTION OUTPUT ;
  USE SIGNAL ;
  PORT
   LAYER M4 ;
   RECT 354.156000 169.584000 354.240000 169.608000 ;
  END
 END p_q[422]
 PIN p_q[423]
  DIRECTION OUTPUT ;
  USE SIGNAL ;
  PORT
   LAYER M4 ;
   RECT 354.156000 169.776000 354.240000 169.800000 ;
  END
 END p_q[423]
 PIN p_q[424]
  DIRECTION OUTPUT ;
  USE SIGNAL ;
  PORT
   LAYER M4 ;
   RECT 354.156000 169.968000 354.240000 169.992000 ;
  END
 END p_q[424]
 PIN p_q[425]
  DIRECTION OUTPUT ;
  USE SIGNAL ;
  PORT
   LAYER M4 ;
   RECT 354.156000 170.160000 354.240000 170.184000 ;
  END
 END p_q[425]
 PIN p_q[426]
  DIRECTION OUTPUT ;
  USE SIGNAL ;
  PORT
   LAYER M4 ;
   RECT 354.156000 170.352000 354.240000 170.376000 ;
  END
 END p_q[426]
 PIN p_q[427]
  DIRECTION OUTPUT ;
  USE SIGNAL ;
  PORT
   LAYER M4 ;
   RECT 354.156000 170.544000 354.240000 170.568000 ;
  END
 END p_q[427]
 PIN p_q[428]
  DIRECTION OUTPUT ;
  USE SIGNAL ;
  PORT
   LAYER M4 ;
   RECT 354.156000 170.736000 354.240000 170.760000 ;
  END
 END p_q[428]
 PIN p_q[429]
  DIRECTION OUTPUT ;
  USE SIGNAL ;
  PORT
   LAYER M4 ;
   RECT 354.156000 170.928000 354.240000 170.952000 ;
  END
 END p_q[429]
 PIN p_q[430]
  DIRECTION OUTPUT ;
  USE SIGNAL ;
  PORT
   LAYER M4 ;
   RECT 354.156000 171.120000 354.240000 171.144000 ;
  END
 END p_q[430]
 PIN p_q[431]
  DIRECTION OUTPUT ;
  USE SIGNAL ;
  PORT
   LAYER M4 ;
   RECT 354.156000 171.312000 354.240000 171.336000 ;
  END
 END p_q[431]
 PIN p_q[432]
  DIRECTION OUTPUT ;
  USE SIGNAL ;
  PORT
   LAYER M4 ;
   RECT 354.156000 171.504000 354.240000 171.528000 ;
  END
 END p_q[432]
 PIN p_q[433]
  DIRECTION OUTPUT ;
  USE SIGNAL ;
  PORT
   LAYER M4 ;
   RECT 354.156000 171.696000 354.240000 171.720000 ;
  END
 END p_q[433]
 PIN p_q[434]
  DIRECTION OUTPUT ;
  USE SIGNAL ;
  PORT
   LAYER M4 ;
   RECT 354.156000 171.888000 354.240000 171.912000 ;
  END
 END p_q[434]
 PIN p_q[435]
  DIRECTION OUTPUT ;
  USE SIGNAL ;
  PORT
   LAYER M4 ;
   RECT 354.156000 172.080000 354.240000 172.104000 ;
  END
 END p_q[435]
 PIN p_q[436]
  DIRECTION OUTPUT ;
  USE SIGNAL ;
  PORT
   LAYER M4 ;
   RECT 354.156000 172.272000 354.240000 172.296000 ;
  END
 END p_q[436]
 PIN p_q[437]
  DIRECTION OUTPUT ;
  USE SIGNAL ;
  PORT
   LAYER M4 ;
   RECT 354.156000 172.464000 354.240000 172.488000 ;
  END
 END p_q[437]
 PIN p_q[438]
  DIRECTION OUTPUT ;
  USE SIGNAL ;
  PORT
   LAYER M4 ;
   RECT 354.156000 172.656000 354.240000 172.680000 ;
  END
 END p_q[438]
 PIN p_q[439]
  DIRECTION OUTPUT ;
  USE SIGNAL ;
  PORT
   LAYER M4 ;
   RECT 354.156000 172.848000 354.240000 172.872000 ;
  END
 END p_q[439]
 PIN p_q[440]
  DIRECTION OUTPUT ;
  USE SIGNAL ;
  PORT
   LAYER M4 ;
   RECT 354.156000 173.040000 354.240000 173.064000 ;
  END
 END p_q[440]
 PIN p_q[441]
  DIRECTION OUTPUT ;
  USE SIGNAL ;
  PORT
   LAYER M4 ;
   RECT 354.156000 173.232000 354.240000 173.256000 ;
  END
 END p_q[441]
 PIN p_q[442]
  DIRECTION OUTPUT ;
  USE SIGNAL ;
  PORT
   LAYER M4 ;
   RECT 354.156000 173.424000 354.240000 173.448000 ;
  END
 END p_q[442]
 PIN p_q[443]
  DIRECTION OUTPUT ;
  USE SIGNAL ;
  PORT
   LAYER M4 ;
   RECT 354.156000 173.616000 354.240000 173.640000 ;
  END
 END p_q[443]
 PIN p_q[444]
  DIRECTION OUTPUT ;
  USE SIGNAL ;
  PORT
   LAYER M4 ;
   RECT 354.156000 173.808000 354.240000 173.832000 ;
  END
 END p_q[444]
 PIN p_q[445]
  DIRECTION OUTPUT ;
  USE SIGNAL ;
  PORT
   LAYER M4 ;
   RECT 354.156000 174.000000 354.240000 174.024000 ;
  END
 END p_q[445]
 PIN p_q[446]
  DIRECTION OUTPUT ;
  USE SIGNAL ;
  PORT
   LAYER M4 ;
   RECT 354.156000 174.192000 354.240000 174.216000 ;
  END
 END p_q[446]
 PIN p_q[447]
  DIRECTION OUTPUT ;
  USE SIGNAL ;
  PORT
   LAYER M4 ;
   RECT 354.156000 174.384000 354.240000 174.408000 ;
  END
 END p_q[447]
 PIN p_q[448]
  DIRECTION OUTPUT ;
  USE SIGNAL ;
  PORT
   LAYER M4 ;
   RECT 354.156000 174.576000 354.240000 174.600000 ;
  END
 END p_q[448]
 PIN p_q[449]
  DIRECTION OUTPUT ;
  USE SIGNAL ;
  PORT
   LAYER M4 ;
   RECT 354.156000 174.768000 354.240000 174.792000 ;
  END
 END p_q[449]
 PIN p_q[450]
  DIRECTION OUTPUT ;
  USE SIGNAL ;
  PORT
   LAYER M4 ;
   RECT 354.156000 174.960000 354.240000 174.984000 ;
  END
 END p_q[450]
 PIN p_q[451]
  DIRECTION OUTPUT ;
  USE SIGNAL ;
  PORT
   LAYER M4 ;
   RECT 354.156000 175.152000 354.240000 175.176000 ;
  END
 END p_q[451]
 PIN p_q[452]
  DIRECTION OUTPUT ;
  USE SIGNAL ;
  PORT
   LAYER M4 ;
   RECT 354.156000 175.344000 354.240000 175.368000 ;
  END
 END p_q[452]
 PIN p_q[453]
  DIRECTION OUTPUT ;
  USE SIGNAL ;
  PORT
   LAYER M4 ;
   RECT 354.156000 175.536000 354.240000 175.560000 ;
  END
 END p_q[453]
 PIN p_q[454]
  DIRECTION OUTPUT ;
  USE SIGNAL ;
  PORT
   LAYER M4 ;
   RECT 354.156000 175.728000 354.240000 175.752000 ;
  END
 END p_q[454]
 PIN p_q[455]
  DIRECTION OUTPUT ;
  USE SIGNAL ;
  PORT
   LAYER M4 ;
   RECT 354.156000 175.920000 354.240000 175.944000 ;
  END
 END p_q[455]
 PIN p_q[456]
  DIRECTION OUTPUT ;
  USE SIGNAL ;
  PORT
   LAYER M4 ;
   RECT 354.156000 176.112000 354.240000 176.136000 ;
  END
 END p_q[456]
 PIN tw_addr[0]
  DIRECTION INPUT ;
  USE SIGNAL ;
  PORT
   LAYER M5 ;
   RECT 302.400000 0.000000 302.424000 0.084000 ;
  END
 END tw_addr[0]
 PIN tw_addr[1]
  DIRECTION INPUT ;
  USE SIGNAL ;
  PORT
   LAYER M5 ;
   RECT 302.592000 0.000000 302.616000 0.084000 ;
  END
 END tw_addr[1]
 PIN tw_addr[2]
  DIRECTION INPUT ;
  USE SIGNAL ;
  PORT
   LAYER M5 ;
   RECT 302.784000 0.000000 302.808000 0.084000 ;
  END
 END tw_addr[2]
 PIN tw_addr[3]
  DIRECTION INPUT ;
  USE SIGNAL ;
  PORT
   LAYER M5 ;
   RECT 302.976000 0.000000 303.000000 0.084000 ;
  END
 END tw_addr[3]
 PIN tw_addr[4]
  DIRECTION INPUT ;
  USE SIGNAL ;
  PORT
   LAYER M5 ;
   RECT 303.168000 0.000000 303.192000 0.084000 ;
  END
 END tw_addr[4]
 PIN tw_addr[5]
  DIRECTION INPUT ;
  USE SIGNAL ;
  PORT
   LAYER M5 ;
   RECT 303.360000 0.000000 303.384000 0.084000 ;
  END
 END tw_addr[5]
 PIN tw_addr[6]
  DIRECTION INPUT ;
  USE SIGNAL ;
  PORT
   LAYER M5 ;
   RECT 303.552000 0.000000 303.576000 0.084000 ;
  END
 END tw_addr[6]
 PIN tw_addr[7]
  DIRECTION INPUT ;
  USE SIGNAL ;
  PORT
   LAYER M5 ;
   RECT 303.744000 0.000000 303.768000 0.084000 ;
  END
 END tw_addr[7]
 PIN tw_kind[0]
  DIRECTION INPUT ;
  USE SIGNAL ;
  PORT
   LAYER M5 ;
   RECT 307.584000 0.000000 307.608000 0.084000 ;
  END
 END tw_kind[0]
 PIN tw_kind[1]
  DIRECTION INPUT ;
  USE SIGNAL ;
  PORT
   LAYER M5 ;
   RECT 307.776000 0.000000 307.800000 0.084000 ;
  END
 END tw_kind[1]
 PIN tw_we
  DIRECTION INPUT ;
  USE SIGNAL ;
  PORT
   LAYER M5 ;
   RECT 310.176000 0.000000 310.200000 0.084000 ;
  END
 END tw_we
 PIN ck
  DIRECTION INPUT ;
  USE CLOCK ;
  PORT
   LAYER M5 ;
   RECT 178.128000 0.000000 178.152000 0.084000 ;
  END
 END ck
END qfd_dv_s8x_prog
END LIBRARY
